VERSION 5.8 ;
BUSBITCHARS "[]" ;
DIVIDERCHAR "/" ;
UNITS
    DATABASE MICRONS 1000 ;
END UNITS

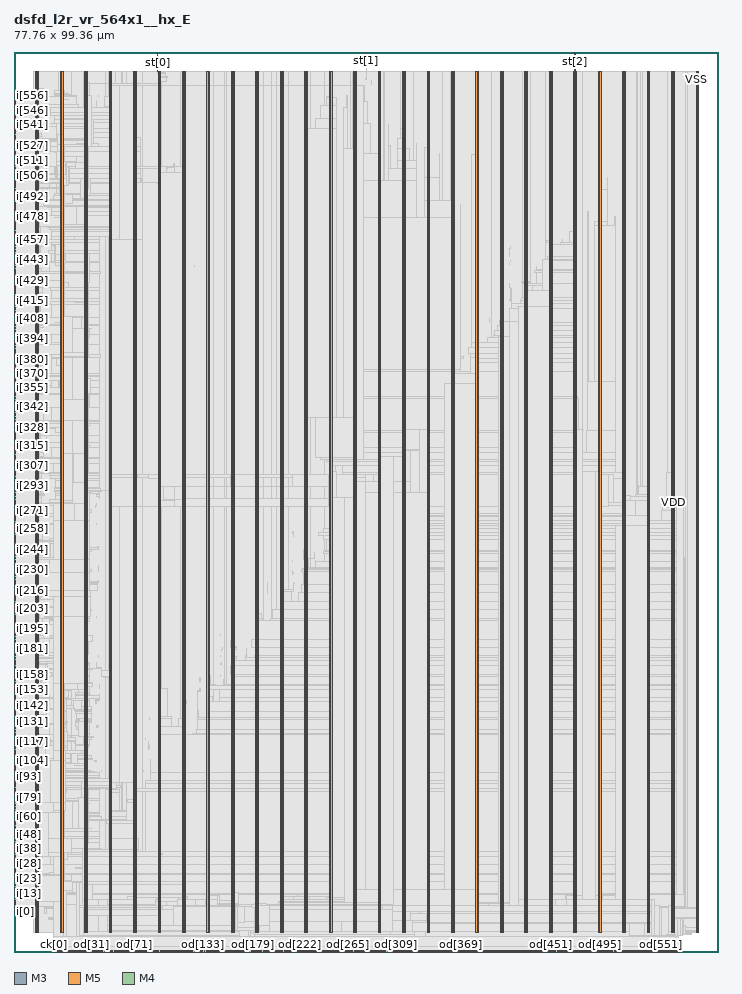
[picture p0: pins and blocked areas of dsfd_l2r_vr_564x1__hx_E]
MACRO dsfd_l2r_vr_564x1__hx_E
  FOREIGN dsfd_l2r_vr_564x1__hx_E 0 0 ;
  CLASS BLOCK ;
  SIZE 77.76 BY 99.36 ;
  PIN ck[0]
    DIRECTION INPUT ;
    USE SIGNAL ;
    PORT
      LAYER M3 ;
        RECT  4.356 0 4.374 0.144 ;
    END
  END ck[0]
  PIN cks[0]
    DIRECTION INPUT ;
    USE SIGNAL ;
    PORT
      LAYER M5 ;
        RECT  4.512 0 4.536 0.192 ;
    END
    PORT
      LAYER M5 ;
        RECT  4.368 0.133 4.632 0.144 ;
    END
  END cks[0]
  PIN fo[0]
    DIRECTION OUTPUT ;
    USE SIGNAL ;
    PORT
      LAYER M3 ;
        RECT  4.608 0 4.626 0.144 ;
    END
  END fo[0]
  PIN i[0]
    DIRECTION INPUT ;
    USE SIGNAL ;
    PORT
      LAYER M4 ;
        RECT  0 4.416 0.192 4.44 ;
    END
  END i[0]
  PIN i[100]
    DIRECTION INPUT ;
    USE SIGNAL ;
    PORT
      LAYER M4 ;
        RECT  0 20.448 0.192 20.472 ;
    END
  END i[100]
  PIN i[101]
    DIRECTION INPUT ;
    USE SIGNAL ;
    PORT
      LAYER M4 ;
        RECT  0 20.64 0.192 20.664 ;
    END
  END i[101]
  PIN i[102]
    DIRECTION INPUT ;
    USE SIGNAL ;
    PORT
      LAYER M4 ;
        RECT  0 20.784 0.192 20.808 ;
    END
  END i[102]
  PIN i[103]
    DIRECTION INPUT ;
    USE SIGNAL ;
    PORT
      LAYER M4 ;
        RECT  0 20.928 0.192 20.952 ;
    END
  END i[103]
  PIN i[104]
    DIRECTION INPUT ;
    USE SIGNAL ;
    PORT
      LAYER M4 ;
        RECT  0 21.12 0.192 21.144 ;
    END
  END i[104]
  PIN i[105]
    DIRECTION INPUT ;
    USE SIGNAL ;
    PORT
      LAYER M4 ;
        RECT  0 21.264 0.192 21.288 ;
    END
  END i[105]
  PIN i[106]
    DIRECTION INPUT ;
    USE SIGNAL ;
    PORT
      LAYER M4 ;
        RECT  0 21.456 0.192 21.48 ;
    END
  END i[106]
  PIN i[107]
    DIRECTION INPUT ;
    USE SIGNAL ;
    PORT
      LAYER M4 ;
        RECT  0 21.6 0.192 21.624 ;
    END
  END i[107]
  PIN i[108]
    DIRECTION INPUT ;
    USE SIGNAL ;
    PORT
      LAYER M4 ;
        RECT  0 21.744 0.192 21.768 ;
    END
  END i[108]
  PIN i[109]
    DIRECTION INPUT ;
    USE SIGNAL ;
    PORT
      LAYER M4 ;
        RECT  0 21.936 0.192 21.96 ;
    END
  END i[109]
  PIN i[10]
    DIRECTION INPUT ;
    USE SIGNAL ;
    PORT
      LAYER M4 ;
        RECT  0 6 0.192 6.024 ;
    END
  END i[10]
  PIN i[110]
    DIRECTION INPUT ;
    USE SIGNAL ;
    PORT
      LAYER M4 ;
        RECT  0 22.08 0.192 22.104 ;
    END
  END i[110]
  PIN i[111]
    DIRECTION INPUT ;
    USE SIGNAL ;
    PORT
      LAYER M4 ;
        RECT  0 22.224 0.192 22.248 ;
    END
  END i[111]
  PIN i[112]
    DIRECTION INPUT ;
    USE SIGNAL ;
    PORT
      LAYER M4 ;
        RECT  0 22.416 0.192 22.44 ;
    END
  END i[112]
  PIN i[113]
    DIRECTION INPUT ;
    USE SIGNAL ;
    PORT
      LAYER M4 ;
        RECT  0 22.56 0.192 22.584 ;
    END
  END i[113]
  PIN i[114]
    DIRECTION INPUT ;
    USE SIGNAL ;
    PORT
      LAYER M4 ;
        RECT  0 22.704 0.192 22.728 ;
    END
  END i[114]
  PIN i[115]
    DIRECTION INPUT ;
    USE SIGNAL ;
    PORT
      LAYER M4 ;
        RECT  0 22.896 0.192 22.92 ;
    END
  END i[115]
  PIN i[116]
    DIRECTION INPUT ;
    USE SIGNAL ;
    PORT
      LAYER M4 ;
        RECT  0 23.04 0.192 23.064 ;
    END
  END i[116]
  PIN i[117]
    DIRECTION INPUT ;
    USE SIGNAL ;
    PORT
      LAYER M4 ;
        RECT  0 23.184 0.192 23.208 ;
    END
  END i[117]
  PIN i[118]
    DIRECTION INPUT ;
    USE SIGNAL ;
    PORT
      LAYER M4 ;
        RECT  0 23.376 0.192 23.4 ;
    END
  END i[118]
  PIN i[119]
    DIRECTION INPUT ;
    USE SIGNAL ;
    PORT
      LAYER M4 ;
        RECT  0 23.52 0.192 23.544 ;
    END
  END i[119]
  PIN i[11]
    DIRECTION INPUT ;
    USE SIGNAL ;
    PORT
      LAYER M4 ;
        RECT  0 6.192 0.192 6.216 ;
    END
  END i[11]
  PIN i[120]
    DIRECTION INPUT ;
    USE SIGNAL ;
    PORT
      LAYER M4 ;
        RECT  0 23.664 0.192 23.688 ;
    END
  END i[120]
  PIN i[121]
    DIRECTION INPUT ;
    USE SIGNAL ;
    PORT
      LAYER M4 ;
        RECT  0 23.856 0.192 23.88 ;
    END
  END i[121]
  PIN i[122]
    DIRECTION INPUT ;
    USE SIGNAL ;
    PORT
      LAYER M4 ;
        RECT  0 24 0.192 24.024 ;
    END
  END i[122]
  PIN i[123]
    DIRECTION INPUT ;
    USE SIGNAL ;
    PORT
      LAYER M4 ;
        RECT  0 24.144 0.192 24.168 ;
    END
  END i[123]
  PIN i[124]
    DIRECTION INPUT ;
    USE SIGNAL ;
    PORT
      LAYER M4 ;
        RECT  0 24.336 0.192 24.36 ;
    END
  END i[124]
  PIN i[125]
    DIRECTION INPUT ;
    USE SIGNAL ;
    PORT
      LAYER M4 ;
        RECT  0 24.48 0.192 24.504 ;
    END
  END i[125]
  PIN i[126]
    DIRECTION INPUT ;
    USE SIGNAL ;
    PORT
      LAYER M4 ;
        RECT  0 24.624 0.192 24.648 ;
    END
  END i[126]
  PIN i[127]
    DIRECTION INPUT ;
    USE SIGNAL ;
    PORT
      LAYER M4 ;
        RECT  0 24.816 0.192 24.84 ;
    END
  END i[127]
  PIN i[128]
    DIRECTION INPUT ;
    USE SIGNAL ;
    PORT
      LAYER M4 ;
        RECT  0 24.96 0.192 24.984 ;
    END
  END i[128]
  PIN i[129]
    DIRECTION INPUT ;
    USE SIGNAL ;
    PORT
      LAYER M4 ;
        RECT  0 25.104 0.192 25.128 ;
    END
  END i[129]
  PIN i[12]
    DIRECTION INPUT ;
    USE SIGNAL ;
    PORT
      LAYER M4 ;
        RECT  0 6.336 0.192 6.36 ;
    END
  END i[12]
  PIN i[130]
    DIRECTION INPUT ;
    USE SIGNAL ;
    PORT
      LAYER M4 ;
        RECT  0 25.296 0.192 25.32 ;
    END
  END i[130]
  PIN i[131]
    DIRECTION INPUT ;
    USE SIGNAL ;
    PORT
      LAYER M4 ;
        RECT  0 25.44 0.192 25.464 ;
    END
  END i[131]
  PIN i[132]
    DIRECTION INPUT ;
    USE SIGNAL ;
    PORT
      LAYER M4 ;
        RECT  0 25.584 0.192 25.608 ;
    END
  END i[132]
  PIN i[133]
    DIRECTION INPUT ;
    USE SIGNAL ;
    PORT
      LAYER M4 ;
        RECT  0 25.776 0.192 25.8 ;
    END
  END i[133]
  PIN i[134]
    DIRECTION INPUT ;
    USE SIGNAL ;
    PORT
      LAYER M4 ;
        RECT  0 25.92 0.192 25.944 ;
    END
  END i[134]
  PIN i[135]
    DIRECTION INPUT ;
    USE SIGNAL ;
    PORT
      LAYER M4 ;
        RECT  0 26.112 0.192 26.136 ;
    END
  END i[135]
  PIN i[136]
    DIRECTION INPUT ;
    USE SIGNAL ;
    PORT
      LAYER M4 ;
        RECT  0 26.256 0.192 26.28 ;
    END
  END i[136]
  PIN i[137]
    DIRECTION INPUT ;
    USE SIGNAL ;
    PORT
      LAYER M4 ;
        RECT  0 26.4 0.192 26.424 ;
    END
  END i[137]
  PIN i[138]
    DIRECTION INPUT ;
    USE SIGNAL ;
    PORT
      LAYER M4 ;
        RECT  0 26.592 0.192 26.616 ;
    END
  END i[138]
  PIN i[139]
    DIRECTION INPUT ;
    USE SIGNAL ;
    PORT
      LAYER M4 ;
        RECT  0 26.736 0.192 26.76 ;
    END
  END i[139]
  PIN i[13]
    DIRECTION INPUT ;
    USE SIGNAL ;
    PORT
      LAYER M4 ;
        RECT  0 6.48 0.192 6.504 ;
    END
  END i[13]
  PIN i[140]
    DIRECTION INPUT ;
    USE SIGNAL ;
    PORT
      LAYER M4 ;
        RECT  0 26.88 0.192 26.904 ;
    END
  END i[140]
  PIN i[141]
    DIRECTION INPUT ;
    USE SIGNAL ;
    PORT
      LAYER M4 ;
        RECT  0 27.072 0.192 27.096 ;
    END
  END i[141]
  PIN i[142]
    DIRECTION INPUT ;
    USE SIGNAL ;
    PORT
      LAYER M4 ;
        RECT  0 27.216 0.192 27.24 ;
    END
  END i[142]
  PIN i[143]
    DIRECTION INPUT ;
    USE SIGNAL ;
    PORT
      LAYER M4 ;
        RECT  0 27.36 0.192 27.384 ;
    END
  END i[143]
  PIN i[144]
    DIRECTION INPUT ;
    USE SIGNAL ;
    PORT
      LAYER M4 ;
        RECT  0 27.552 0.192 27.576 ;
    END
  END i[144]
  PIN i[145]
    DIRECTION INPUT ;
    USE SIGNAL ;
    PORT
      LAYER M4 ;
        RECT  0 27.696 0.192 27.72 ;
    END
  END i[145]
  PIN i[146]
    DIRECTION INPUT ;
    USE SIGNAL ;
    PORT
      LAYER M4 ;
        RECT  0 27.84 0.192 27.864 ;
    END
  END i[146]
  PIN i[147]
    DIRECTION INPUT ;
    USE SIGNAL ;
    PORT
      LAYER M4 ;
        RECT  0 28.032 0.192 28.056 ;
    END
  END i[147]
  PIN i[148]
    DIRECTION INPUT ;
    USE SIGNAL ;
    PORT
      LAYER M4 ;
        RECT  0 28.176 0.192 28.2 ;
    END
  END i[148]
  PIN i[149]
    DIRECTION INPUT ;
    USE SIGNAL ;
    PORT
      LAYER M4 ;
        RECT  0 28.32 0.192 28.344 ;
    END
  END i[149]
  PIN i[14]
    DIRECTION INPUT ;
    USE SIGNAL ;
    PORT
      LAYER M4 ;
        RECT  0 6.672 0.192 6.696 ;
    END
  END i[14]
  PIN i[150]
    DIRECTION INPUT ;
    USE SIGNAL ;
    PORT
      LAYER M4 ;
        RECT  0 28.512 0.192 28.536 ;
    END
  END i[150]
  PIN i[151]
    DIRECTION INPUT ;
    USE SIGNAL ;
    PORT
      LAYER M4 ;
        RECT  0 28.656 0.192 28.68 ;
    END
  END i[151]
  PIN i[152]
    DIRECTION INPUT ;
    USE SIGNAL ;
    PORT
      LAYER M4 ;
        RECT  0 28.8 0.192 28.824 ;
    END
  END i[152]
  PIN i[153]
    DIRECTION INPUT ;
    USE SIGNAL ;
    PORT
      LAYER M4 ;
        RECT  0 28.992 0.192 29.016 ;
    END
  END i[153]
  PIN i[154]
    DIRECTION INPUT ;
    USE SIGNAL ;
    PORT
      LAYER M4 ;
        RECT  0 29.136 0.192 29.16 ;
    END
  END i[154]
  PIN i[155]
    DIRECTION INPUT ;
    USE SIGNAL ;
    PORT
      LAYER M4 ;
        RECT  0 29.28 0.192 29.304 ;
    END
  END i[155]
  PIN i[156]
    DIRECTION INPUT ;
    USE SIGNAL ;
    PORT
      LAYER M4 ;
        RECT  0 29.472 0.192 29.496 ;
    END
  END i[156]
  PIN i[157]
    DIRECTION INPUT ;
    USE SIGNAL ;
    PORT
      LAYER M4 ;
        RECT  0 29.616 0.192 29.64 ;
    END
  END i[157]
  PIN i[158]
    DIRECTION INPUT ;
    USE SIGNAL ;
    PORT
      LAYER M4 ;
        RECT  0 29.76 0.192 29.784 ;
    END
  END i[158]
  PIN i[159]
    DIRECTION INPUT ;
    USE SIGNAL ;
    PORT
      LAYER M4 ;
        RECT  0 29.952 0.192 29.976 ;
    END
  END i[159]
  PIN i[15]
    DIRECTION INPUT ;
    USE SIGNAL ;
    PORT
      LAYER M4 ;
        RECT  0 6.816 0.192 6.84 ;
    END
  END i[15]
  PIN i[160]
    DIRECTION INPUT ;
    USE SIGNAL ;
    PORT
      LAYER M4 ;
        RECT  0 30.096 0.192 30.12 ;
    END
  END i[160]
  PIN i[161]
    DIRECTION INPUT ;
    USE SIGNAL ;
    PORT
      LAYER M4 ;
        RECT  0 30.24 0.192 30.264 ;
    END
  END i[161]
  PIN i[162]
    DIRECTION INPUT ;
    USE SIGNAL ;
    PORT
      LAYER M4 ;
        RECT  0 30.432 0.192 30.456 ;
    END
  END i[162]
  PIN i[163]
    DIRECTION INPUT ;
    USE SIGNAL ;
    PORT
      LAYER M4 ;
        RECT  0 30.576 0.192 30.6 ;
    END
  END i[163]
  PIN i[164]
    DIRECTION INPUT ;
    USE SIGNAL ;
    PORT
      LAYER M4 ;
        RECT  0 30.768 0.192 30.792 ;
    END
  END i[164]
  PIN i[165]
    DIRECTION INPUT ;
    USE SIGNAL ;
    PORT
      LAYER M4 ;
        RECT  0 30.912 0.192 30.936 ;
    END
  END i[165]
  PIN i[166]
    DIRECTION INPUT ;
    USE SIGNAL ;
    PORT
      LAYER M4 ;
        RECT  0 31.056 0.192 31.08 ;
    END
  END i[166]
  PIN i[167]
    DIRECTION INPUT ;
    USE SIGNAL ;
    PORT
      LAYER M4 ;
        RECT  0 31.248 0.192 31.272 ;
    END
  END i[167]
  PIN i[168]
    DIRECTION INPUT ;
    USE SIGNAL ;
    PORT
      LAYER M4 ;
        RECT  0 31.392 0.192 31.416 ;
    END
  END i[168]
  PIN i[169]
    DIRECTION INPUT ;
    USE SIGNAL ;
    PORT
      LAYER M4 ;
        RECT  0 31.536 0.192 31.56 ;
    END
  END i[169]
  PIN i[16]
    DIRECTION INPUT ;
    USE SIGNAL ;
    PORT
      LAYER M4 ;
        RECT  0 6.96 0.192 6.984 ;
    END
  END i[16]
  PIN i[170]
    DIRECTION INPUT ;
    USE SIGNAL ;
    PORT
      LAYER M4 ;
        RECT  0 31.728 0.192 31.752 ;
    END
  END i[170]
  PIN i[171]
    DIRECTION INPUT ;
    USE SIGNAL ;
    PORT
      LAYER M4 ;
        RECT  0 31.872 0.192 31.896 ;
    END
  END i[171]
  PIN i[172]
    DIRECTION INPUT ;
    USE SIGNAL ;
    PORT
      LAYER M4 ;
        RECT  0 32.016 0.192 32.04 ;
    END
  END i[172]
  PIN i[173]
    DIRECTION INPUT ;
    USE SIGNAL ;
    PORT
      LAYER M4 ;
        RECT  0 32.208 0.192 32.232 ;
    END
  END i[173]
  PIN i[174]
    DIRECTION INPUT ;
    USE SIGNAL ;
    PORT
      LAYER M4 ;
        RECT  0 32.352 0.192 32.376 ;
    END
  END i[174]
  PIN i[175]
    DIRECTION INPUT ;
    USE SIGNAL ;
    PORT
      LAYER M4 ;
        RECT  0 32.496 0.192 32.52 ;
    END
  END i[175]
  PIN i[176]
    DIRECTION INPUT ;
    USE SIGNAL ;
    PORT
      LAYER M4 ;
        RECT  0 32.688 0.192 32.712 ;
    END
  END i[176]
  PIN i[177]
    DIRECTION INPUT ;
    USE SIGNAL ;
    PORT
      LAYER M4 ;
        RECT  0 32.832 0.192 32.856 ;
    END
  END i[177]
  PIN i[178]
    DIRECTION INPUT ;
    USE SIGNAL ;
    PORT
      LAYER M4 ;
        RECT  0 32.976 0.192 33 ;
    END
  END i[178]
  PIN i[179]
    DIRECTION INPUT ;
    USE SIGNAL ;
    PORT
      LAYER M4 ;
        RECT  0 33.168 0.192 33.192 ;
    END
  END i[179]
  PIN i[17]
    DIRECTION INPUT ;
    USE SIGNAL ;
    PORT
      LAYER M4 ;
        RECT  0 7.152 0.192 7.176 ;
    END
  END i[17]
  PIN i[180]
    DIRECTION INPUT ;
    USE SIGNAL ;
    PORT
      LAYER M4 ;
        RECT  0 33.312 0.192 33.336 ;
    END
  END i[180]
  PIN i[181]
    DIRECTION INPUT ;
    USE SIGNAL ;
    PORT
      LAYER M4 ;
        RECT  0 33.456 0.192 33.48 ;
    END
  END i[181]
  PIN i[182]
    DIRECTION INPUT ;
    USE SIGNAL ;
    PORT
      LAYER M4 ;
        RECT  0 33.648 0.192 33.672 ;
    END
  END i[182]
  PIN i[183]
    DIRECTION INPUT ;
    USE SIGNAL ;
    PORT
      LAYER M4 ;
        RECT  0 33.792 0.192 33.816 ;
    END
  END i[183]
  PIN i[184]
    DIRECTION INPUT ;
    USE SIGNAL ;
    PORT
      LAYER M4 ;
        RECT  0 33.936 0.192 33.96 ;
    END
  END i[184]
  PIN i[185]
    DIRECTION INPUT ;
    USE SIGNAL ;
    PORT
      LAYER M4 ;
        RECT  0 34.128 0.192 34.152 ;
    END
  END i[185]
  PIN i[186]
    DIRECTION INPUT ;
    USE SIGNAL ;
    PORT
      LAYER M4 ;
        RECT  0 34.272 0.192 34.296 ;
    END
  END i[186]
  PIN i[187]
    DIRECTION INPUT ;
    USE SIGNAL ;
    PORT
      LAYER M4 ;
        RECT  0 34.416 0.192 34.44 ;
    END
  END i[187]
  PIN i[188]
    DIRECTION INPUT ;
    USE SIGNAL ;
    PORT
      LAYER M4 ;
        RECT  0 34.608 0.192 34.632 ;
    END
  END i[188]
  PIN i[189]
    DIRECTION INPUT ;
    USE SIGNAL ;
    PORT
      LAYER M4 ;
        RECT  0 34.752 0.192 34.776 ;
    END
  END i[189]
  PIN i[18]
    DIRECTION INPUT ;
    USE SIGNAL ;
    PORT
      LAYER M4 ;
        RECT  0 7.296 0.192 7.32 ;
    END
  END i[18]
  PIN i[190]
    DIRECTION INPUT ;
    USE SIGNAL ;
    PORT
      LAYER M4 ;
        RECT  0 34.896 0.192 34.92 ;
    END
  END i[190]
  PIN i[191]
    DIRECTION INPUT ;
    USE SIGNAL ;
    PORT
      LAYER M4 ;
        RECT  0 35.088 0.192 35.112 ;
    END
  END i[191]
  PIN i[192]
    DIRECTION INPUT ;
    USE SIGNAL ;
    PORT
      LAYER M4 ;
        RECT  0 35.232 0.192 35.256 ;
    END
  END i[192]
  PIN i[193]
    DIRECTION INPUT ;
    USE SIGNAL ;
    PORT
      LAYER M4 ;
        RECT  0 35.424 0.192 35.448 ;
    END
  END i[193]
  PIN i[194]
    DIRECTION INPUT ;
    USE SIGNAL ;
    PORT
      LAYER M4 ;
        RECT  0 35.568 0.192 35.592 ;
    END
  END i[194]
  PIN i[195]
    DIRECTION INPUT ;
    USE SIGNAL ;
    PORT
      LAYER M4 ;
        RECT  0 35.712 0.192 35.736 ;
    END
  END i[195]
  PIN i[196]
    DIRECTION INPUT ;
    USE SIGNAL ;
    PORT
      LAYER M4 ;
        RECT  0 35.904 0.192 35.928 ;
    END
  END i[196]
  PIN i[197]
    DIRECTION INPUT ;
    USE SIGNAL ;
    PORT
      LAYER M4 ;
        RECT  0 36.048 0.192 36.072 ;
    END
  END i[197]
  PIN i[198]
    DIRECTION INPUT ;
    USE SIGNAL ;
    PORT
      LAYER M4 ;
        RECT  0 36.192 0.192 36.216 ;
    END
  END i[198]
  PIN i[199]
    DIRECTION INPUT ;
    USE SIGNAL ;
    PORT
      LAYER M4 ;
        RECT  0 36.384 0.192 36.408 ;
    END
  END i[199]
  PIN i[19]
    DIRECTION INPUT ;
    USE SIGNAL ;
    PORT
      LAYER M4 ;
        RECT  0 7.44 0.192 7.464 ;
    END
  END i[19]
  PIN i[1]
    DIRECTION INPUT ;
    USE SIGNAL ;
    PORT
      LAYER M4 ;
        RECT  0 4.56 0.192 4.584 ;
    END
  END i[1]
  PIN i[200]
    DIRECTION INPUT ;
    USE SIGNAL ;
    PORT
      LAYER M4 ;
        RECT  0 36.528 0.192 36.552 ;
    END
  END i[200]
  PIN i[201]
    DIRECTION INPUT ;
    USE SIGNAL ;
    PORT
      LAYER M4 ;
        RECT  0 36.672 0.192 36.696 ;
    END
  END i[201]
  PIN i[202]
    DIRECTION INPUT ;
    USE SIGNAL ;
    PORT
      LAYER M4 ;
        RECT  0 36.864 0.192 36.888 ;
    END
  END i[202]
  PIN i[203]
    DIRECTION INPUT ;
    USE SIGNAL ;
    PORT
      LAYER M4 ;
        RECT  0 37.008 0.192 37.032 ;
    END
  END i[203]
  PIN i[204]
    DIRECTION INPUT ;
    USE SIGNAL ;
    PORT
      LAYER M4 ;
        RECT  0 37.152 0.192 37.176 ;
    END
  END i[204]
  PIN i[205]
    DIRECTION INPUT ;
    USE SIGNAL ;
    PORT
      LAYER M4 ;
        RECT  0 37.344 0.192 37.368 ;
    END
  END i[205]
  PIN i[206]
    DIRECTION INPUT ;
    USE SIGNAL ;
    PORT
      LAYER M4 ;
        RECT  0 37.488 0.192 37.512 ;
    END
  END i[206]
  PIN i[207]
    DIRECTION INPUT ;
    USE SIGNAL ;
    PORT
      LAYER M4 ;
        RECT  0 37.632 0.192 37.656 ;
    END
  END i[207]
  PIN i[208]
    DIRECTION INPUT ;
    USE SIGNAL ;
    PORT
      LAYER M4 ;
        RECT  0 37.824 0.192 37.848 ;
    END
  END i[208]
  PIN i[209]
    DIRECTION INPUT ;
    USE SIGNAL ;
    PORT
      LAYER M4 ;
        RECT  0 37.968 0.192 37.992 ;
    END
  END i[209]
  PIN i[20]
    DIRECTION INPUT ;
    USE SIGNAL ;
    PORT
      LAYER M4 ;
        RECT  0 7.632 0.192 7.656 ;
    END
  END i[20]
  PIN i[210]
    DIRECTION INPUT ;
    USE SIGNAL ;
    PORT
      LAYER M4 ;
        RECT  0 38.112 0.192 38.136 ;
    END
  END i[210]
  PIN i[211]
    DIRECTION INPUT ;
    USE SIGNAL ;
    PORT
      LAYER M4 ;
        RECT  0 38.304 0.192 38.328 ;
    END
  END i[211]
  PIN i[212]
    DIRECTION INPUT ;
    USE SIGNAL ;
    PORT
      LAYER M4 ;
        RECT  0 38.448 0.192 38.472 ;
    END
  END i[212]
  PIN i[213]
    DIRECTION INPUT ;
    USE SIGNAL ;
    PORT
      LAYER M4 ;
        RECT  0 38.592 0.192 38.616 ;
    END
  END i[213]
  PIN i[214]
    DIRECTION INPUT ;
    USE SIGNAL ;
    PORT
      LAYER M4 ;
        RECT  0 38.784 0.192 38.808 ;
    END
  END i[214]
  PIN i[215]
    DIRECTION INPUT ;
    USE SIGNAL ;
    PORT
      LAYER M4 ;
        RECT  0 38.928 0.192 38.952 ;
    END
  END i[215]
  PIN i[216]
    DIRECTION INPUT ;
    USE SIGNAL ;
    PORT
      LAYER M4 ;
        RECT  0 39.072 0.192 39.096 ;
    END
  END i[216]
  PIN i[217]
    DIRECTION INPUT ;
    USE SIGNAL ;
    PORT
      LAYER M4 ;
        RECT  0 39.264 0.192 39.288 ;
    END
  END i[217]
  PIN i[218]
    DIRECTION INPUT ;
    USE SIGNAL ;
    PORT
      LAYER M4 ;
        RECT  0 39.408 0.192 39.432 ;
    END
  END i[218]
  PIN i[219]
    DIRECTION INPUT ;
    USE SIGNAL ;
    PORT
      LAYER M4 ;
        RECT  0 39.6 0.192 39.624 ;
    END
  END i[219]
  PIN i[21]
    DIRECTION INPUT ;
    USE SIGNAL ;
    PORT
      LAYER M4 ;
        RECT  0 7.776 0.192 7.8 ;
    END
  END i[21]
  PIN i[220]
    DIRECTION INPUT ;
    USE SIGNAL ;
    PORT
      LAYER M4 ;
        RECT  0 39.744 0.192 39.768 ;
    END
  END i[220]
  PIN i[221]
    DIRECTION INPUT ;
    USE SIGNAL ;
    PORT
      LAYER M4 ;
        RECT  0 39.888 0.192 39.912 ;
    END
  END i[221]
  PIN i[222]
    DIRECTION INPUT ;
    USE SIGNAL ;
    PORT
      LAYER M4 ;
        RECT  0 40.08 0.192 40.104 ;
    END
  END i[222]
  PIN i[223]
    DIRECTION INPUT ;
    USE SIGNAL ;
    PORT
      LAYER M4 ;
        RECT  0 40.224 0.192 40.248 ;
    END
  END i[223]
  PIN i[224]
    DIRECTION INPUT ;
    USE SIGNAL ;
    PORT
      LAYER M4 ;
        RECT  0 40.368 0.192 40.392 ;
    END
  END i[224]
  PIN i[225]
    DIRECTION INPUT ;
    USE SIGNAL ;
    PORT
      LAYER M4 ;
        RECT  0 40.56 0.192 40.584 ;
    END
  END i[225]
  PIN i[226]
    DIRECTION INPUT ;
    USE SIGNAL ;
    PORT
      LAYER M4 ;
        RECT  0 40.704 0.192 40.728 ;
    END
  END i[226]
  PIN i[227]
    DIRECTION INPUT ;
    USE SIGNAL ;
    PORT
      LAYER M4 ;
        RECT  0 40.848 0.192 40.872 ;
    END
  END i[227]
  PIN i[228]
    DIRECTION INPUT ;
    USE SIGNAL ;
    PORT
      LAYER M4 ;
        RECT  0 41.04 0.192 41.064 ;
    END
  END i[228]
  PIN i[229]
    DIRECTION INPUT ;
    USE SIGNAL ;
    PORT
      LAYER M4 ;
        RECT  0 41.184 0.192 41.208 ;
    END
  END i[229]
  PIN i[22]
    DIRECTION INPUT ;
    USE SIGNAL ;
    PORT
      LAYER M4 ;
        RECT  0 7.968 0.192 7.992 ;
    END
  END i[22]
  PIN i[230]
    DIRECTION INPUT ;
    USE SIGNAL ;
    PORT
      LAYER M4 ;
        RECT  0 41.328 0.192 41.352 ;
    END
  END i[230]
  PIN i[231]
    DIRECTION INPUT ;
    USE SIGNAL ;
    PORT
      LAYER M4 ;
        RECT  0 41.52 0.192 41.544 ;
    END
  END i[231]
  PIN i[232]
    DIRECTION INPUT ;
    USE SIGNAL ;
    PORT
      LAYER M4 ;
        RECT  0 41.664 0.192 41.688 ;
    END
  END i[232]
  PIN i[233]
    DIRECTION INPUT ;
    USE SIGNAL ;
    PORT
      LAYER M4 ;
        RECT  0 41.808 0.192 41.832 ;
    END
  END i[233]
  PIN i[234]
    DIRECTION INPUT ;
    USE SIGNAL ;
    PORT
      LAYER M4 ;
        RECT  0 42 0.192 42.024 ;
    END
  END i[234]
  PIN i[235]
    DIRECTION INPUT ;
    USE SIGNAL ;
    PORT
      LAYER M4 ;
        RECT  0 42.144 0.192 42.168 ;
    END
  END i[235]
  PIN i[236]
    DIRECTION INPUT ;
    USE SIGNAL ;
    PORT
      LAYER M4 ;
        RECT  0 42.288 0.192 42.312 ;
    END
  END i[236]
  PIN i[237]
    DIRECTION INPUT ;
    USE SIGNAL ;
    PORT
      LAYER M4 ;
        RECT  0 42.48 0.192 42.504 ;
    END
  END i[237]
  PIN i[238]
    DIRECTION INPUT ;
    USE SIGNAL ;
    PORT
      LAYER M4 ;
        RECT  0 42.624 0.192 42.648 ;
    END
  END i[238]
  PIN i[239]
    DIRECTION INPUT ;
    USE SIGNAL ;
    PORT
      LAYER M4 ;
        RECT  0 42.768 0.192 42.792 ;
    END
  END i[239]
  PIN i[23]
    DIRECTION INPUT ;
    USE SIGNAL ;
    PORT
      LAYER M4 ;
        RECT  0 8.112 0.192 8.136 ;
    END
  END i[23]
  PIN i[240]
    DIRECTION INPUT ;
    USE SIGNAL ;
    PORT
      LAYER M4 ;
        RECT  0 42.96 0.192 42.984 ;
    END
  END i[240]
  PIN i[241]
    DIRECTION INPUT ;
    USE SIGNAL ;
    PORT
      LAYER M4 ;
        RECT  0 43.104 0.192 43.128 ;
    END
  END i[241]
  PIN i[242]
    DIRECTION INPUT ;
    USE SIGNAL ;
    PORT
      LAYER M4 ;
        RECT  0 43.248 0.192 43.272 ;
    END
  END i[242]
  PIN i[243]
    DIRECTION INPUT ;
    USE SIGNAL ;
    PORT
      LAYER M4 ;
        RECT  0 43.44 0.192 43.464 ;
    END
  END i[243]
  PIN i[244]
    DIRECTION INPUT ;
    USE SIGNAL ;
    PORT
      LAYER M4 ;
        RECT  0 43.584 0.192 43.608 ;
    END
  END i[244]
  PIN i[245]
    DIRECTION INPUT ;
    USE SIGNAL ;
    PORT
      LAYER M4 ;
        RECT  0 43.728 0.192 43.752 ;
    END
  END i[245]
  PIN i[246]
    DIRECTION INPUT ;
    USE SIGNAL ;
    PORT
      LAYER M4 ;
        RECT  0 43.92 0.192 43.944 ;
    END
  END i[246]
  PIN i[247]
    DIRECTION INPUT ;
    USE SIGNAL ;
    PORT
      LAYER M4 ;
        RECT  0 44.064 0.192 44.088 ;
    END
  END i[247]
  PIN i[248]
    DIRECTION INPUT ;
    USE SIGNAL ;
    PORT
      LAYER M4 ;
        RECT  0 44.256 0.192 44.28 ;
    END
  END i[248]
  PIN i[249]
    DIRECTION INPUT ;
    USE SIGNAL ;
    PORT
      LAYER M4 ;
        RECT  0 44.4 0.192 44.424 ;
    END
  END i[249]
  PIN i[24]
    DIRECTION INPUT ;
    USE SIGNAL ;
    PORT
      LAYER M4 ;
        RECT  0 8.256 0.192 8.28 ;
    END
  END i[24]
  PIN i[250]
    DIRECTION INPUT ;
    USE SIGNAL ;
    PORT
      LAYER M4 ;
        RECT  0 44.544 0.192 44.568 ;
    END
  END i[250]
  PIN i[251]
    DIRECTION INPUT ;
    USE SIGNAL ;
    PORT
      LAYER M4 ;
        RECT  0 44.736 0.192 44.76 ;
    END
  END i[251]
  PIN i[252]
    DIRECTION INPUT ;
    USE SIGNAL ;
    PORT
      LAYER M4 ;
        RECT  0 44.88 0.192 44.904 ;
    END
  END i[252]
  PIN i[253]
    DIRECTION INPUT ;
    USE SIGNAL ;
    PORT
      LAYER M4 ;
        RECT  0 45.024 0.192 45.048 ;
    END
  END i[253]
  PIN i[254]
    DIRECTION INPUT ;
    USE SIGNAL ;
    PORT
      LAYER M4 ;
        RECT  0 45.216 0.192 45.24 ;
    END
  END i[254]
  PIN i[255]
    DIRECTION INPUT ;
    USE SIGNAL ;
    PORT
      LAYER M4 ;
        RECT  0 45.36 0.192 45.384 ;
    END
  END i[255]
  PIN i[256]
    DIRECTION INPUT ;
    USE SIGNAL ;
    PORT
      LAYER M4 ;
        RECT  0 45.504 0.192 45.528 ;
    END
  END i[256]
  PIN i[257]
    DIRECTION INPUT ;
    USE SIGNAL ;
    PORT
      LAYER M4 ;
        RECT  0 45.696 0.192 45.72 ;
    END
  END i[257]
  PIN i[258]
    DIRECTION INPUT ;
    USE SIGNAL ;
    PORT
      LAYER M4 ;
        RECT  0 45.84 0.192 45.864 ;
    END
  END i[258]
  PIN i[259]
    DIRECTION INPUT ;
    USE SIGNAL ;
    PORT
      LAYER M4 ;
        RECT  0 45.984 0.192 46.008 ;
    END
  END i[259]
  PIN i[25]
    DIRECTION INPUT ;
    USE SIGNAL ;
    PORT
      LAYER M4 ;
        RECT  0 8.448 0.192 8.472 ;
    END
  END i[25]
  PIN i[260]
    DIRECTION INPUT ;
    USE SIGNAL ;
    PORT
      LAYER M4 ;
        RECT  0 46.176 0.192 46.2 ;
    END
  END i[260]
  PIN i[261]
    DIRECTION INPUT ;
    USE SIGNAL ;
    PORT
      LAYER M4 ;
        RECT  0 46.32 0.192 46.344 ;
    END
  END i[261]
  PIN i[262]
    DIRECTION INPUT ;
    USE SIGNAL ;
    PORT
      LAYER M4 ;
        RECT  0 46.464 0.192 46.488 ;
    END
  END i[262]
  PIN i[263]
    DIRECTION INPUT ;
    USE SIGNAL ;
    PORT
      LAYER M4 ;
        RECT  0 46.656 0.192 46.68 ;
    END
  END i[263]
  PIN i[264]
    DIRECTION INPUT ;
    USE SIGNAL ;
    PORT
      LAYER M4 ;
        RECT  0 46.8 0.192 46.824 ;
    END
  END i[264]
  PIN i[265]
    DIRECTION INPUT ;
    USE SIGNAL ;
    PORT
      LAYER M4 ;
        RECT  0 46.944 0.192 46.968 ;
    END
  END i[265]
  PIN i[266]
    DIRECTION INPUT ;
    USE SIGNAL ;
    PORT
      LAYER M4 ;
        RECT  0 47.136 0.192 47.16 ;
    END
  END i[266]
  PIN i[267]
    DIRECTION INPUT ;
    USE SIGNAL ;
    PORT
      LAYER M4 ;
        RECT  0 47.28 0.192 47.304 ;
    END
  END i[267]
  PIN i[268]
    DIRECTION INPUT ;
    USE SIGNAL ;
    PORT
      LAYER M4 ;
        RECT  0 47.424 0.192 47.448 ;
    END
  END i[268]
  PIN i[269]
    DIRECTION INPUT ;
    USE SIGNAL ;
    PORT
      LAYER M4 ;
        RECT  0 47.616 0.192 47.64 ;
    END
  END i[269]
  PIN i[26]
    DIRECTION INPUT ;
    USE SIGNAL ;
    PORT
      LAYER M4 ;
        RECT  0 8.592 0.192 8.616 ;
    END
  END i[26]
  PIN i[270]
    DIRECTION INPUT ;
    USE SIGNAL ;
    PORT
      LAYER M4 ;
        RECT  0 47.76 0.192 47.784 ;
    END
  END i[270]
  PIN i[271]
    DIRECTION INPUT ;
    USE SIGNAL ;
    PORT
      LAYER M4 ;
        RECT  0 47.904 0.192 47.928 ;
    END
  END i[271]
  PIN i[272]
    DIRECTION INPUT ;
    USE SIGNAL ;
    PORT
      LAYER M4 ;
        RECT  0 48.096 0.192 48.12 ;
    END
  END i[272]
  PIN i[273]
    DIRECTION INPUT ;
    USE SIGNAL ;
    PORT
      LAYER M4 ;
        RECT  0 48.24 0.192 48.264 ;
    END
  END i[273]
  PIN i[274]
    DIRECTION INPUT ;
    USE SIGNAL ;
    PORT
      LAYER M4 ;
        RECT  0 48.384 0.192 48.408 ;
    END
  END i[274]
  PIN i[275]
    DIRECTION INPUT ;
    USE SIGNAL ;
    PORT
      LAYER M4 ;
        RECT  0 48.576 0.192 48.6 ;
    END
  END i[275]
  PIN i[276]
    DIRECTION INPUT ;
    USE SIGNAL ;
    PORT
      LAYER M4 ;
        RECT  0 48.72 0.192 48.744 ;
    END
  END i[276]
  PIN i[277]
    DIRECTION INPUT ;
    USE SIGNAL ;
    PORT
      LAYER M4 ;
        RECT  0 48.912 0.192 48.936 ;
    END
  END i[277]
  PIN i[278]
    DIRECTION INPUT ;
    USE SIGNAL ;
    PORT
      LAYER M4 ;
        RECT  0 49.056 0.192 49.08 ;
    END
  END i[278]
  PIN i[279]
    DIRECTION INPUT ;
    USE SIGNAL ;
    PORT
      LAYER M4 ;
        RECT  0 49.2 0.192 49.224 ;
    END
  END i[279]
  PIN i[27]
    DIRECTION INPUT ;
    USE SIGNAL ;
    PORT
      LAYER M4 ;
        RECT  0 8.736 0.192 8.76 ;
    END
  END i[27]
  PIN i[280]
    DIRECTION INPUT ;
    USE SIGNAL ;
    PORT
      LAYER M4 ;
        RECT  0 49.392 0.192 49.416 ;
    END
  END i[280]
  PIN i[281]
    DIRECTION INPUT ;
    USE SIGNAL ;
    PORT
      LAYER M4 ;
        RECT  0 49.536 0.192 49.56 ;
    END
  END i[281]
  PIN i[282]
    DIRECTION INPUT ;
    USE SIGNAL ;
    PORT
      LAYER M4 ;
        RECT  0 49.68 0.192 49.704 ;
    END
  END i[282]
  PIN i[283]
    DIRECTION INPUT ;
    USE SIGNAL ;
    PORT
      LAYER M4 ;
        RECT  0 49.872 0.192 49.896 ;
    END
  END i[283]
  PIN i[284]
    DIRECTION INPUT ;
    USE SIGNAL ;
    PORT
      LAYER M4 ;
        RECT  0 50.016 0.192 50.04 ;
    END
  END i[284]
  PIN i[285]
    DIRECTION INPUT ;
    USE SIGNAL ;
    PORT
      LAYER M4 ;
        RECT  0 50.16 0.192 50.184 ;
    END
  END i[285]
  PIN i[286]
    DIRECTION INPUT ;
    USE SIGNAL ;
    PORT
      LAYER M4 ;
        RECT  0 50.352 0.192 50.376 ;
    END
  END i[286]
  PIN i[287]
    DIRECTION INPUT ;
    USE SIGNAL ;
    PORT
      LAYER M4 ;
        RECT  0 50.496 0.192 50.52 ;
    END
  END i[287]
  PIN i[288]
    DIRECTION INPUT ;
    USE SIGNAL ;
    PORT
      LAYER M4 ;
        RECT  0 50.64 0.192 50.664 ;
    END
  END i[288]
  PIN i[289]
    DIRECTION INPUT ;
    USE SIGNAL ;
    PORT
      LAYER M4 ;
        RECT  0 50.832 0.192 50.856 ;
    END
  END i[289]
  PIN i[28]
    DIRECTION INPUT ;
    USE SIGNAL ;
    PORT
      LAYER M4 ;
        RECT  0 8.928 0.192 8.952 ;
    END
  END i[28]
  PIN i[290]
    DIRECTION INPUT ;
    USE SIGNAL ;
    PORT
      LAYER M4 ;
        RECT  0 50.976 0.192 51 ;
    END
  END i[290]
  PIN i[291]
    DIRECTION INPUT ;
    USE SIGNAL ;
    PORT
      LAYER M4 ;
        RECT  0 51.12 0.192 51.144 ;
    END
  END i[291]
  PIN i[292]
    DIRECTION INPUT ;
    USE SIGNAL ;
    PORT
      LAYER M4 ;
        RECT  0 51.312 0.192 51.336 ;
    END
  END i[292]
  PIN i[293]
    DIRECTION INPUT ;
    USE SIGNAL ;
    PORT
      LAYER M4 ;
        RECT  0 51.456 0.192 51.48 ;
    END
  END i[293]
  PIN i[294]
    DIRECTION INPUT ;
    USE SIGNAL ;
    PORT
      LAYER M4 ;
        RECT  0 51.6 0.192 51.624 ;
    END
  END i[294]
  PIN i[295]
    DIRECTION INPUT ;
    USE SIGNAL ;
    PORT
      LAYER M4 ;
        RECT  0 51.792 0.192 51.816 ;
    END
  END i[295]
  PIN i[296]
    DIRECTION INPUT ;
    USE SIGNAL ;
    PORT
      LAYER M4 ;
        RECT  0 51.936 0.192 51.96 ;
    END
  END i[296]
  PIN i[297]
    DIRECTION INPUT ;
    USE SIGNAL ;
    PORT
      LAYER M4 ;
        RECT  0 52.08 0.192 52.104 ;
    END
  END i[297]
  PIN i[298]
    DIRECTION INPUT ;
    USE SIGNAL ;
    PORT
      LAYER M4 ;
        RECT  0 52.272 0.192 52.296 ;
    END
  END i[298]
  PIN i[299]
    DIRECTION INPUT ;
    USE SIGNAL ;
    PORT
      LAYER M4 ;
        RECT  0 52.416 0.192 52.44 ;
    END
  END i[299]
  PIN i[29]
    DIRECTION INPUT ;
    USE SIGNAL ;
    PORT
      LAYER M4 ;
        RECT  0 9.072 0.192 9.096 ;
    END
  END i[29]
  PIN i[2]
    DIRECTION INPUT ;
    USE SIGNAL ;
    PORT
      LAYER M4 ;
        RECT  0 4.752 0.192 4.776 ;
    END
  END i[2]
  PIN i[300]
    DIRECTION INPUT ;
    USE SIGNAL ;
    PORT
      LAYER M4 ;
        RECT  0 52.56 0.192 52.584 ;
    END
  END i[300]
  PIN i[301]
    DIRECTION INPUT ;
    USE SIGNAL ;
    PORT
      LAYER M4 ;
        RECT  0 52.752 0.192 52.776 ;
    END
  END i[301]
  PIN i[302]
    DIRECTION INPUT ;
    USE SIGNAL ;
    PORT
      LAYER M4 ;
        RECT  0 52.896 0.192 52.92 ;
    END
  END i[302]
  PIN i[303]
    DIRECTION INPUT ;
    USE SIGNAL ;
    PORT
      LAYER M4 ;
        RECT  0 53.04 0.192 53.064 ;
    END
  END i[303]
  PIN i[304]
    DIRECTION INPUT ;
    USE SIGNAL ;
    PORT
      LAYER M4 ;
        RECT  0 53.232 0.192 53.256 ;
    END
  END i[304]
  PIN i[305]
    DIRECTION INPUT ;
    USE SIGNAL ;
    PORT
      LAYER M4 ;
        RECT  0 53.376 0.192 53.4 ;
    END
  END i[305]
  PIN i[306]
    DIRECTION INPUT ;
    USE SIGNAL ;
    PORT
      LAYER M4 ;
        RECT  0 53.568 0.192 53.592 ;
    END
  END i[306]
  PIN i[307]
    DIRECTION INPUT ;
    USE SIGNAL ;
    PORT
      LAYER M4 ;
        RECT  0 53.712 0.192 53.736 ;
    END
  END i[307]
  PIN i[308]
    DIRECTION INPUT ;
    USE SIGNAL ;
    PORT
      LAYER M4 ;
        RECT  0 53.856 0.192 53.88 ;
    END
  END i[308]
  PIN i[309]
    DIRECTION INPUT ;
    USE SIGNAL ;
    PORT
      LAYER M4 ;
        RECT  0 54.048 0.192 54.072 ;
    END
  END i[309]
  PIN i[30]
    DIRECTION INPUT ;
    USE SIGNAL ;
    PORT
      LAYER M4 ;
        RECT  0 9.216 0.192 9.24 ;
    END
  END i[30]
  PIN i[310]
    DIRECTION INPUT ;
    USE SIGNAL ;
    PORT
      LAYER M4 ;
        RECT  0 54.192 0.192 54.216 ;
    END
  END i[310]
  PIN i[311]
    DIRECTION INPUT ;
    USE SIGNAL ;
    PORT
      LAYER M4 ;
        RECT  0 54.336 0.192 54.36 ;
    END
  END i[311]
  PIN i[312]
    DIRECTION INPUT ;
    USE SIGNAL ;
    PORT
      LAYER M4 ;
        RECT  0 54.528 0.192 54.552 ;
    END
  END i[312]
  PIN i[313]
    DIRECTION INPUT ;
    USE SIGNAL ;
    PORT
      LAYER M4 ;
        RECT  0 54.672 0.192 54.696 ;
    END
  END i[313]
  PIN i[314]
    DIRECTION INPUT ;
    USE SIGNAL ;
    PORT
      LAYER M4 ;
        RECT  0 54.816 0.192 54.84 ;
    END
  END i[314]
  PIN i[315]
    DIRECTION INPUT ;
    USE SIGNAL ;
    PORT
      LAYER M4 ;
        RECT  0 55.008 0.192 55.032 ;
    END
  END i[315]
  PIN i[316]
    DIRECTION INPUT ;
    USE SIGNAL ;
    PORT
      LAYER M4 ;
        RECT  0 55.152 0.192 55.176 ;
    END
  END i[316]
  PIN i[317]
    DIRECTION INPUT ;
    USE SIGNAL ;
    PORT
      LAYER M4 ;
        RECT  0 55.296 0.192 55.32 ;
    END
  END i[317]
  PIN i[318]
    DIRECTION INPUT ;
    USE SIGNAL ;
    PORT
      LAYER M4 ;
        RECT  0 55.488 0.192 55.512 ;
    END
  END i[318]
  PIN i[319]
    DIRECTION INPUT ;
    USE SIGNAL ;
    PORT
      LAYER M4 ;
        RECT  0 55.632 0.192 55.656 ;
    END
  END i[319]
  PIN i[31]
    DIRECTION INPUT ;
    USE SIGNAL ;
    PORT
      LAYER M4 ;
        RECT  0 9.408 0.192 9.432 ;
    END
  END i[31]
  PIN i[320]
    DIRECTION INPUT ;
    USE SIGNAL ;
    PORT
      LAYER M4 ;
        RECT  0 55.776 0.192 55.8 ;
    END
  END i[320]
  PIN i[321]
    DIRECTION INPUT ;
    USE SIGNAL ;
    PORT
      LAYER M4 ;
        RECT  0 55.968 0.192 55.992 ;
    END
  END i[321]
  PIN i[322]
    DIRECTION INPUT ;
    USE SIGNAL ;
    PORT
      LAYER M4 ;
        RECT  0 56.112 0.192 56.136 ;
    END
  END i[322]
  PIN i[323]
    DIRECTION INPUT ;
    USE SIGNAL ;
    PORT
      LAYER M4 ;
        RECT  0 56.256 0.192 56.28 ;
    END
  END i[323]
  PIN i[324]
    DIRECTION INPUT ;
    USE SIGNAL ;
    PORT
      LAYER M4 ;
        RECT  0 56.448 0.192 56.472 ;
    END
  END i[324]
  PIN i[325]
    DIRECTION INPUT ;
    USE SIGNAL ;
    PORT
      LAYER M4 ;
        RECT  0 56.592 0.192 56.616 ;
    END
  END i[325]
  PIN i[326]
    DIRECTION INPUT ;
    USE SIGNAL ;
    PORT
      LAYER M4 ;
        RECT  0 56.736 0.192 56.76 ;
    END
  END i[326]
  PIN i[327]
    DIRECTION INPUT ;
    USE SIGNAL ;
    PORT
      LAYER M4 ;
        RECT  0 56.928 0.192 56.952 ;
    END
  END i[327]
  PIN i[328]
    DIRECTION INPUT ;
    USE SIGNAL ;
    PORT
      LAYER M4 ;
        RECT  0 57.072 0.192 57.096 ;
    END
  END i[328]
  PIN i[329]
    DIRECTION INPUT ;
    USE SIGNAL ;
    PORT
      LAYER M4 ;
        RECT  0 57.216 0.192 57.24 ;
    END
  END i[329]
  PIN i[32]
    DIRECTION INPUT ;
    USE SIGNAL ;
    PORT
      LAYER M4 ;
        RECT  0 9.552 0.192 9.576 ;
    END
  END i[32]
  PIN i[330]
    DIRECTION INPUT ;
    USE SIGNAL ;
    PORT
      LAYER M4 ;
        RECT  0 57.408 0.192 57.432 ;
    END
  END i[330]
  PIN i[331]
    DIRECTION INPUT ;
    USE SIGNAL ;
    PORT
      LAYER M4 ;
        RECT  0 57.552 0.192 57.576 ;
    END
  END i[331]
  PIN i[332]
    DIRECTION INPUT ;
    USE SIGNAL ;
    PORT
      LAYER M4 ;
        RECT  0 57.744 0.192 57.768 ;
    END
  END i[332]
  PIN i[333]
    DIRECTION INPUT ;
    USE SIGNAL ;
    PORT
      LAYER M4 ;
        RECT  0 57.888 0.192 57.912 ;
    END
  END i[333]
  PIN i[334]
    DIRECTION INPUT ;
    USE SIGNAL ;
    PORT
      LAYER M4 ;
        RECT  0 58.032 0.192 58.056 ;
    END
  END i[334]
  PIN i[335]
    DIRECTION INPUT ;
    USE SIGNAL ;
    PORT
      LAYER M4 ;
        RECT  0 58.224 0.192 58.248 ;
    END
  END i[335]
  PIN i[336]
    DIRECTION INPUT ;
    USE SIGNAL ;
    PORT
      LAYER M4 ;
        RECT  0 58.368 0.192 58.392 ;
    END
  END i[336]
  PIN i[337]
    DIRECTION INPUT ;
    USE SIGNAL ;
    PORT
      LAYER M4 ;
        RECT  0 58.512 0.192 58.536 ;
    END
  END i[337]
  PIN i[338]
    DIRECTION INPUT ;
    USE SIGNAL ;
    PORT
      LAYER M4 ;
        RECT  0 58.704 0.192 58.728 ;
    END
  END i[338]
  PIN i[339]
    DIRECTION INPUT ;
    USE SIGNAL ;
    PORT
      LAYER M4 ;
        RECT  0 58.848 0.192 58.872 ;
    END
  END i[339]
  PIN i[33]
    DIRECTION INPUT ;
    USE SIGNAL ;
    PORT
      LAYER M4 ;
        RECT  0 9.696 0.192 9.72 ;
    END
  END i[33]
  PIN i[340]
    DIRECTION INPUT ;
    USE SIGNAL ;
    PORT
      LAYER M4 ;
        RECT  0 58.992 0.192 59.016 ;
    END
  END i[340]
  PIN i[341]
    DIRECTION INPUT ;
    USE SIGNAL ;
    PORT
      LAYER M4 ;
        RECT  0 59.184 0.192 59.208 ;
    END
  END i[341]
  PIN i[342]
    DIRECTION INPUT ;
    USE SIGNAL ;
    PORT
      LAYER M4 ;
        RECT  0 59.328 0.192 59.352 ;
    END
  END i[342]
  PIN i[343]
    DIRECTION INPUT ;
    USE SIGNAL ;
    PORT
      LAYER M4 ;
        RECT  0 59.472 0.192 59.496 ;
    END
  END i[343]
  PIN i[344]
    DIRECTION INPUT ;
    USE SIGNAL ;
    PORT
      LAYER M4 ;
        RECT  0 59.664 0.192 59.688 ;
    END
  END i[344]
  PIN i[345]
    DIRECTION INPUT ;
    USE SIGNAL ;
    PORT
      LAYER M4 ;
        RECT  0 59.808 0.192 59.832 ;
    END
  END i[345]
  PIN i[346]
    DIRECTION INPUT ;
    USE SIGNAL ;
    PORT
      LAYER M4 ;
        RECT  0 59.952 0.192 59.976 ;
    END
  END i[346]
  PIN i[347]
    DIRECTION INPUT ;
    USE SIGNAL ;
    PORT
      LAYER M4 ;
        RECT  0 60.144 0.192 60.168 ;
    END
  END i[347]
  PIN i[348]
    DIRECTION INPUT ;
    USE SIGNAL ;
    PORT
      LAYER M4 ;
        RECT  0 60.288 0.192 60.312 ;
    END
  END i[348]
  PIN i[349]
    DIRECTION INPUT ;
    USE SIGNAL ;
    PORT
      LAYER M4 ;
        RECT  0 60.432 0.192 60.456 ;
    END
  END i[349]
  PIN i[34]
    DIRECTION INPUT ;
    USE SIGNAL ;
    PORT
      LAYER M4 ;
        RECT  0 9.888 0.192 9.912 ;
    END
  END i[34]
  PIN i[350]
    DIRECTION INPUT ;
    USE SIGNAL ;
    PORT
      LAYER M4 ;
        RECT  0 60.624 0.192 60.648 ;
    END
  END i[350]
  PIN i[351]
    DIRECTION INPUT ;
    USE SIGNAL ;
    PORT
      LAYER M4 ;
        RECT  0 60.768 0.192 60.792 ;
    END
  END i[351]
  PIN i[352]
    DIRECTION INPUT ;
    USE SIGNAL ;
    PORT
      LAYER M4 ;
        RECT  0 60.912 0.192 60.936 ;
    END
  END i[352]
  PIN i[353]
    DIRECTION INPUT ;
    USE SIGNAL ;
    PORT
      LAYER M4 ;
        RECT  0 61.104 0.192 61.128 ;
    END
  END i[353]
  PIN i[354]
    DIRECTION INPUT ;
    USE SIGNAL ;
    PORT
      LAYER M4 ;
        RECT  0 61.248 0.192 61.272 ;
    END
  END i[354]
  PIN i[355]
    DIRECTION INPUT ;
    USE SIGNAL ;
    PORT
      LAYER M4 ;
        RECT  0 61.392 0.192 61.416 ;
    END
  END i[355]
  PIN i[356]
    DIRECTION INPUT ;
    USE SIGNAL ;
    PORT
      LAYER M4 ;
        RECT  0 61.584 0.192 61.608 ;
    END
  END i[356]
  PIN i[357]
    DIRECTION INPUT ;
    USE SIGNAL ;
    PORT
      LAYER M4 ;
        RECT  0 61.728 0.192 61.752 ;
    END
  END i[357]
  PIN i[358]
    DIRECTION INPUT ;
    USE SIGNAL ;
    PORT
      LAYER M4 ;
        RECT  0 61.872 0.192 61.896 ;
    END
  END i[358]
  PIN i[359]
    DIRECTION INPUT ;
    USE SIGNAL ;
    PORT
      LAYER M4 ;
        RECT  0 62.064 0.192 62.088 ;
    END
  END i[359]
  PIN i[35]
    DIRECTION INPUT ;
    USE SIGNAL ;
    PORT
      LAYER M4 ;
        RECT  0 10.032 0.192 10.056 ;
    END
  END i[35]
  PIN i[360]
    DIRECTION INPUT ;
    USE SIGNAL ;
    PORT
      LAYER M4 ;
        RECT  0 62.208 0.192 62.232 ;
    END
  END i[360]
  PIN i[361]
    DIRECTION INPUT ;
    USE SIGNAL ;
    PORT
      LAYER M4 ;
        RECT  0 62.4 0.192 62.424 ;
    END
  END i[361]
  PIN i[362]
    DIRECTION INPUT ;
    USE SIGNAL ;
    PORT
      LAYER M4 ;
        RECT  0 62.544 0.192 62.568 ;
    END
  END i[362]
  PIN i[363]
    DIRECTION INPUT ;
    USE SIGNAL ;
    PORT
      LAYER M4 ;
        RECT  0 62.688 0.192 62.712 ;
    END
  END i[363]
  PIN i[364]
    DIRECTION INPUT ;
    USE SIGNAL ;
    PORT
      LAYER M4 ;
        RECT  0 62.88 0.192 62.904 ;
    END
  END i[364]
  PIN i[365]
    DIRECTION INPUT ;
    USE SIGNAL ;
    PORT
      LAYER M4 ;
        RECT  0 63.024 0.192 63.048 ;
    END
  END i[365]
  PIN i[366]
    DIRECTION INPUT ;
    USE SIGNAL ;
    PORT
      LAYER M4 ;
        RECT  0 63.168 0.192 63.192 ;
    END
  END i[366]
  PIN i[367]
    DIRECTION INPUT ;
    USE SIGNAL ;
    PORT
      LAYER M4 ;
        RECT  0 63.36 0.192 63.384 ;
    END
  END i[367]
  PIN i[368]
    DIRECTION INPUT ;
    USE SIGNAL ;
    PORT
      LAYER M4 ;
        RECT  0 63.504 0.192 63.528 ;
    END
  END i[368]
  PIN i[369]
    DIRECTION INPUT ;
    USE SIGNAL ;
    PORT
      LAYER M4 ;
        RECT  0 63.648 0.192 63.672 ;
    END
  END i[369]
  PIN i[36]
    DIRECTION INPUT ;
    USE SIGNAL ;
    PORT
      LAYER M4 ;
        RECT  0 10.176 0.192 10.2 ;
    END
  END i[36]
  PIN i[370]
    DIRECTION INPUT ;
    USE SIGNAL ;
    PORT
      LAYER M4 ;
        RECT  0 63.84 0.192 63.864 ;
    END
  END i[370]
  PIN i[371]
    DIRECTION INPUT ;
    USE SIGNAL ;
    PORT
      LAYER M4 ;
        RECT  0 63.984 0.192 64.008 ;
    END
  END i[371]
  PIN i[372]
    DIRECTION INPUT ;
    USE SIGNAL ;
    PORT
      LAYER M4 ;
        RECT  0 64.128 0.192 64.152 ;
    END
  END i[372]
  PIN i[373]
    DIRECTION INPUT ;
    USE SIGNAL ;
    PORT
      LAYER M4 ;
        RECT  0 64.32 0.192 64.344 ;
    END
  END i[373]
  PIN i[374]
    DIRECTION INPUT ;
    USE SIGNAL ;
    PORT
      LAYER M4 ;
        RECT  0 64.464 0.192 64.488 ;
    END
  END i[374]
  PIN i[375]
    DIRECTION INPUT ;
    USE SIGNAL ;
    PORT
      LAYER M4 ;
        RECT  0 64.608 0.192 64.632 ;
    END
  END i[375]
  PIN i[376]
    DIRECTION INPUT ;
    USE SIGNAL ;
    PORT
      LAYER M4 ;
        RECT  0 64.8 0.192 64.824 ;
    END
  END i[376]
  PIN i[377]
    DIRECTION INPUT ;
    USE SIGNAL ;
    PORT
      LAYER M4 ;
        RECT  0 64.944 0.192 64.968 ;
    END
  END i[377]
  PIN i[378]
    DIRECTION INPUT ;
    USE SIGNAL ;
    PORT
      LAYER M4 ;
        RECT  0 65.088 0.192 65.112 ;
    END
  END i[378]
  PIN i[379]
    DIRECTION INPUT ;
    USE SIGNAL ;
    PORT
      LAYER M4 ;
        RECT  0 65.28 0.192 65.304 ;
    END
  END i[379]
  PIN i[37]
    DIRECTION INPUT ;
    USE SIGNAL ;
    PORT
      LAYER M4 ;
        RECT  0 10.368 0.192 10.392 ;
    END
  END i[37]
  PIN i[380]
    DIRECTION INPUT ;
    USE SIGNAL ;
    PORT
      LAYER M4 ;
        RECT  0 65.424 0.192 65.448 ;
    END
  END i[380]
  PIN i[381]
    DIRECTION INPUT ;
    USE SIGNAL ;
    PORT
      LAYER M4 ;
        RECT  0 65.568 0.192 65.592 ;
    END
  END i[381]
  PIN i[382]
    DIRECTION INPUT ;
    USE SIGNAL ;
    PORT
      LAYER M4 ;
        RECT  0 65.76 0.192 65.784 ;
    END
  END i[382]
  PIN i[383]
    DIRECTION INPUT ;
    USE SIGNAL ;
    PORT
      LAYER M4 ;
        RECT  0 65.904 0.192 65.928 ;
    END
  END i[383]
  PIN i[384]
    DIRECTION INPUT ;
    USE SIGNAL ;
    PORT
      LAYER M4 ;
        RECT  0 66.048 0.192 66.072 ;
    END
  END i[384]
  PIN i[385]
    DIRECTION INPUT ;
    USE SIGNAL ;
    PORT
      LAYER M4 ;
        RECT  0 66.24 0.192 66.264 ;
    END
  END i[385]
  PIN i[386]
    DIRECTION INPUT ;
    USE SIGNAL ;
    PORT
      LAYER M4 ;
        RECT  0 66.384 0.192 66.408 ;
    END
  END i[386]
  PIN i[387]
    DIRECTION INPUT ;
    USE SIGNAL ;
    PORT
      LAYER M4 ;
        RECT  0 66.528 0.192 66.552 ;
    END
  END i[387]
  PIN i[388]
    DIRECTION INPUT ;
    USE SIGNAL ;
    PORT
      LAYER M4 ;
        RECT  0 66.72 0.192 66.744 ;
    END
  END i[388]
  PIN i[389]
    DIRECTION INPUT ;
    USE SIGNAL ;
    PORT
      LAYER M4 ;
        RECT  0 66.864 0.192 66.888 ;
    END
  END i[389]
  PIN i[38]
    DIRECTION INPUT ;
    USE SIGNAL ;
    PORT
      LAYER M4 ;
        RECT  0 10.512 0.192 10.536 ;
    END
  END i[38]
  PIN i[390]
    DIRECTION INPUT ;
    USE SIGNAL ;
    PORT
      LAYER M4 ;
        RECT  0 67.056 0.192 67.08 ;
    END
  END i[390]
  PIN i[391]
    DIRECTION INPUT ;
    USE SIGNAL ;
    PORT
      LAYER M4 ;
        RECT  0 67.2 0.192 67.224 ;
    END
  END i[391]
  PIN i[392]
    DIRECTION INPUT ;
    USE SIGNAL ;
    PORT
      LAYER M4 ;
        RECT  0 67.344 0.192 67.368 ;
    END
  END i[392]
  PIN i[393]
    DIRECTION INPUT ;
    USE SIGNAL ;
    PORT
      LAYER M4 ;
        RECT  0 67.536 0.192 67.56 ;
    END
  END i[393]
  PIN i[394]
    DIRECTION INPUT ;
    USE SIGNAL ;
    PORT
      LAYER M4 ;
        RECT  0 67.68 0.192 67.704 ;
    END
  END i[394]
  PIN i[395]
    DIRECTION INPUT ;
    USE SIGNAL ;
    PORT
      LAYER M4 ;
        RECT  0 67.824 0.192 67.848 ;
    END
  END i[395]
  PIN i[396]
    DIRECTION INPUT ;
    USE SIGNAL ;
    PORT
      LAYER M4 ;
        RECT  0 68.016 0.192 68.04 ;
    END
  END i[396]
  PIN i[397]
    DIRECTION INPUT ;
    USE SIGNAL ;
    PORT
      LAYER M4 ;
        RECT  0 68.16 0.192 68.184 ;
    END
  END i[397]
  PIN i[398]
    DIRECTION INPUT ;
    USE SIGNAL ;
    PORT
      LAYER M4 ;
        RECT  0 68.304 0.192 68.328 ;
    END
  END i[398]
  PIN i[399]
    DIRECTION INPUT ;
    USE SIGNAL ;
    PORT
      LAYER M4 ;
        RECT  0 68.496 0.192 68.52 ;
    END
  END i[399]
  PIN i[39]
    DIRECTION INPUT ;
    USE SIGNAL ;
    PORT
      LAYER M4 ;
        RECT  0 10.656 0.192 10.68 ;
    END
  END i[39]
  PIN i[3]
    DIRECTION INPUT ;
    USE SIGNAL ;
    PORT
      LAYER M4 ;
        RECT  0 4.896 0.192 4.92 ;
    END
  END i[3]
  PIN i[400]
    DIRECTION INPUT ;
    USE SIGNAL ;
    PORT
      LAYER M4 ;
        RECT  0 68.64 0.192 68.664 ;
    END
  END i[400]
  PIN i[401]
    DIRECTION INPUT ;
    USE SIGNAL ;
    PORT
      LAYER M4 ;
        RECT  0 68.784 0.192 68.808 ;
    END
  END i[401]
  PIN i[402]
    DIRECTION INPUT ;
    USE SIGNAL ;
    PORT
      LAYER M4 ;
        RECT  0 68.976 0.192 69 ;
    END
  END i[402]
  PIN i[403]
    DIRECTION INPUT ;
    USE SIGNAL ;
    PORT
      LAYER M4 ;
        RECT  0 69.12 0.192 69.144 ;
    END
  END i[403]
  PIN i[404]
    DIRECTION INPUT ;
    USE SIGNAL ;
    PORT
      LAYER M4 ;
        RECT  0 69.264 0.192 69.288 ;
    END
  END i[404]
  PIN i[405]
    DIRECTION INPUT ;
    USE SIGNAL ;
    PORT
      LAYER M4 ;
        RECT  0 69.456 0.192 69.48 ;
    END
  END i[405]
  PIN i[406]
    DIRECTION INPUT ;
    USE SIGNAL ;
    PORT
      LAYER M4 ;
        RECT  0 69.6 0.192 69.624 ;
    END
  END i[406]
  PIN i[407]
    DIRECTION INPUT ;
    USE SIGNAL ;
    PORT
      LAYER M4 ;
        RECT  0 69.744 0.192 69.768 ;
    END
  END i[407]
  PIN i[408]
    DIRECTION INPUT ;
    USE SIGNAL ;
    PORT
      LAYER M4 ;
        RECT  0 69.936 0.192 69.96 ;
    END
  END i[408]
  PIN i[409]
    DIRECTION INPUT ;
    USE SIGNAL ;
    PORT
      LAYER M4 ;
        RECT  0 70.08 0.192 70.104 ;
    END
  END i[409]
  PIN i[40]
    DIRECTION INPUT ;
    USE SIGNAL ;
    PORT
      LAYER M4 ;
        RECT  0 10.848 0.192 10.872 ;
    END
  END i[40]
  PIN i[410]
    DIRECTION INPUT ;
    USE SIGNAL ;
    PORT
      LAYER M4 ;
        RECT  0 70.224 0.192 70.248 ;
    END
  END i[410]
  PIN i[411]
    DIRECTION INPUT ;
    USE SIGNAL ;
    PORT
      LAYER M4 ;
        RECT  0 70.416 0.192 70.44 ;
    END
  END i[411]
  PIN i[412]
    DIRECTION INPUT ;
    USE SIGNAL ;
    PORT
      LAYER M4 ;
        RECT  0 70.56 0.192 70.584 ;
    END
  END i[412]
  PIN i[413]
    DIRECTION INPUT ;
    USE SIGNAL ;
    PORT
      LAYER M4 ;
        RECT  0 70.704 0.192 70.728 ;
    END
  END i[413]
  PIN i[414]
    DIRECTION INPUT ;
    USE SIGNAL ;
    PORT
      LAYER M4 ;
        RECT  0 70.896 0.192 70.92 ;
    END
  END i[414]
  PIN i[415]
    DIRECTION INPUT ;
    USE SIGNAL ;
    PORT
      LAYER M4 ;
        RECT  0 71.04 0.192 71.064 ;
    END
  END i[415]
  PIN i[416]
    DIRECTION INPUT ;
    USE SIGNAL ;
    PORT
      LAYER M4 ;
        RECT  0 71.184 0.192 71.208 ;
    END
  END i[416]
  PIN i[417]
    DIRECTION INPUT ;
    USE SIGNAL ;
    PORT
      LAYER M4 ;
        RECT  0 71.376 0.192 71.4 ;
    END
  END i[417]
  PIN i[418]
    DIRECTION INPUT ;
    USE SIGNAL ;
    PORT
      LAYER M4 ;
        RECT  0 71.52 0.192 71.544 ;
    END
  END i[418]
  PIN i[419]
    DIRECTION INPUT ;
    USE SIGNAL ;
    PORT
      LAYER M4 ;
        RECT  0 71.712 0.192 71.736 ;
    END
  END i[419]
  PIN i[41]
    DIRECTION INPUT ;
    USE SIGNAL ;
    PORT
      LAYER M4 ;
        RECT  0 10.992 0.192 11.016 ;
    END
  END i[41]
  PIN i[420]
    DIRECTION INPUT ;
    USE SIGNAL ;
    PORT
      LAYER M4 ;
        RECT  0 71.856 0.192 71.88 ;
    END
  END i[420]
  PIN i[421]
    DIRECTION INPUT ;
    USE SIGNAL ;
    PORT
      LAYER M4 ;
        RECT  0 72 0.192 72.024 ;
    END
  END i[421]
  PIN i[422]
    DIRECTION INPUT ;
    USE SIGNAL ;
    PORT
      LAYER M4 ;
        RECT  0 72.192 0.192 72.216 ;
    END
  END i[422]
  PIN i[423]
    DIRECTION INPUT ;
    USE SIGNAL ;
    PORT
      LAYER M4 ;
        RECT  0 72.336 0.192 72.36 ;
    END
  END i[423]
  PIN i[424]
    DIRECTION INPUT ;
    USE SIGNAL ;
    PORT
      LAYER M4 ;
        RECT  0 72.48 0.192 72.504 ;
    END
  END i[424]
  PIN i[425]
    DIRECTION INPUT ;
    USE SIGNAL ;
    PORT
      LAYER M4 ;
        RECT  0 72.672 0.192 72.696 ;
    END
  END i[425]
  PIN i[426]
    DIRECTION INPUT ;
    USE SIGNAL ;
    PORT
      LAYER M4 ;
        RECT  0 72.816 0.192 72.84 ;
    END
  END i[426]
  PIN i[427]
    DIRECTION INPUT ;
    USE SIGNAL ;
    PORT
      LAYER M4 ;
        RECT  0 72.96 0.192 72.984 ;
    END
  END i[427]
  PIN i[428]
    DIRECTION INPUT ;
    USE SIGNAL ;
    PORT
      LAYER M4 ;
        RECT  0 73.152 0.192 73.176 ;
    END
  END i[428]
  PIN i[429]
    DIRECTION INPUT ;
    USE SIGNAL ;
    PORT
      LAYER M4 ;
        RECT  0 73.296 0.192 73.32 ;
    END
  END i[429]
  PIN i[42]
    DIRECTION INPUT ;
    USE SIGNAL ;
    PORT
      LAYER M4 ;
        RECT  0 11.136 0.192 11.16 ;
    END
  END i[42]
  PIN i[430]
    DIRECTION INPUT ;
    USE SIGNAL ;
    PORT
      LAYER M4 ;
        RECT  0 73.44 0.192 73.464 ;
    END
  END i[430]
  PIN i[431]
    DIRECTION INPUT ;
    USE SIGNAL ;
    PORT
      LAYER M4 ;
        RECT  0 73.632 0.192 73.656 ;
    END
  END i[431]
  PIN i[432]
    DIRECTION INPUT ;
    USE SIGNAL ;
    PORT
      LAYER M4 ;
        RECT  0 73.776 0.192 73.8 ;
    END
  END i[432]
  PIN i[433]
    DIRECTION INPUT ;
    USE SIGNAL ;
    PORT
      LAYER M4 ;
        RECT  0 73.92 0.192 73.944 ;
    END
  END i[433]
  PIN i[434]
    DIRECTION INPUT ;
    USE SIGNAL ;
    PORT
      LAYER M4 ;
        RECT  0 74.112 0.192 74.136 ;
    END
  END i[434]
  PIN i[435]
    DIRECTION INPUT ;
    USE SIGNAL ;
    PORT
      LAYER M4 ;
        RECT  0 74.256 0.192 74.28 ;
    END
  END i[435]
  PIN i[436]
    DIRECTION INPUT ;
    USE SIGNAL ;
    PORT
      LAYER M4 ;
        RECT  0 74.4 0.192 74.424 ;
    END
  END i[436]
  PIN i[437]
    DIRECTION INPUT ;
    USE SIGNAL ;
    PORT
      LAYER M4 ;
        RECT  0 74.592 0.192 74.616 ;
    END
  END i[437]
  PIN i[438]
    DIRECTION INPUT ;
    USE SIGNAL ;
    PORT
      LAYER M4 ;
        RECT  0 74.736 0.192 74.76 ;
    END
  END i[438]
  PIN i[439]
    DIRECTION INPUT ;
    USE SIGNAL ;
    PORT
      LAYER M4 ;
        RECT  0 74.88 0.192 74.904 ;
    END
  END i[439]
  PIN i[43]
    DIRECTION INPUT ;
    USE SIGNAL ;
    PORT
      LAYER M4 ;
        RECT  0 11.328 0.192 11.352 ;
    END
  END i[43]
  PIN i[440]
    DIRECTION INPUT ;
    USE SIGNAL ;
    PORT
      LAYER M4 ;
        RECT  0 75.072 0.192 75.096 ;
    END
  END i[440]
  PIN i[441]
    DIRECTION INPUT ;
    USE SIGNAL ;
    PORT
      LAYER M4 ;
        RECT  0 75.216 0.192 75.24 ;
    END
  END i[441]
  PIN i[442]
    DIRECTION INPUT ;
    USE SIGNAL ;
    PORT
      LAYER M4 ;
        RECT  0 75.36 0.192 75.384 ;
    END
  END i[442]
  PIN i[443]
    DIRECTION INPUT ;
    USE SIGNAL ;
    PORT
      LAYER M4 ;
        RECT  0 75.552 0.192 75.576 ;
    END
  END i[443]
  PIN i[444]
    DIRECTION INPUT ;
    USE SIGNAL ;
    PORT
      LAYER M4 ;
        RECT  0 75.696 0.192 75.72 ;
    END
  END i[444]
  PIN i[445]
    DIRECTION INPUT ;
    USE SIGNAL ;
    PORT
      LAYER M4 ;
        RECT  0 75.888 0.192 75.912 ;
    END
  END i[445]
  PIN i[446]
    DIRECTION INPUT ;
    USE SIGNAL ;
    PORT
      LAYER M4 ;
        RECT  0 76.032 0.192 76.056 ;
    END
  END i[446]
  PIN i[447]
    DIRECTION INPUT ;
    USE SIGNAL ;
    PORT
      LAYER M4 ;
        RECT  0 76.176 0.192 76.2 ;
    END
  END i[447]
  PIN i[448]
    DIRECTION INPUT ;
    USE SIGNAL ;
    PORT
      LAYER M4 ;
        RECT  0 76.368 0.192 76.392 ;
    END
  END i[448]
  PIN i[449]
    DIRECTION INPUT ;
    USE SIGNAL ;
    PORT
      LAYER M4 ;
        RECT  0 76.512 0.192 76.536 ;
    END
  END i[449]
  PIN i[44]
    DIRECTION INPUT ;
    USE SIGNAL ;
    PORT
      LAYER M4 ;
        RECT  0 11.472 0.192 11.496 ;
    END
  END i[44]
  PIN i[450]
    DIRECTION INPUT ;
    USE SIGNAL ;
    PORT
      LAYER M4 ;
        RECT  0 76.656 0.192 76.68 ;
    END
  END i[450]
  PIN i[451]
    DIRECTION INPUT ;
    USE SIGNAL ;
    PORT
      LAYER M4 ;
        RECT  0 76.848 0.192 76.872 ;
    END
  END i[451]
  PIN i[452]
    DIRECTION INPUT ;
    USE SIGNAL ;
    PORT
      LAYER M4 ;
        RECT  0 76.992 0.192 77.016 ;
    END
  END i[452]
  PIN i[453]
    DIRECTION INPUT ;
    USE SIGNAL ;
    PORT
      LAYER M4 ;
        RECT  0 77.136 0.192 77.16 ;
    END
  END i[453]
  PIN i[454]
    DIRECTION INPUT ;
    USE SIGNAL ;
    PORT
      LAYER M4 ;
        RECT  0 77.328 0.192 77.352 ;
    END
  END i[454]
  PIN i[455]
    DIRECTION INPUT ;
    USE SIGNAL ;
    PORT
      LAYER M4 ;
        RECT  0 77.472 0.192 77.496 ;
    END
  END i[455]
  PIN i[456]
    DIRECTION INPUT ;
    USE SIGNAL ;
    PORT
      LAYER M4 ;
        RECT  0 77.616 0.192 77.64 ;
    END
  END i[456]
  PIN i[457]
    DIRECTION INPUT ;
    USE SIGNAL ;
    PORT
      LAYER M4 ;
        RECT  0 77.808 0.192 77.832 ;
    END
  END i[457]
  PIN i[458]
    DIRECTION INPUT ;
    USE SIGNAL ;
    PORT
      LAYER M4 ;
        RECT  0 77.952 0.192 77.976 ;
    END
  END i[458]
  PIN i[459]
    DIRECTION INPUT ;
    USE SIGNAL ;
    PORT
      LAYER M4 ;
        RECT  0 78.096 0.192 78.12 ;
    END
  END i[459]
  PIN i[45]
    DIRECTION INPUT ;
    USE SIGNAL ;
    PORT
      LAYER M4 ;
        RECT  0 11.616 0.192 11.64 ;
    END
  END i[45]
  PIN i[460]
    DIRECTION INPUT ;
    USE SIGNAL ;
    PORT
      LAYER M4 ;
        RECT  0 78.288 0.192 78.312 ;
    END
  END i[460]
  PIN i[461]
    DIRECTION INPUT ;
    USE SIGNAL ;
    PORT
      LAYER M4 ;
        RECT  0 78.432 0.192 78.456 ;
    END
  END i[461]
  PIN i[462]
    DIRECTION INPUT ;
    USE SIGNAL ;
    PORT
      LAYER M4 ;
        RECT  0 78.576 0.192 78.6 ;
    END
  END i[462]
  PIN i[463]
    DIRECTION INPUT ;
    USE SIGNAL ;
    PORT
      LAYER M4 ;
        RECT  0 78.768 0.192 78.792 ;
    END
  END i[463]
  PIN i[464]
    DIRECTION INPUT ;
    USE SIGNAL ;
    PORT
      LAYER M4 ;
        RECT  0 78.912 0.192 78.936 ;
    END
  END i[464]
  PIN i[465]
    DIRECTION INPUT ;
    USE SIGNAL ;
    PORT
      LAYER M4 ;
        RECT  0 79.056 0.192 79.08 ;
    END
  END i[465]
  PIN i[466]
    DIRECTION INPUT ;
    USE SIGNAL ;
    PORT
      LAYER M4 ;
        RECT  0 79.248 0.192 79.272 ;
    END
  END i[466]
  PIN i[467]
    DIRECTION INPUT ;
    USE SIGNAL ;
    PORT
      LAYER M4 ;
        RECT  0 79.392 0.192 79.416 ;
    END
  END i[467]
  PIN i[468]
    DIRECTION INPUT ;
    USE SIGNAL ;
    PORT
      LAYER M4 ;
        RECT  0 79.536 0.192 79.56 ;
    END
  END i[468]
  PIN i[469]
    DIRECTION INPUT ;
    USE SIGNAL ;
    PORT
      LAYER M4 ;
        RECT  0 79.728 0.192 79.752 ;
    END
  END i[469]
  PIN i[46]
    DIRECTION INPUT ;
    USE SIGNAL ;
    PORT
      LAYER M4 ;
        RECT  0 11.808 0.192 11.832 ;
    END
  END i[46]
  PIN i[470]
    DIRECTION INPUT ;
    USE SIGNAL ;
    PORT
      LAYER M4 ;
        RECT  0 79.872 0.192 79.896 ;
    END
  END i[470]
  PIN i[471]
    DIRECTION INPUT ;
    USE SIGNAL ;
    PORT
      LAYER M4 ;
        RECT  0 80.016 0.192 80.04 ;
    END
  END i[471]
  PIN i[472]
    DIRECTION INPUT ;
    USE SIGNAL ;
    PORT
      LAYER M4 ;
        RECT  0 80.208 0.192 80.232 ;
    END
  END i[472]
  PIN i[473]
    DIRECTION INPUT ;
    USE SIGNAL ;
    PORT
      LAYER M4 ;
        RECT  0 80.352 0.192 80.376 ;
    END
  END i[473]
  PIN i[474]
    DIRECTION INPUT ;
    USE SIGNAL ;
    PORT
      LAYER M4 ;
        RECT  0 80.544 0.192 80.568 ;
    END
  END i[474]
  PIN i[475]
    DIRECTION INPUT ;
    USE SIGNAL ;
    PORT
      LAYER M4 ;
        RECT  0 80.688 0.192 80.712 ;
    END
  END i[475]
  PIN i[476]
    DIRECTION INPUT ;
    USE SIGNAL ;
    PORT
      LAYER M4 ;
        RECT  0 80.832 0.192 80.856 ;
    END
  END i[476]
  PIN i[477]
    DIRECTION INPUT ;
    USE SIGNAL ;
    PORT
      LAYER M4 ;
        RECT  0 81.024 0.192 81.048 ;
    END
  END i[477]
  PIN i[478]
    DIRECTION INPUT ;
    USE SIGNAL ;
    PORT
      LAYER M4 ;
        RECT  0 81.168 0.192 81.192 ;
    END
  END i[478]
  PIN i[479]
    DIRECTION INPUT ;
    USE SIGNAL ;
    PORT
      LAYER M4 ;
        RECT  0 81.312 0.192 81.336 ;
    END
  END i[479]
  PIN i[47]
    DIRECTION INPUT ;
    USE SIGNAL ;
    PORT
      LAYER M4 ;
        RECT  0 11.952 0.192 11.976 ;
    END
  END i[47]
  PIN i[480]
    DIRECTION INPUT ;
    USE SIGNAL ;
    PORT
      LAYER M4 ;
        RECT  0 81.504 0.192 81.528 ;
    END
  END i[480]
  PIN i[481]
    DIRECTION INPUT ;
    USE SIGNAL ;
    PORT
      LAYER M4 ;
        RECT  0 81.648 0.192 81.672 ;
    END
  END i[481]
  PIN i[482]
    DIRECTION INPUT ;
    USE SIGNAL ;
    PORT
      LAYER M4 ;
        RECT  0 81.792 0.192 81.816 ;
    END
  END i[482]
  PIN i[483]
    DIRECTION INPUT ;
    USE SIGNAL ;
    PORT
      LAYER M4 ;
        RECT  0 81.984 0.192 82.008 ;
    END
  END i[483]
  PIN i[484]
    DIRECTION INPUT ;
    USE SIGNAL ;
    PORT
      LAYER M4 ;
        RECT  0 82.128 0.192 82.152 ;
    END
  END i[484]
  PIN i[485]
    DIRECTION INPUT ;
    USE SIGNAL ;
    PORT
      LAYER M4 ;
        RECT  0 82.272 0.192 82.296 ;
    END
  END i[485]
  PIN i[486]
    DIRECTION INPUT ;
    USE SIGNAL ;
    PORT
      LAYER M4 ;
        RECT  0 82.464 0.192 82.488 ;
    END
  END i[486]
  PIN i[487]
    DIRECTION INPUT ;
    USE SIGNAL ;
    PORT
      LAYER M4 ;
        RECT  0 82.608 0.192 82.632 ;
    END
  END i[487]
  PIN i[488]
    DIRECTION INPUT ;
    USE SIGNAL ;
    PORT
      LAYER M4 ;
        RECT  0 82.752 0.192 82.776 ;
    END
  END i[488]
  PIN i[489]
    DIRECTION INPUT ;
    USE SIGNAL ;
    PORT
      LAYER M4 ;
        RECT  0 82.944 0.192 82.968 ;
    END
  END i[489]
  PIN i[48]
    DIRECTION INPUT ;
    USE SIGNAL ;
    PORT
      LAYER M4 ;
        RECT  0 12.096 0.192 12.12 ;
    END
  END i[48]
  PIN i[490]
    DIRECTION INPUT ;
    USE SIGNAL ;
    PORT
      LAYER M4 ;
        RECT  0 83.088 0.192 83.112 ;
    END
  END i[490]
  PIN i[491]
    DIRECTION INPUT ;
    USE SIGNAL ;
    PORT
      LAYER M4 ;
        RECT  0 83.232 0.192 83.256 ;
    END
  END i[491]
  PIN i[492]
    DIRECTION INPUT ;
    USE SIGNAL ;
    PORT
      LAYER M4 ;
        RECT  0 83.424 0.192 83.448 ;
    END
  END i[492]
  PIN i[493]
    DIRECTION INPUT ;
    USE SIGNAL ;
    PORT
      LAYER M4 ;
        RECT  0 83.568 0.192 83.592 ;
    END
  END i[493]
  PIN i[494]
    DIRECTION INPUT ;
    USE SIGNAL ;
    PORT
      LAYER M4 ;
        RECT  0 83.712 0.192 83.736 ;
    END
  END i[494]
  PIN i[495]
    DIRECTION INPUT ;
    USE SIGNAL ;
    PORT
      LAYER M4 ;
        RECT  0 83.904 0.192 83.928 ;
    END
  END i[495]
  PIN i[496]
    DIRECTION INPUT ;
    USE SIGNAL ;
    PORT
      LAYER M4 ;
        RECT  0 84.048 0.192 84.072 ;
    END
  END i[496]
  PIN i[497]
    DIRECTION INPUT ;
    USE SIGNAL ;
    PORT
      LAYER M4 ;
        RECT  0 84.192 0.192 84.216 ;
    END
  END i[497]
  PIN i[498]
    DIRECTION INPUT ;
    USE SIGNAL ;
    PORT
      LAYER M4 ;
        RECT  0 84.384 0.192 84.408 ;
    END
  END i[498]
  PIN i[499]
    DIRECTION INPUT ;
    USE SIGNAL ;
    PORT
      LAYER M4 ;
        RECT  0 84.528 0.192 84.552 ;
    END
  END i[499]
  PIN i[49]
    DIRECTION INPUT ;
    USE SIGNAL ;
    PORT
      LAYER M4 ;
        RECT  0 12.288 0.192 12.312 ;
    END
  END i[49]
  PIN i[4]
    DIRECTION INPUT ;
    USE SIGNAL ;
    PORT
      LAYER M4 ;
        RECT  0 5.04 0.192 5.064 ;
    END
  END i[4]
  PIN i[500]
    DIRECTION INPUT ;
    USE SIGNAL ;
    PORT
      LAYER M4 ;
        RECT  0 84.672 0.192 84.696 ;
    END
  END i[500]
  PIN i[501]
    DIRECTION INPUT ;
    USE SIGNAL ;
    PORT
      LAYER M4 ;
        RECT  0 84.864 0.192 84.888 ;
    END
  END i[501]
  PIN i[502]
    DIRECTION INPUT ;
    USE SIGNAL ;
    PORT
      LAYER M4 ;
        RECT  0 85.008 0.192 85.032 ;
    END
  END i[502]
  PIN i[503]
    DIRECTION INPUT ;
    USE SIGNAL ;
    PORT
      LAYER M4 ;
        RECT  0 85.2 0.192 85.224 ;
    END
  END i[503]
  PIN i[504]
    DIRECTION INPUT ;
    USE SIGNAL ;
    PORT
      LAYER M4 ;
        RECT  0 85.344 0.192 85.368 ;
    END
  END i[504]
  PIN i[505]
    DIRECTION INPUT ;
    USE SIGNAL ;
    PORT
      LAYER M4 ;
        RECT  0 85.488 0.192 85.512 ;
    END
  END i[505]
  PIN i[506]
    DIRECTION INPUT ;
    USE SIGNAL ;
    PORT
      LAYER M4 ;
        RECT  0 85.68 0.192 85.704 ;
    END
  END i[506]
  PIN i[507]
    DIRECTION INPUT ;
    USE SIGNAL ;
    PORT
      LAYER M4 ;
        RECT  0 85.824 0.192 85.848 ;
    END
  END i[507]
  PIN i[508]
    DIRECTION INPUT ;
    USE SIGNAL ;
    PORT
      LAYER M4 ;
        RECT  0 85.968 0.192 85.992 ;
    END
  END i[508]
  PIN i[509]
    DIRECTION INPUT ;
    USE SIGNAL ;
    PORT
      LAYER M4 ;
        RECT  0 86.16 0.192 86.184 ;
    END
  END i[509]
  PIN i[50]
    DIRECTION INPUT ;
    USE SIGNAL ;
    PORT
      LAYER M4 ;
        RECT  0 12.432 0.192 12.456 ;
    END
  END i[50]
  PIN i[510]
    DIRECTION INPUT ;
    USE SIGNAL ;
    PORT
      LAYER M4 ;
        RECT  0 86.304 0.192 86.328 ;
    END
  END i[510]
  PIN i[511]
    DIRECTION INPUT ;
    USE SIGNAL ;
    PORT
      LAYER M4 ;
        RECT  0 86.448 0.192 86.472 ;
    END
  END i[511]
  PIN i[512]
    DIRECTION INPUT ;
    USE SIGNAL ;
    PORT
      LAYER M4 ;
        RECT  0 86.64 0.192 86.664 ;
    END
  END i[512]
  PIN i[513]
    DIRECTION INPUT ;
    USE SIGNAL ;
    PORT
      LAYER M4 ;
        RECT  0 86.784 0.192 86.808 ;
    END
  END i[513]
  PIN i[514]
    DIRECTION INPUT ;
    USE SIGNAL ;
    PORT
      LAYER M4 ;
        RECT  0 86.928 0.192 86.952 ;
    END
  END i[514]
  PIN i[515]
    DIRECTION INPUT ;
    USE SIGNAL ;
    PORT
      LAYER M4 ;
        RECT  0 87.12 0.192 87.144 ;
    END
  END i[515]
  PIN i[516]
    DIRECTION INPUT ;
    USE SIGNAL ;
    PORT
      LAYER M4 ;
        RECT  0 87.264 0.192 87.288 ;
    END
  END i[516]
  PIN i[517]
    DIRECTION INPUT ;
    USE SIGNAL ;
    PORT
      LAYER M4 ;
        RECT  0 87.408 0.192 87.432 ;
    END
  END i[517]
  PIN i[518]
    DIRECTION INPUT ;
    USE SIGNAL ;
    PORT
      LAYER M4 ;
        RECT  0 87.6 0.192 87.624 ;
    END
  END i[518]
  PIN i[519]
    DIRECTION INPUT ;
    USE SIGNAL ;
    PORT
      LAYER M4 ;
        RECT  0 87.744 0.192 87.768 ;
    END
  END i[519]
  PIN i[51]
    DIRECTION INPUT ;
    USE SIGNAL ;
    PORT
      LAYER M4 ;
        RECT  0 12.624 0.192 12.648 ;
    END
  END i[51]
  PIN i[520]
    DIRECTION INPUT ;
    USE SIGNAL ;
    PORT
      LAYER M4 ;
        RECT  0 87.888 0.192 87.912 ;
    END
  END i[520]
  PIN i[521]
    DIRECTION INPUT ;
    USE SIGNAL ;
    PORT
      LAYER M4 ;
        RECT  0 88.08 0.192 88.104 ;
    END
  END i[521]
  PIN i[522]
    DIRECTION INPUT ;
    USE SIGNAL ;
    PORT
      LAYER M4 ;
        RECT  0 88.224 0.192 88.248 ;
    END
  END i[522]
  PIN i[523]
    DIRECTION INPUT ;
    USE SIGNAL ;
    PORT
      LAYER M4 ;
        RECT  0 88.368 0.192 88.392 ;
    END
  END i[523]
  PIN i[524]
    DIRECTION INPUT ;
    USE SIGNAL ;
    PORT
      LAYER M4 ;
        RECT  0 88.56 0.192 88.584 ;
    END
  END i[524]
  PIN i[525]
    DIRECTION INPUT ;
    USE SIGNAL ;
    PORT
      LAYER M4 ;
        RECT  0 88.704 0.192 88.728 ;
    END
  END i[525]
  PIN i[526]
    DIRECTION INPUT ;
    USE SIGNAL ;
    PORT
      LAYER M4 ;
        RECT  0 88.848 0.192 88.872 ;
    END
  END i[526]
  PIN i[527]
    DIRECTION INPUT ;
    USE SIGNAL ;
    PORT
      LAYER M4 ;
        RECT  0 89.04 0.192 89.064 ;
    END
  END i[527]
  PIN i[528]
    DIRECTION INPUT ;
    USE SIGNAL ;
    PORT
      LAYER M4 ;
        RECT  0 89.184 0.192 89.208 ;
    END
  END i[528]
  PIN i[529]
    DIRECTION INPUT ;
    USE SIGNAL ;
    PORT
      LAYER M4 ;
        RECT  0 89.328 0.192 89.352 ;
    END
  END i[529]
  PIN i[52]
    DIRECTION INPUT ;
    USE SIGNAL ;
    PORT
      LAYER M4 ;
        RECT  0 12.768 0.192 12.792 ;
    END
  END i[52]
  PIN i[530]
    DIRECTION INPUT ;
    USE SIGNAL ;
    PORT
      LAYER M4 ;
        RECT  0 89.52 0.192 89.544 ;
    END
  END i[530]
  PIN i[531]
    DIRECTION INPUT ;
    USE SIGNAL ;
    PORT
      LAYER M4 ;
        RECT  0 89.664 0.192 89.688 ;
    END
  END i[531]
  PIN i[532]
    DIRECTION INPUT ;
    USE SIGNAL ;
    PORT
      LAYER M4 ;
        RECT  0 89.856 0.192 89.88 ;
    END
  END i[532]
  PIN i[533]
    DIRECTION INPUT ;
    USE SIGNAL ;
    PORT
      LAYER M4 ;
        RECT  0 90 0.192 90.024 ;
    END
  END i[533]
  PIN i[534]
    DIRECTION INPUT ;
    USE SIGNAL ;
    PORT
      LAYER M4 ;
        RECT  0 90.144 0.192 90.168 ;
    END
  END i[534]
  PIN i[535]
    DIRECTION INPUT ;
    USE SIGNAL ;
    PORT
      LAYER M4 ;
        RECT  0 90.336 0.192 90.36 ;
    END
  END i[535]
  PIN i[536]
    DIRECTION INPUT ;
    USE SIGNAL ;
    PORT
      LAYER M4 ;
        RECT  0 90.48 0.192 90.504 ;
    END
  END i[536]
  PIN i[537]
    DIRECTION INPUT ;
    USE SIGNAL ;
    PORT
      LAYER M4 ;
        RECT  0 90.624 0.192 90.648 ;
    END
  END i[537]
  PIN i[538]
    DIRECTION INPUT ;
    USE SIGNAL ;
    PORT
      LAYER M4 ;
        RECT  0 90.816 0.192 90.84 ;
    END
  END i[538]
  PIN i[539]
    DIRECTION INPUT ;
    USE SIGNAL ;
    PORT
      LAYER M4 ;
        RECT  0 90.96 0.192 90.984 ;
    END
  END i[539]
  PIN i[53]
    DIRECTION INPUT ;
    USE SIGNAL ;
    PORT
      LAYER M4 ;
        RECT  0 12.912 0.192 12.936 ;
    END
  END i[53]
  PIN i[540]
    DIRECTION INPUT ;
    USE SIGNAL ;
    PORT
      LAYER M4 ;
        RECT  0 91.104 0.192 91.128 ;
    END
  END i[540]
  PIN i[541]
    DIRECTION INPUT ;
    USE SIGNAL ;
    PORT
      LAYER M4 ;
        RECT  0 91.296 0.192 91.32 ;
    END
  END i[541]
  PIN i[542]
    DIRECTION INPUT ;
    USE SIGNAL ;
    PORT
      LAYER M4 ;
        RECT  0 91.44 0.192 91.464 ;
    END
  END i[542]
  PIN i[543]
    DIRECTION INPUT ;
    USE SIGNAL ;
    PORT
      LAYER M4 ;
        RECT  0 91.584 0.192 91.608 ;
    END
  END i[543]
  PIN i[544]
    DIRECTION INPUT ;
    USE SIGNAL ;
    PORT
      LAYER M4 ;
        RECT  0 91.776 0.192 91.8 ;
    END
  END i[544]
  PIN i[545]
    DIRECTION INPUT ;
    USE SIGNAL ;
    PORT
      LAYER M4 ;
        RECT  0 91.92 0.192 91.944 ;
    END
  END i[545]
  PIN i[546]
    DIRECTION INPUT ;
    USE SIGNAL ;
    PORT
      LAYER M4 ;
        RECT  0 92.064 0.192 92.088 ;
    END
  END i[546]
  PIN i[547]
    DIRECTION INPUT ;
    USE SIGNAL ;
    PORT
      LAYER M4 ;
        RECT  0 92.256 0.192 92.28 ;
    END
  END i[547]
  PIN i[548]
    DIRECTION INPUT ;
    USE SIGNAL ;
    PORT
      LAYER M4 ;
        RECT  0 92.4 0.192 92.424 ;
    END
  END i[548]
  PIN i[549]
    DIRECTION INPUT ;
    USE SIGNAL ;
    PORT
      LAYER M4 ;
        RECT  0 92.544 0.192 92.568 ;
    END
  END i[549]
  PIN i[54]
    DIRECTION INPUT ;
    USE SIGNAL ;
    PORT
      LAYER M4 ;
        RECT  0 13.104 0.192 13.128 ;
    END
  END i[54]
  PIN i[550]
    DIRECTION INPUT ;
    USE SIGNAL ;
    PORT
      LAYER M4 ;
        RECT  0 92.736 0.192 92.76 ;
    END
  END i[550]
  PIN i[551]
    DIRECTION INPUT ;
    USE SIGNAL ;
    PORT
      LAYER M4 ;
        RECT  0 92.88 0.192 92.904 ;
    END
  END i[551]
  PIN i[552]
    DIRECTION INPUT ;
    USE SIGNAL ;
    PORT
      LAYER M4 ;
        RECT  0 93.024 0.192 93.048 ;
    END
  END i[552]
  PIN i[553]
    DIRECTION INPUT ;
    USE SIGNAL ;
    PORT
      LAYER M4 ;
        RECT  0 93.216 0.192 93.24 ;
    END
  END i[553]
  PIN i[554]
    DIRECTION INPUT ;
    USE SIGNAL ;
    PORT
      LAYER M4 ;
        RECT  0 93.36 0.192 93.384 ;
    END
  END i[554]
  PIN i[555]
    DIRECTION INPUT ;
    USE SIGNAL ;
    PORT
      LAYER M4 ;
        RECT  0 93.504 0.192 93.528 ;
    END
  END i[555]
  PIN i[556]
    DIRECTION INPUT ;
    USE SIGNAL ;
    PORT
      LAYER M4 ;
        RECT  0 93.696 0.192 93.72 ;
    END
  END i[556]
  PIN i[557]
    DIRECTION INPUT ;
    USE SIGNAL ;
    PORT
      LAYER M4 ;
        RECT  0 93.84 0.192 93.864 ;
    END
  END i[557]
  PIN i[558]
    DIRECTION INPUT ;
    USE SIGNAL ;
    PORT
      LAYER M4 ;
        RECT  0 94.032 0.192 94.056 ;
    END
  END i[558]
  PIN i[559]
    DIRECTION INPUT ;
    USE SIGNAL ;
    PORT
      LAYER M4 ;
        RECT  0 94.176 0.192 94.2 ;
    END
  END i[559]
  PIN i[55]
    DIRECTION INPUT ;
    USE SIGNAL ;
    PORT
      LAYER M4 ;
        RECT  0 13.248 0.192 13.272 ;
    END
  END i[55]
  PIN i[560]
    DIRECTION INPUT ;
    USE SIGNAL ;
    PORT
      LAYER M4 ;
        RECT  0 94.32 0.192 94.344 ;
    END
  END i[560]
  PIN i[561]
    DIRECTION INPUT ;
    USE SIGNAL ;
    PORT
      LAYER M4 ;
        RECT  0 94.512 0.192 94.536 ;
    END
  END i[561]
  PIN i[562]
    DIRECTION INPUT ;
    USE SIGNAL ;
    PORT
      LAYER M4 ;
        RECT  0 94.656 0.192 94.68 ;
    END
  END i[562]
  PIN i[563]
    DIRECTION INPUT ;
    USE SIGNAL ;
    PORT
      LAYER M4 ;
        RECT  0 94.8 0.192 94.824 ;
    END
  END i[563]
  PIN i[564]
    DIRECTION INPUT ;
    USE SIGNAL ;
    PORT
      LAYER M4 ;
        RECT  0 94.992 0.192 95.016 ;
    END
  END i[564]
  PIN i[56]
    DIRECTION INPUT ;
    USE SIGNAL ;
    PORT
      LAYER M4 ;
        RECT  0 13.392 0.192 13.416 ;
    END
  END i[56]
  PIN i[57]
    DIRECTION INPUT ;
    USE SIGNAL ;
    PORT
      LAYER M4 ;
        RECT  0 13.584 0.192 13.608 ;
    END
  END i[57]
  PIN i[58]
    DIRECTION INPUT ;
    USE SIGNAL ;
    PORT
      LAYER M4 ;
        RECT  0 13.728 0.192 13.752 ;
    END
  END i[58]
  PIN i[59]
    DIRECTION INPUT ;
    USE SIGNAL ;
    PORT
      LAYER M4 ;
        RECT  0 13.872 0.192 13.896 ;
    END
  END i[59]
  PIN i[5]
    DIRECTION INPUT ;
    USE SIGNAL ;
    PORT
      LAYER M4 ;
        RECT  0 5.232 0.192 5.256 ;
    END
  END i[5]
  PIN i[60]
    DIRECTION INPUT ;
    USE SIGNAL ;
    PORT
      LAYER M4 ;
        RECT  0 14.064 0.192 14.088 ;
    END
  END i[60]
  PIN i[61]
    DIRECTION INPUT ;
    USE SIGNAL ;
    PORT
      LAYER M4 ;
        RECT  0 14.208 0.192 14.232 ;
    END
  END i[61]
  PIN i[62]
    DIRECTION INPUT ;
    USE SIGNAL ;
    PORT
      LAYER M4 ;
        RECT  0 14.352 0.192 14.376 ;
    END
  END i[62]
  PIN i[63]
    DIRECTION INPUT ;
    USE SIGNAL ;
    PORT
      LAYER M4 ;
        RECT  0 14.544 0.192 14.568 ;
    END
  END i[63]
  PIN i[64]
    DIRECTION INPUT ;
    USE SIGNAL ;
    PORT
      LAYER M4 ;
        RECT  0 14.688 0.192 14.712 ;
    END
  END i[64]
  PIN i[65]
    DIRECTION INPUT ;
    USE SIGNAL ;
    PORT
      LAYER M4 ;
        RECT  0 14.832 0.192 14.856 ;
    END
  END i[65]
  PIN i[66]
    DIRECTION INPUT ;
    USE SIGNAL ;
    PORT
      LAYER M4 ;
        RECT  0 15.024 0.192 15.048 ;
    END
  END i[66]
  PIN i[67]
    DIRECTION INPUT ;
    USE SIGNAL ;
    PORT
      LAYER M4 ;
        RECT  0 15.168 0.192 15.192 ;
    END
  END i[67]
  PIN i[68]
    DIRECTION INPUT ;
    USE SIGNAL ;
    PORT
      LAYER M4 ;
        RECT  0 15.312 0.192 15.336 ;
    END
  END i[68]
  PIN i[69]
    DIRECTION INPUT ;
    USE SIGNAL ;
    PORT
      LAYER M4 ;
        RECT  0 15.504 0.192 15.528 ;
    END
  END i[69]
  PIN i[6]
    DIRECTION INPUT ;
    USE SIGNAL ;
    PORT
      LAYER M4 ;
        RECT  0 5.376 0.192 5.4 ;
    END
  END i[6]
  PIN i[70]
    DIRECTION INPUT ;
    USE SIGNAL ;
    PORT
      LAYER M4 ;
        RECT  0 15.648 0.192 15.672 ;
    END
  END i[70]
  PIN i[71]
    DIRECTION INPUT ;
    USE SIGNAL ;
    PORT
      LAYER M4 ;
        RECT  0 15.792 0.192 15.816 ;
    END
  END i[71]
  PIN i[72]
    DIRECTION INPUT ;
    USE SIGNAL ;
    PORT
      LAYER M4 ;
        RECT  0 15.984 0.192 16.008 ;
    END
  END i[72]
  PIN i[73]
    DIRECTION INPUT ;
    USE SIGNAL ;
    PORT
      LAYER M4 ;
        RECT  0 16.128 0.192 16.152 ;
    END
  END i[73]
  PIN i[74]
    DIRECTION INPUT ;
    USE SIGNAL ;
    PORT
      LAYER M4 ;
        RECT  0 16.272 0.192 16.296 ;
    END
  END i[74]
  PIN i[75]
    DIRECTION INPUT ;
    USE SIGNAL ;
    PORT
      LAYER M4 ;
        RECT  0 16.464 0.192 16.488 ;
    END
  END i[75]
  PIN i[76]
    DIRECTION INPUT ;
    USE SIGNAL ;
    PORT
      LAYER M4 ;
        RECT  0 16.608 0.192 16.632 ;
    END
  END i[76]
  PIN i[77]
    DIRECTION INPUT ;
    USE SIGNAL ;
    PORT
      LAYER M4 ;
        RECT  0 16.752 0.192 16.776 ;
    END
  END i[77]
  PIN i[78]
    DIRECTION INPUT ;
    USE SIGNAL ;
    PORT
      LAYER M4 ;
        RECT  0 16.944 0.192 16.968 ;
    END
  END i[78]
  PIN i[79]
    DIRECTION INPUT ;
    USE SIGNAL ;
    PORT
      LAYER M4 ;
        RECT  0 17.088 0.192 17.112 ;
    END
  END i[79]
  PIN i[7]
    DIRECTION INPUT ;
    USE SIGNAL ;
    PORT
      LAYER M4 ;
        RECT  0 5.52 0.192 5.544 ;
    END
  END i[7]
  PIN i[80]
    DIRECTION INPUT ;
    USE SIGNAL ;
    PORT
      LAYER M4 ;
        RECT  0 17.28 0.192 17.304 ;
    END
  END i[80]
  PIN i[81]
    DIRECTION INPUT ;
    USE SIGNAL ;
    PORT
      LAYER M4 ;
        RECT  0 17.424 0.192 17.448 ;
    END
  END i[81]
  PIN i[82]
    DIRECTION INPUT ;
    USE SIGNAL ;
    PORT
      LAYER M4 ;
        RECT  0 17.568 0.192 17.592 ;
    END
  END i[82]
  PIN i[83]
    DIRECTION INPUT ;
    USE SIGNAL ;
    PORT
      LAYER M4 ;
        RECT  0 17.76 0.192 17.784 ;
    END
  END i[83]
  PIN i[84]
    DIRECTION INPUT ;
    USE SIGNAL ;
    PORT
      LAYER M4 ;
        RECT  0 17.904 0.192 17.928 ;
    END
  END i[84]
  PIN i[85]
    DIRECTION INPUT ;
    USE SIGNAL ;
    PORT
      LAYER M4 ;
        RECT  0 18.048 0.192 18.072 ;
    END
  END i[85]
  PIN i[86]
    DIRECTION INPUT ;
    USE SIGNAL ;
    PORT
      LAYER M4 ;
        RECT  0 18.24 0.192 18.264 ;
    END
  END i[86]
  PIN i[87]
    DIRECTION INPUT ;
    USE SIGNAL ;
    PORT
      LAYER M4 ;
        RECT  0 18.384 0.192 18.408 ;
    END
  END i[87]
  PIN i[88]
    DIRECTION INPUT ;
    USE SIGNAL ;
    PORT
      LAYER M4 ;
        RECT  0 18.528 0.192 18.552 ;
    END
  END i[88]
  PIN i[89]
    DIRECTION INPUT ;
    USE SIGNAL ;
    PORT
      LAYER M4 ;
        RECT  0 18.72 0.192 18.744 ;
    END
  END i[89]
  PIN i[8]
    DIRECTION INPUT ;
    USE SIGNAL ;
    PORT
      LAYER M4 ;
        RECT  0 5.712 0.192 5.736 ;
    END
  END i[8]
  PIN i[90]
    DIRECTION INPUT ;
    USE SIGNAL ;
    PORT
      LAYER M4 ;
        RECT  0 18.864 0.192 18.888 ;
    END
  END i[90]
  PIN i[91]
    DIRECTION INPUT ;
    USE SIGNAL ;
    PORT
      LAYER M4 ;
        RECT  0 19.008 0.192 19.032 ;
    END
  END i[91]
  PIN i[92]
    DIRECTION INPUT ;
    USE SIGNAL ;
    PORT
      LAYER M4 ;
        RECT  0 19.2 0.192 19.224 ;
    END
  END i[92]
  PIN i[93]
    DIRECTION INPUT ;
    USE SIGNAL ;
    PORT
      LAYER M4 ;
        RECT  0 19.344 0.192 19.368 ;
    END
  END i[93]
  PIN i[94]
    DIRECTION INPUT ;
    USE SIGNAL ;
    PORT
      LAYER M4 ;
        RECT  0 19.488 0.192 19.512 ;
    END
  END i[94]
  PIN i[95]
    DIRECTION INPUT ;
    USE SIGNAL ;
    PORT
      LAYER M4 ;
        RECT  0 19.68 0.192 19.704 ;
    END
  END i[95]
  PIN i[96]
    DIRECTION INPUT ;
    USE SIGNAL ;
    PORT
      LAYER M4 ;
        RECT  0 19.824 0.192 19.848 ;
    END
  END i[96]
  PIN i[97]
    DIRECTION INPUT ;
    USE SIGNAL ;
    PORT
      LAYER M4 ;
        RECT  0 19.968 0.192 19.992 ;
    END
  END i[97]
  PIN i[98]
    DIRECTION INPUT ;
    USE SIGNAL ;
    PORT
      LAYER M4 ;
        RECT  0 20.16 0.192 20.184 ;
    END
  END i[98]
  PIN i[99]
    DIRECTION INPUT ;
    USE SIGNAL ;
    PORT
      LAYER M4 ;
        RECT  0 20.304 0.192 20.328 ;
    END
  END i[99]
  PIN i[9]
    DIRECTION INPUT ;
    USE SIGNAL ;
    PORT
      LAYER M4 ;
        RECT  0 5.856 0.192 5.88 ;
    END
  END i[9]
  PIN od[0]
    DIRECTION OUTPUT ;
    USE SIGNAL ;
    PORT
      LAYER M5 ;
        RECT  4.752 0 4.776 0.192 ;
    END
  END od[0]
  PIN od[100]
    DIRECTION OUTPUT ;
    USE SIGNAL ;
    PORT
      LAYER M5 ;
        RECT  16.848 0 16.872 0.192 ;
    END
  END od[100]
  PIN od[101]
    DIRECTION OUTPUT ;
    USE SIGNAL ;
    PORT
      LAYER M3 ;
        RECT  16.956 0 16.974 0.144 ;
    END
  END od[101]
  PIN od[102]
    DIRECTION OUTPUT ;
    USE SIGNAL ;
    PORT
      LAYER M5 ;
        RECT  17.088 0 17.112 0.192 ;
    END
  END od[102]
  PIN od[103]
    DIRECTION OUTPUT ;
    USE SIGNAL ;
    PORT
      LAYER M3 ;
        RECT  17.208 0 17.226 0.144 ;
    END
  END od[103]
  PIN od[104]
    DIRECTION OUTPUT ;
    USE SIGNAL ;
    PORT
      LAYER M5 ;
        RECT  17.328 0 17.352 0.192 ;
    END
  END od[104]
  PIN od[105]
    DIRECTION OUTPUT ;
    USE SIGNAL ;
    PORT
      LAYER M3 ;
        RECT  17.46 0 17.478 0.144 ;
    END
  END od[105]
  PIN od[106]
    DIRECTION OUTPUT ;
    USE SIGNAL ;
    PORT
      LAYER M5 ;
        RECT  17.568 0 17.592 0.192 ;
    END
  END od[106]
  PIN od[107]
    DIRECTION OUTPUT ;
    USE SIGNAL ;
    PORT
      LAYER M3 ;
        RECT  17.676 0 17.694 0.144 ;
    END
  END od[107]
  PIN od[108]
    DIRECTION OUTPUT ;
    USE SIGNAL ;
    PORT
      LAYER M5 ;
        RECT  17.808 0 17.832 0.192 ;
    END
  END od[108]
  PIN od[109]
    DIRECTION OUTPUT ;
    USE SIGNAL ;
    PORT
      LAYER M3 ;
        RECT  17.928 0 17.946 0.144 ;
    END
  END od[109]
  PIN od[10]
    DIRECTION OUTPUT ;
    USE SIGNAL ;
    PORT
      LAYER M5 ;
        RECT  5.952 0 5.976 0.192 ;
    END
  END od[10]
  PIN od[110]
    DIRECTION OUTPUT ;
    USE SIGNAL ;
    PORT
      LAYER M5 ;
        RECT  18.048 0 18.072 0.192 ;
    END
  END od[110]
  PIN od[111]
    DIRECTION OUTPUT ;
    USE SIGNAL ;
    PORT
      LAYER M3 ;
        RECT  18.18 0 18.198 0.144 ;
    END
  END od[111]
  PIN od[112]
    DIRECTION OUTPUT ;
    USE SIGNAL ;
    PORT
      LAYER M5 ;
        RECT  18.288 0 18.312 0.192 ;
    END
  END od[112]
  PIN od[113]
    DIRECTION OUTPUT ;
    USE SIGNAL ;
    PORT
      LAYER M3 ;
        RECT  18.396 0 18.414 0.144 ;
    END
  END od[113]
  PIN od[114]
    DIRECTION OUTPUT ;
    USE SIGNAL ;
    PORT
      LAYER M5 ;
        RECT  18.528 0 18.552 0.192 ;
    END
  END od[114]
  PIN od[115]
    DIRECTION OUTPUT ;
    USE SIGNAL ;
    PORT
      LAYER M3 ;
        RECT  18.648 0 18.666 0.144 ;
    END
  END od[115]
  PIN od[116]
    DIRECTION OUTPUT ;
    USE SIGNAL ;
    PORT
      LAYER M5 ;
        RECT  18.768 0 18.792 0.192 ;
    END
  END od[116]
  PIN od[117]
    DIRECTION OUTPUT ;
    USE SIGNAL ;
    PORT
      LAYER M3 ;
        RECT  18.9 0 18.918 0.144 ;
    END
  END od[117]
  PIN od[118]
    DIRECTION OUTPUT ;
    USE SIGNAL ;
    PORT
      LAYER M5 ;
        RECT  19.008 0 19.032 0.192 ;
    END
  END od[118]
  PIN od[119]
    DIRECTION OUTPUT ;
    USE SIGNAL ;
    PORT
      LAYER M3 ;
        RECT  19.152 0 19.17 0.144 ;
    END
  END od[119]
  PIN od[11]
    DIRECTION OUTPUT ;
    USE SIGNAL ;
    PORT
      LAYER M3 ;
        RECT  6.084 0 6.102 0.144 ;
    END
  END od[11]
  PIN od[120]
    DIRECTION OUTPUT ;
    USE SIGNAL ;
    PORT
      LAYER M5 ;
        RECT  19.248 0 19.272 0.192 ;
    END
  END od[120]
  PIN od[121]
    DIRECTION OUTPUT ;
    USE SIGNAL ;
    PORT
      LAYER M3 ;
        RECT  19.368 0 19.386 0.144 ;
    END
  END od[121]
  PIN od[122]
    DIRECTION OUTPUT ;
    USE SIGNAL ;
    PORT
      LAYER M5 ;
        RECT  19.488 0 19.512 0.192 ;
    END
  END od[122]
  PIN od[123]
    DIRECTION OUTPUT ;
    USE SIGNAL ;
    PORT
      LAYER M3 ;
        RECT  19.62 0 19.638 0.144 ;
    END
  END od[123]
  PIN od[124]
    DIRECTION OUTPUT ;
    USE SIGNAL ;
    PORT
      LAYER M5 ;
        RECT  19.728 0 19.752 0.192 ;
    END
  END od[124]
  PIN od[125]
    DIRECTION OUTPUT ;
    USE SIGNAL ;
    PORT
      LAYER M3 ;
        RECT  19.872 0 19.89 0.144 ;
    END
  END od[125]
  PIN od[126]
    DIRECTION OUTPUT ;
    USE SIGNAL ;
    PORT
      LAYER M5 ;
        RECT  19.968 0 19.992 0.192 ;
    END
  END od[126]
  PIN od[127]
    DIRECTION OUTPUT ;
    USE SIGNAL ;
    PORT
      LAYER M3 ;
        RECT  20.124 0 20.142 0.144 ;
    END
  END od[127]
  PIN od[128]
    DIRECTION OUTPUT ;
    USE SIGNAL ;
    PORT
      LAYER M5 ;
        RECT  20.208 0 20.232 0.192 ;
    END
  END od[128]
  PIN od[129]
    DIRECTION OUTPUT ;
    USE SIGNAL ;
    PORT
      LAYER M3 ;
        RECT  20.34 0 20.358 0.144 ;
    END
  END od[129]
  PIN od[12]
    DIRECTION OUTPUT ;
    USE SIGNAL ;
    PORT
      LAYER M5 ;
        RECT  6.192 0 6.216 0.192 ;
    END
  END od[12]
  PIN od[130]
    DIRECTION OUTPUT ;
    USE SIGNAL ;
    PORT
      LAYER M5 ;
        RECT  20.448 0 20.472 0.192 ;
    END
  END od[130]
  PIN od[131]
    DIRECTION OUTPUT ;
    USE SIGNAL ;
    PORT
      LAYER M3 ;
        RECT  20.592 0 20.61 0.144 ;
    END
  END od[131]
  PIN od[132]
    DIRECTION OUTPUT ;
    USE SIGNAL ;
    PORT
      LAYER M5 ;
        RECT  20.688 0 20.712 0.192 ;
    END
  END od[132]
  PIN od[133]
    DIRECTION OUTPUT ;
    USE SIGNAL ;
    PORT
      LAYER M3 ;
        RECT  20.844 0 20.862 0.144 ;
    END
  END od[133]
  PIN od[134]
    DIRECTION OUTPUT ;
    USE SIGNAL ;
    PORT
      LAYER M5 ;
        RECT  20.976 0 21 0.192 ;
    END
  END od[134]
  PIN od[135]
    DIRECTION OUTPUT ;
    USE SIGNAL ;
    PORT
      LAYER M3 ;
        RECT  21.06 0 21.078 0.144 ;
    END
  END od[135]
  PIN od[136]
    DIRECTION OUTPUT ;
    USE SIGNAL ;
    PORT
      LAYER M5 ;
        RECT  21.216 0 21.24 0.192 ;
    END
  END od[136]
  PIN od[137]
    DIRECTION OUTPUT ;
    USE SIGNAL ;
    PORT
      LAYER M3 ;
        RECT  21.312 0 21.33 0.144 ;
    END
  END od[137]
  PIN od[138]
    DIRECTION OUTPUT ;
    USE SIGNAL ;
    PORT
      LAYER M5 ;
        RECT  21.456 0 21.48 0.192 ;
    END
  END od[138]
  PIN od[139]
    DIRECTION OUTPUT ;
    USE SIGNAL ;
    PORT
      LAYER M3 ;
        RECT  21.564 0 21.582 0.144 ;
    END
  END od[139]
  PIN od[13]
    DIRECTION OUTPUT ;
    USE SIGNAL ;
    PORT
      LAYER M3 ;
        RECT  6.3 0 6.318 0.144 ;
    END
  END od[13]
  PIN od[140]
    DIRECTION OUTPUT ;
    USE SIGNAL ;
    PORT
      LAYER M5 ;
        RECT  21.696 0 21.72 0.192 ;
    END
  END od[140]
  PIN od[141]
    DIRECTION OUTPUT ;
    USE SIGNAL ;
    PORT
      LAYER M3 ;
        RECT  21.816 0 21.834 0.144 ;
    END
  END od[141]
  PIN od[142]
    DIRECTION OUTPUT ;
    USE SIGNAL ;
    PORT
      LAYER M5 ;
        RECT  21.936 0 21.96 0.192 ;
    END
  END od[142]
  PIN od[143]
    DIRECTION OUTPUT ;
    USE SIGNAL ;
    PORT
      LAYER M3 ;
        RECT  22.032 0 22.05 0.144 ;
    END
  END od[143]
  PIN od[144]
    DIRECTION OUTPUT ;
    USE SIGNAL ;
    PORT
      LAYER M5 ;
        RECT  22.176 0 22.2 0.192 ;
    END
  END od[144]
  PIN od[145]
    DIRECTION OUTPUT ;
    USE SIGNAL ;
    PORT
      LAYER M3 ;
        RECT  22.284 0 22.302 0.144 ;
    END
  END od[145]
  PIN od[146]
    DIRECTION OUTPUT ;
    USE SIGNAL ;
    PORT
      LAYER M5 ;
        RECT  22.416 0 22.44 0.192 ;
    END
  END od[146]
  PIN od[147]
    DIRECTION OUTPUT ;
    USE SIGNAL ;
    PORT
      LAYER M3 ;
        RECT  22.536 0 22.554 0.144 ;
    END
  END od[147]
  PIN od[148]
    DIRECTION OUTPUT ;
    USE SIGNAL ;
    PORT
      LAYER M5 ;
        RECT  22.656 0 22.68 0.192 ;
    END
  END od[148]
  PIN od[149]
    DIRECTION OUTPUT ;
    USE SIGNAL ;
    PORT
      LAYER M3 ;
        RECT  22.788 0 22.806 0.144 ;
    END
  END od[149]
  PIN od[14]
    DIRECTION OUTPUT ;
    USE SIGNAL ;
    PORT
      LAYER M5 ;
        RECT  6.432 0 6.456 0.192 ;
    END
  END od[14]
  PIN od[150]
    DIRECTION OUTPUT ;
    USE SIGNAL ;
    PORT
      LAYER M5 ;
        RECT  22.896 0 22.92 0.192 ;
    END
  END od[150]
  PIN od[151]
    DIRECTION OUTPUT ;
    USE SIGNAL ;
    PORT
      LAYER M3 ;
        RECT  23.004 0 23.022 0.144 ;
    END
  END od[151]
  PIN od[152]
    DIRECTION OUTPUT ;
    USE SIGNAL ;
    PORT
      LAYER M5 ;
        RECT  23.136 0 23.16 0.192 ;
    END
  END od[152]
  PIN od[153]
    DIRECTION OUTPUT ;
    USE SIGNAL ;
    PORT
      LAYER M3 ;
        RECT  23.256 0 23.274 0.144 ;
    END
  END od[153]
  PIN od[154]
    DIRECTION OUTPUT ;
    USE SIGNAL ;
    PORT
      LAYER M5 ;
        RECT  23.376 0 23.4 0.192 ;
    END
  END od[154]
  PIN od[155]
    DIRECTION OUTPUT ;
    USE SIGNAL ;
    PORT
      LAYER M3 ;
        RECT  23.508 0 23.526 0.144 ;
    END
  END od[155]
  PIN od[156]
    DIRECTION OUTPUT ;
    USE SIGNAL ;
    PORT
      LAYER M5 ;
        RECT  23.616 0 23.64 0.192 ;
    END
  END od[156]
  PIN od[157]
    DIRECTION OUTPUT ;
    USE SIGNAL ;
    PORT
      LAYER M3 ;
        RECT  23.724 0 23.742 0.144 ;
    END
  END od[157]
  PIN od[158]
    DIRECTION OUTPUT ;
    USE SIGNAL ;
    PORT
      LAYER M5 ;
        RECT  23.856 0 23.88 0.192 ;
    END
  END od[158]
  PIN od[159]
    DIRECTION OUTPUT ;
    USE SIGNAL ;
    PORT
      LAYER M3 ;
        RECT  23.976 0 23.994 0.144 ;
    END
  END od[159]
  PIN od[15]
    DIRECTION OUTPUT ;
    USE SIGNAL ;
    PORT
      LAYER M3 ;
        RECT  6.552 0 6.57 0.144 ;
    END
  END od[15]
  PIN od[160]
    DIRECTION OUTPUT ;
    USE SIGNAL ;
    PORT
      LAYER M5 ;
        RECT  24.096 0 24.12 0.192 ;
    END
  END od[160]
  PIN od[161]
    DIRECTION OUTPUT ;
    USE SIGNAL ;
    PORT
      LAYER M3 ;
        RECT  24.228 0 24.246 0.144 ;
    END
  END od[161]
  PIN od[162]
    DIRECTION OUTPUT ;
    USE SIGNAL ;
    PORT
      LAYER M5 ;
        RECT  24.336 0 24.36 0.192 ;
    END
  END od[162]
  PIN od[163]
    DIRECTION OUTPUT ;
    USE SIGNAL ;
    PORT
      LAYER M3 ;
        RECT  24.48 0 24.498 0.144 ;
    END
  END od[163]
  PIN od[164]
    DIRECTION OUTPUT ;
    USE SIGNAL ;
    PORT
      LAYER M5 ;
        RECT  24.576 0 24.6 0.192 ;
    END
  END od[164]
  PIN od[165]
    DIRECTION OUTPUT ;
    USE SIGNAL ;
    PORT
      LAYER M3 ;
        RECT  24.696 0 24.714 0.144 ;
    END
  END od[165]
  PIN od[166]
    DIRECTION OUTPUT ;
    USE SIGNAL ;
    PORT
      LAYER M5 ;
        RECT  24.816 0 24.84 0.192 ;
    END
  END od[166]
  PIN od[167]
    DIRECTION OUTPUT ;
    USE SIGNAL ;
    PORT
      LAYER M3 ;
        RECT  24.948 0 24.966 0.144 ;
    END
  END od[167]
  PIN od[168]
    DIRECTION OUTPUT ;
    USE SIGNAL ;
    PORT
      LAYER M5 ;
        RECT  25.056 0 25.08 0.192 ;
    END
  END od[168]
  PIN od[169]
    DIRECTION OUTPUT ;
    USE SIGNAL ;
    PORT
      LAYER M3 ;
        RECT  25.2 0 25.218 0.144 ;
    END
  END od[169]
  PIN od[16]
    DIRECTION OUTPUT ;
    USE SIGNAL ;
    PORT
      LAYER M5 ;
        RECT  6.672 0 6.696 0.192 ;
    END
  END od[16]
  PIN od[170]
    DIRECTION OUTPUT ;
    USE SIGNAL ;
    PORT
      LAYER M5 ;
        RECT  25.296 0 25.32 0.192 ;
    END
  END od[170]
  PIN od[171]
    DIRECTION OUTPUT ;
    USE SIGNAL ;
    PORT
      LAYER M3 ;
        RECT  25.452 0 25.47 0.144 ;
    END
  END od[171]
  PIN od[172]
    DIRECTION OUTPUT ;
    USE SIGNAL ;
    PORT
      LAYER M5 ;
        RECT  25.536 0 25.56 0.192 ;
    END
  END od[172]
  PIN od[173]
    DIRECTION OUTPUT ;
    USE SIGNAL ;
    PORT
      LAYER M3 ;
        RECT  25.668 0 25.686 0.144 ;
    END
  END od[173]
  PIN od[174]
    DIRECTION OUTPUT ;
    USE SIGNAL ;
    PORT
      LAYER M5 ;
        RECT  25.776 0 25.8 0.192 ;
    END
  END od[174]
  PIN od[175]
    DIRECTION OUTPUT ;
    USE SIGNAL ;
    PORT
      LAYER M3 ;
        RECT  25.92 0 25.938 0.144 ;
    END
  END od[175]
  PIN od[176]
    DIRECTION OUTPUT ;
    USE SIGNAL ;
    PORT
      LAYER M5 ;
        RECT  26.016 0 26.04 0.192 ;
    END
  END od[176]
  PIN od[177]
    DIRECTION OUTPUT ;
    USE SIGNAL ;
    PORT
      LAYER M3 ;
        RECT  26.172 0 26.19 0.144 ;
    END
  END od[177]
  PIN od[178]
    DIRECTION OUTPUT ;
    USE SIGNAL ;
    PORT
      LAYER M5 ;
        RECT  26.256 0 26.28 0.192 ;
    END
  END od[178]
  PIN od[179]
    DIRECTION OUTPUT ;
    USE SIGNAL ;
    PORT
      LAYER M3 ;
        RECT  26.388 0 26.406 0.144 ;
    END
  END od[179]
  PIN od[17]
    DIRECTION OUTPUT ;
    USE SIGNAL ;
    PORT
      LAYER M3 ;
        RECT  6.804 0 6.822 0.144 ;
    END
  END od[17]
  PIN od[180]
    DIRECTION OUTPUT ;
    USE SIGNAL ;
    PORT
      LAYER M5 ;
        RECT  26.544 0 26.568 0.192 ;
    END
  END od[180]
  PIN od[181]
    DIRECTION OUTPUT ;
    USE SIGNAL ;
    PORT
      LAYER M3 ;
        RECT  26.64 0 26.658 0.144 ;
    END
  END od[181]
  PIN od[182]
    DIRECTION OUTPUT ;
    USE SIGNAL ;
    PORT
      LAYER M5 ;
        RECT  26.784 0 26.808 0.192 ;
    END
  END od[182]
  PIN od[183]
    DIRECTION OUTPUT ;
    USE SIGNAL ;
    PORT
      LAYER M3 ;
        RECT  26.892 0 26.91 0.144 ;
    END
  END od[183]
  PIN od[184]
    DIRECTION OUTPUT ;
    USE SIGNAL ;
    PORT
      LAYER M5 ;
        RECT  27.024 0 27.048 0.192 ;
    END
  END od[184]
  PIN od[185]
    DIRECTION OUTPUT ;
    USE SIGNAL ;
    PORT
      LAYER M3 ;
        RECT  27.144 0 27.162 0.144 ;
    END
  END od[185]
  PIN od[186]
    DIRECTION OUTPUT ;
    USE SIGNAL ;
    PORT
      LAYER M5 ;
        RECT  27.264 0 27.288 0.192 ;
    END
  END od[186]
  PIN od[187]
    DIRECTION OUTPUT ;
    USE SIGNAL ;
    PORT
      LAYER M3 ;
        RECT  27.36 0 27.378 0.144 ;
    END
  END od[187]
  PIN od[188]
    DIRECTION OUTPUT ;
    USE SIGNAL ;
    PORT
      LAYER M5 ;
        RECT  27.504 0 27.528 0.192 ;
    END
  END od[188]
  PIN od[189]
    DIRECTION OUTPUT ;
    USE SIGNAL ;
    PORT
      LAYER M3 ;
        RECT  27.612 0 27.63 0.144 ;
    END
  END od[189]
  PIN od[18]
    DIRECTION OUTPUT ;
    USE SIGNAL ;
    PORT
      LAYER M5 ;
        RECT  6.912 0 6.936 0.192 ;
    END
  END od[18]
  PIN od[190]
    DIRECTION OUTPUT ;
    USE SIGNAL ;
    PORT
      LAYER M5 ;
        RECT  27.744 0 27.768 0.192 ;
    END
  END od[190]
  PIN od[191]
    DIRECTION OUTPUT ;
    USE SIGNAL ;
    PORT
      LAYER M3 ;
        RECT  27.864 0 27.882 0.144 ;
    END
  END od[191]
  PIN od[192]
    DIRECTION OUTPUT ;
    USE SIGNAL ;
    PORT
      LAYER M5 ;
        RECT  27.984 0 28.008 0.192 ;
    END
  END od[192]
  PIN od[193]
    DIRECTION OUTPUT ;
    USE SIGNAL ;
    PORT
      LAYER M3 ;
        RECT  28.08 0 28.098 0.144 ;
    END
  END od[193]
  PIN od[194]
    DIRECTION OUTPUT ;
    USE SIGNAL ;
    PORT
      LAYER M5 ;
        RECT  28.224 0 28.248 0.192 ;
    END
  END od[194]
  PIN od[195]
    DIRECTION OUTPUT ;
    USE SIGNAL ;
    PORT
      LAYER M3 ;
        RECT  28.332 0 28.35 0.144 ;
    END
  END od[195]
  PIN od[196]
    DIRECTION OUTPUT ;
    USE SIGNAL ;
    PORT
      LAYER M5 ;
        RECT  28.464 0 28.488 0.192 ;
    END
  END od[196]
  PIN od[197]
    DIRECTION OUTPUT ;
    USE SIGNAL ;
    PORT
      LAYER M3 ;
        RECT  28.584 0 28.602 0.144 ;
    END
  END od[197]
  PIN od[198]
    DIRECTION OUTPUT ;
    USE SIGNAL ;
    PORT
      LAYER M5 ;
        RECT  28.704 0 28.728 0.192 ;
    END
  END od[198]
  PIN od[199]
    DIRECTION OUTPUT ;
    USE SIGNAL ;
    PORT
      LAYER M3 ;
        RECT  28.836 0 28.854 0.144 ;
    END
  END od[199]
  PIN od[19]
    DIRECTION OUTPUT ;
    USE SIGNAL ;
    PORT
      LAYER M3 ;
        RECT  7.02 0 7.038 0.144 ;
    END
  END od[19]
  PIN od[1]
    DIRECTION OUTPUT ;
    USE SIGNAL ;
    PORT
      LAYER M3 ;
        RECT  4.86 0 4.878 0.144 ;
    END
  END od[1]
  PIN od[200]
    DIRECTION OUTPUT ;
    USE SIGNAL ;
    PORT
      LAYER M5 ;
        RECT  28.944 0 28.968 0.192 ;
    END
  END od[200]
  PIN od[201]
    DIRECTION OUTPUT ;
    USE SIGNAL ;
    PORT
      LAYER M3 ;
        RECT  29.052 0 29.07 0.144 ;
    END
  END od[201]
  PIN od[202]
    DIRECTION OUTPUT ;
    USE SIGNAL ;
    PORT
      LAYER M5 ;
        RECT  29.184 0 29.208 0.192 ;
    END
  END od[202]
  PIN od[203]
    DIRECTION OUTPUT ;
    USE SIGNAL ;
    PORT
      LAYER M3 ;
        RECT  29.304 0 29.322 0.144 ;
    END
  END od[203]
  PIN od[204]
    DIRECTION OUTPUT ;
    USE SIGNAL ;
    PORT
      LAYER M5 ;
        RECT  29.424 0 29.448 0.192 ;
    END
  END od[204]
  PIN od[205]
    DIRECTION OUTPUT ;
    USE SIGNAL ;
    PORT
      LAYER M3 ;
        RECT  29.556 0 29.574 0.144 ;
    END
  END od[205]
  PIN od[206]
    DIRECTION OUTPUT ;
    USE SIGNAL ;
    PORT
      LAYER M5 ;
        RECT  29.664 0 29.688 0.192 ;
    END
  END od[206]
  PIN od[207]
    DIRECTION OUTPUT ;
    USE SIGNAL ;
    PORT
      LAYER M3 ;
        RECT  29.808 0 29.826 0.144 ;
    END
  END od[207]
  PIN od[208]
    DIRECTION OUTPUT ;
    USE SIGNAL ;
    PORT
      LAYER M5 ;
        RECT  29.904 0 29.928 0.192 ;
    END
  END od[208]
  PIN od[209]
    DIRECTION OUTPUT ;
    USE SIGNAL ;
    PORT
      LAYER M3 ;
        RECT  30.024 0 30.042 0.144 ;
    END
  END od[209]
  PIN od[20]
    DIRECTION OUTPUT ;
    USE SIGNAL ;
    PORT
      LAYER M5 ;
        RECT  7.152 0 7.176 0.192 ;
    END
  END od[20]
  PIN od[210]
    DIRECTION OUTPUT ;
    USE SIGNAL ;
    PORT
      LAYER M5 ;
        RECT  30.144 0 30.168 0.192 ;
    END
  END od[210]
  PIN od[211]
    DIRECTION OUTPUT ;
    USE SIGNAL ;
    PORT
      LAYER M3 ;
        RECT  30.276 0 30.294 0.144 ;
    END
  END od[211]
  PIN od[212]
    DIRECTION OUTPUT ;
    USE SIGNAL ;
    PORT
      LAYER M5 ;
        RECT  30.384 0 30.408 0.192 ;
    END
  END od[212]
  PIN od[213]
    DIRECTION OUTPUT ;
    USE SIGNAL ;
    PORT
      LAYER M3 ;
        RECT  30.528 0 30.546 0.144 ;
    END
  END od[213]
  PIN od[214]
    DIRECTION OUTPUT ;
    USE SIGNAL ;
    PORT
      LAYER M5 ;
        RECT  30.624 0 30.648 0.192 ;
    END
  END od[214]
  PIN od[215]
    DIRECTION OUTPUT ;
    USE SIGNAL ;
    PORT
      LAYER M3 ;
        RECT  30.744 0 30.762 0.144 ;
    END
  END od[215]
  PIN od[216]
    DIRECTION OUTPUT ;
    USE SIGNAL ;
    PORT
      LAYER M5 ;
        RECT  30.864 0 30.888 0.192 ;
    END
  END od[216]
  PIN od[217]
    DIRECTION OUTPUT ;
    USE SIGNAL ;
    PORT
      LAYER M3 ;
        RECT  30.996 0 31.014 0.144 ;
    END
  END od[217]
  PIN od[218]
    DIRECTION OUTPUT ;
    USE SIGNAL ;
    PORT
      LAYER M5 ;
        RECT  31.104 0 31.128 0.192 ;
    END
  END od[218]
  PIN od[219]
    DIRECTION OUTPUT ;
    USE SIGNAL ;
    PORT
      LAYER M3 ;
        RECT  31.248 0 31.266 0.144 ;
    END
  END od[219]
  PIN od[21]
    DIRECTION OUTPUT ;
    USE SIGNAL ;
    PORT
      LAYER M3 ;
        RECT  7.272 0 7.29 0.144 ;
    END
  END od[21]
  PIN od[220]
    DIRECTION OUTPUT ;
    USE SIGNAL ;
    PORT
      LAYER M5 ;
        RECT  31.344 0 31.368 0.192 ;
    END
  END od[220]
  PIN od[221]
    DIRECTION OUTPUT ;
    USE SIGNAL ;
    PORT
      LAYER M3 ;
        RECT  31.5 0 31.518 0.144 ;
    END
  END od[221]
  PIN od[222]
    DIRECTION OUTPUT ;
    USE SIGNAL ;
    PORT
      LAYER M5 ;
        RECT  31.584 0 31.608 0.192 ;
    END
  END od[222]
  PIN od[223]
    DIRECTION OUTPUT ;
    USE SIGNAL ;
    PORT
      LAYER M3 ;
        RECT  31.716 0 31.734 0.144 ;
    END
  END od[223]
  PIN od[224]
    DIRECTION OUTPUT ;
    USE SIGNAL ;
    PORT
      LAYER M5 ;
        RECT  31.824 0 31.848 0.192 ;
    END
  END od[224]
  PIN od[225]
    DIRECTION OUTPUT ;
    USE SIGNAL ;
    PORT
      LAYER M3 ;
        RECT  31.968 0 31.986 0.144 ;
    END
  END od[225]
  PIN od[226]
    DIRECTION OUTPUT ;
    USE SIGNAL ;
    PORT
      LAYER M5 ;
        RECT  32.112 0 32.136 0.192 ;
    END
  END od[226]
  PIN od[227]
    DIRECTION OUTPUT ;
    USE SIGNAL ;
    PORT
      LAYER M3 ;
        RECT  32.22 0 32.238 0.144 ;
    END
  END od[227]
  PIN od[228]
    DIRECTION OUTPUT ;
    USE SIGNAL ;
    PORT
      LAYER M5 ;
        RECT  32.352 0 32.376 0.192 ;
    END
  END od[228]
  PIN od[229]
    DIRECTION OUTPUT ;
    USE SIGNAL ;
    PORT
      LAYER M3 ;
        RECT  32.472 0 32.49 0.144 ;
    END
  END od[229]
  PIN od[22]
    DIRECTION OUTPUT ;
    USE SIGNAL ;
    PORT
      LAYER M5 ;
        RECT  7.392 0 7.416 0.192 ;
    END
  END od[22]
  PIN od[230]
    DIRECTION OUTPUT ;
    USE SIGNAL ;
    PORT
      LAYER M5 ;
        RECT  32.592 0 32.616 0.192 ;
    END
  END od[230]
  PIN od[231]
    DIRECTION OUTPUT ;
    USE SIGNAL ;
    PORT
      LAYER M3 ;
        RECT  32.688 0 32.706 0.144 ;
    END
  END od[231]
  PIN od[232]
    DIRECTION OUTPUT ;
    USE SIGNAL ;
    PORT
      LAYER M5 ;
        RECT  32.832 0 32.856 0.192 ;
    END
  END od[232]
  PIN od[233]
    DIRECTION OUTPUT ;
    USE SIGNAL ;
    PORT
      LAYER M3 ;
        RECT  32.94 0 32.958 0.144 ;
    END
  END od[233]
  PIN od[234]
    DIRECTION OUTPUT ;
    USE SIGNAL ;
    PORT
      LAYER M5 ;
        RECT  33.072 0 33.096 0.192 ;
    END
  END od[234]
  PIN od[235]
    DIRECTION OUTPUT ;
    USE SIGNAL ;
    PORT
      LAYER M3 ;
        RECT  33.192 0 33.21 0.144 ;
    END
  END od[235]
  PIN od[236]
    DIRECTION OUTPUT ;
    USE SIGNAL ;
    PORT
      LAYER M5 ;
        RECT  33.312 0 33.336 0.192 ;
    END
  END od[236]
  PIN od[237]
    DIRECTION OUTPUT ;
    USE SIGNAL ;
    PORT
      LAYER M3 ;
        RECT  33.408 0 33.426 0.144 ;
    END
  END od[237]
  PIN od[238]
    DIRECTION OUTPUT ;
    USE SIGNAL ;
    PORT
      LAYER M5 ;
        RECT  33.552 0 33.576 0.192 ;
    END
  END od[238]
  PIN od[239]
    DIRECTION OUTPUT ;
    USE SIGNAL ;
    PORT
      LAYER M3 ;
        RECT  33.66 0 33.678 0.144 ;
    END
  END od[239]
  PIN od[23]
    DIRECTION OUTPUT ;
    USE SIGNAL ;
    PORT
      LAYER M3 ;
        RECT  7.524 0 7.542 0.144 ;
    END
  END od[23]
  PIN od[240]
    DIRECTION OUTPUT ;
    USE SIGNAL ;
    PORT
      LAYER M5 ;
        RECT  33.792 0 33.816 0.192 ;
    END
  END od[240]
  PIN od[241]
    DIRECTION OUTPUT ;
    USE SIGNAL ;
    PORT
      LAYER M3 ;
        RECT  33.912 0 33.93 0.144 ;
    END
  END od[241]
  PIN od[242]
    DIRECTION OUTPUT ;
    USE SIGNAL ;
    PORT
      LAYER M5 ;
        RECT  34.032 0 34.056 0.192 ;
    END
  END od[242]
  PIN od[243]
    DIRECTION OUTPUT ;
    USE SIGNAL ;
    PORT
      LAYER M3 ;
        RECT  34.164 0 34.182 0.144 ;
    END
  END od[243]
  PIN od[244]
    DIRECTION OUTPUT ;
    USE SIGNAL ;
    PORT
      LAYER M5 ;
        RECT  34.272 0 34.296 0.192 ;
    END
  END od[244]
  PIN od[245]
    DIRECTION OUTPUT ;
    USE SIGNAL ;
    PORT
      LAYER M3 ;
        RECT  34.38 0 34.398 0.144 ;
    END
  END od[245]
  PIN od[246]
    DIRECTION OUTPUT ;
    USE SIGNAL ;
    PORT
      LAYER M5 ;
        RECT  34.512 0 34.536 0.192 ;
    END
  END od[246]
  PIN od[247]
    DIRECTION OUTPUT ;
    USE SIGNAL ;
    PORT
      LAYER M3 ;
        RECT  34.632 0 34.65 0.144 ;
    END
  END od[247]
  PIN od[248]
    DIRECTION OUTPUT ;
    USE SIGNAL ;
    PORT
      LAYER M5 ;
        RECT  34.752 0 34.776 0.192 ;
    END
  END od[248]
  PIN od[249]
    DIRECTION OUTPUT ;
    USE SIGNAL ;
    PORT
      LAYER M3 ;
        RECT  34.884 0 34.902 0.144 ;
    END
  END od[249]
  PIN od[24]
    DIRECTION OUTPUT ;
    USE SIGNAL ;
    PORT
      LAYER M5 ;
        RECT  7.632 0 7.656 0.192 ;
    END
  END od[24]
  PIN od[250]
    DIRECTION OUTPUT ;
    USE SIGNAL ;
    PORT
      LAYER M5 ;
        RECT  34.992 0 35.016 0.192 ;
    END
  END od[250]
  PIN od[251]
    DIRECTION OUTPUT ;
    USE SIGNAL ;
    PORT
      LAYER M3 ;
        RECT  35.136 0 35.154 0.144 ;
    END
  END od[251]
  PIN od[252]
    DIRECTION OUTPUT ;
    USE SIGNAL ;
    PORT
      LAYER M5 ;
        RECT  35.232 0 35.256 0.192 ;
    END
  END od[252]
  PIN od[253]
    DIRECTION OUTPUT ;
    USE SIGNAL ;
    PORT
      LAYER M3 ;
        RECT  35.352 0 35.37 0.144 ;
    END
  END od[253]
  PIN od[254]
    DIRECTION OUTPUT ;
    USE SIGNAL ;
    PORT
      LAYER M5 ;
        RECT  35.472 0 35.496 0.192 ;
    END
  END od[254]
  PIN od[255]
    DIRECTION OUTPUT ;
    USE SIGNAL ;
    PORT
      LAYER M3 ;
        RECT  35.604 0 35.622 0.144 ;
    END
  END od[255]
  PIN od[256]
    DIRECTION OUTPUT ;
    USE SIGNAL ;
    PORT
      LAYER M5 ;
        RECT  35.712 0 35.736 0.192 ;
    END
  END od[256]
  PIN od[257]
    DIRECTION OUTPUT ;
    USE SIGNAL ;
    PORT
      LAYER M3 ;
        RECT  35.856 0 35.874 0.144 ;
    END
  END od[257]
  PIN od[258]
    DIRECTION OUTPUT ;
    USE SIGNAL ;
    PORT
      LAYER M5 ;
        RECT  35.952 0 35.976 0.192 ;
    END
  END od[258]
  PIN od[259]
    DIRECTION OUTPUT ;
    USE SIGNAL ;
    PORT
      LAYER M3 ;
        RECT  36.072 0 36.09 0.144 ;
    END
  END od[259]
  PIN od[25]
    DIRECTION OUTPUT ;
    USE SIGNAL ;
    PORT
      LAYER M3 ;
        RECT  7.776 0 7.794 0.144 ;
    END
  END od[25]
  PIN od[260]
    DIRECTION OUTPUT ;
    USE SIGNAL ;
    PORT
      LAYER M5 ;
        RECT  36.192 0 36.216 0.192 ;
    END
  END od[260]
  PIN od[261]
    DIRECTION OUTPUT ;
    USE SIGNAL ;
    PORT
      LAYER M3 ;
        RECT  36.324 0 36.342 0.144 ;
    END
  END od[261]
  PIN od[262]
    DIRECTION OUTPUT ;
    USE SIGNAL ;
    PORT
      LAYER M5 ;
        RECT  36.432 0 36.456 0.192 ;
    END
  END od[262]
  PIN od[263]
    DIRECTION OUTPUT ;
    USE SIGNAL ;
    PORT
      LAYER M3 ;
        RECT  36.576 0 36.594 0.144 ;
    END
  END od[263]
  PIN od[264]
    DIRECTION OUTPUT ;
    USE SIGNAL ;
    PORT
      LAYER M5 ;
        RECT  36.672 0 36.696 0.192 ;
    END
  END od[264]
  PIN od[265]
    DIRECTION OUTPUT ;
    USE SIGNAL ;
    PORT
      LAYER M3 ;
        RECT  36.828 0 36.846 0.144 ;
    END
  END od[265]
  PIN od[266]
    DIRECTION OUTPUT ;
    USE SIGNAL ;
    PORT
      LAYER M5 ;
        RECT  36.912 0 36.936 0.192 ;
    END
  END od[266]
  PIN od[267]
    DIRECTION OUTPUT ;
    USE SIGNAL ;
    PORT
      LAYER M3 ;
        RECT  37.044 0 37.062 0.144 ;
    END
  END od[267]
  PIN od[268]
    DIRECTION OUTPUT ;
    USE SIGNAL ;
    PORT
      LAYER M5 ;
        RECT  37.152 0 37.176 0.192 ;
    END
  END od[268]
  PIN od[269]
    DIRECTION OUTPUT ;
    USE SIGNAL ;
    PORT
      LAYER M3 ;
        RECT  37.296 0 37.314 0.144 ;
    END
  END od[269]
  PIN od[26]
    DIRECTION OUTPUT ;
    USE SIGNAL ;
    PORT
      LAYER M5 ;
        RECT  7.872 0 7.896 0.192 ;
    END
  END od[26]
  PIN od[270]
    DIRECTION OUTPUT ;
    USE SIGNAL ;
    PORT
      LAYER M5 ;
        RECT  37.392 0 37.416 0.192 ;
    END
  END od[270]
  PIN od[271]
    DIRECTION OUTPUT ;
    USE SIGNAL ;
    PORT
      LAYER M3 ;
        RECT  37.548 0 37.566 0.144 ;
    END
  END od[271]
  PIN od[272]
    DIRECTION OUTPUT ;
    USE SIGNAL ;
    PORT
      LAYER M5 ;
        RECT  37.68 0 37.704 0.192 ;
    END
  END od[272]
  PIN od[273]
    DIRECTION OUTPUT ;
    USE SIGNAL ;
    PORT
      LAYER M3 ;
        RECT  37.764 0 37.782 0.144 ;
    END
  END od[273]
  PIN od[274]
    DIRECTION OUTPUT ;
    USE SIGNAL ;
    PORT
      LAYER M5 ;
        RECT  37.92 0 37.944 0.192 ;
    END
  END od[274]
  PIN od[275]
    DIRECTION OUTPUT ;
    USE SIGNAL ;
    PORT
      LAYER M3 ;
        RECT  38.016 0 38.034 0.144 ;
    END
  END od[275]
  PIN od[276]
    DIRECTION OUTPUT ;
    USE SIGNAL ;
    PORT
      LAYER M5 ;
        RECT  38.16 0 38.184 0.192 ;
    END
  END od[276]
  PIN od[277]
    DIRECTION OUTPUT ;
    USE SIGNAL ;
    PORT
      LAYER M3 ;
        RECT  38.268 0 38.286 0.144 ;
    END
  END od[277]
  PIN od[278]
    DIRECTION OUTPUT ;
    USE SIGNAL ;
    PORT
      LAYER M5 ;
        RECT  38.4 0 38.424 0.192 ;
    END
  END od[278]
  PIN od[279]
    DIRECTION OUTPUT ;
    USE SIGNAL ;
    PORT
      LAYER M3 ;
        RECT  38.52 0 38.538 0.144 ;
    END
  END od[279]
  PIN od[27]
    DIRECTION OUTPUT ;
    USE SIGNAL ;
    PORT
      LAYER M3 ;
        RECT  7.992 0 8.01 0.144 ;
    END
  END od[27]
  PIN od[280]
    DIRECTION OUTPUT ;
    USE SIGNAL ;
    PORT
      LAYER M5 ;
        RECT  38.64 0 38.664 0.192 ;
    END
  END od[280]
  PIN od[281]
    DIRECTION OUTPUT ;
    USE SIGNAL ;
    PORT
      LAYER M3 ;
        RECT  38.736 0 38.754 0.144 ;
    END
  END od[281]
  PIN od[282]
    DIRECTION OUTPUT ;
    USE SIGNAL ;
    PORT
      LAYER M5 ;
        RECT  38.88 0 38.904 0.192 ;
    END
  END od[282]
  PIN od[283]
    DIRECTION OUTPUT ;
    USE SIGNAL ;
    PORT
      LAYER M3 ;
        RECT  38.988 0 39.006 0.144 ;
    END
  END od[283]
  PIN od[284]
    DIRECTION OUTPUT ;
    USE SIGNAL ;
    PORT
      LAYER M5 ;
        RECT  39.12 0 39.144 0.192 ;
    END
  END od[284]
  PIN od[285]
    DIRECTION OUTPUT ;
    USE SIGNAL ;
    PORT
      LAYER M3 ;
        RECT  39.24 0 39.258 0.144 ;
    END
  END od[285]
  PIN od[286]
    DIRECTION OUTPUT ;
    USE SIGNAL ;
    PORT
      LAYER M5 ;
        RECT  39.36 0 39.384 0.192 ;
    END
  END od[286]
  PIN od[287]
    DIRECTION OUTPUT ;
    USE SIGNAL ;
    PORT
      LAYER M3 ;
        RECT  39.492 0 39.51 0.144 ;
    END
  END od[287]
  PIN od[288]
    DIRECTION OUTPUT ;
    USE SIGNAL ;
    PORT
      LAYER M5 ;
        RECT  39.6 0 39.624 0.192 ;
    END
  END od[288]
  PIN od[289]
    DIRECTION OUTPUT ;
    USE SIGNAL ;
    PORT
      LAYER M3 ;
        RECT  39.708 0 39.726 0.144 ;
    END
  END od[289]
  PIN od[28]
    DIRECTION OUTPUT ;
    USE SIGNAL ;
    PORT
      LAYER M5 ;
        RECT  8.112 0 8.136 0.192 ;
    END
  END od[28]
  PIN od[290]
    DIRECTION OUTPUT ;
    USE SIGNAL ;
    PORT
      LAYER M5 ;
        RECT  39.84 0 39.864 0.192 ;
    END
  END od[290]
  PIN od[291]
    DIRECTION OUTPUT ;
    USE SIGNAL ;
    PORT
      LAYER M3 ;
        RECT  39.96 0 39.978 0.144 ;
    END
  END od[291]
  PIN od[292]
    DIRECTION OUTPUT ;
    USE SIGNAL ;
    PORT
      LAYER M5 ;
        RECT  40.08 0 40.104 0.192 ;
    END
  END od[292]
  PIN od[293]
    DIRECTION OUTPUT ;
    USE SIGNAL ;
    PORT
      LAYER M3 ;
        RECT  40.212 0 40.23 0.144 ;
    END
  END od[293]
  PIN od[294]
    DIRECTION OUTPUT ;
    USE SIGNAL ;
    PORT
      LAYER M5 ;
        RECT  40.32 0 40.344 0.192 ;
    END
  END od[294]
  PIN od[295]
    DIRECTION OUTPUT ;
    USE SIGNAL ;
    PORT
      LAYER M3 ;
        RECT  40.428 0 40.446 0.144 ;
    END
  END od[295]
  PIN od[296]
    DIRECTION OUTPUT ;
    USE SIGNAL ;
    PORT
      LAYER M5 ;
        RECT  40.56 0 40.584 0.192 ;
    END
  END od[296]
  PIN od[297]
    DIRECTION OUTPUT ;
    USE SIGNAL ;
    PORT
      LAYER M3 ;
        RECT  40.68 0 40.698 0.144 ;
    END
  END od[297]
  PIN od[298]
    DIRECTION OUTPUT ;
    USE SIGNAL ;
    PORT
      LAYER M5 ;
        RECT  40.8 0 40.824 0.192 ;
    END
  END od[298]
  PIN od[299]
    DIRECTION OUTPUT ;
    USE SIGNAL ;
    PORT
      LAYER M3 ;
        RECT  40.932 0 40.95 0.144 ;
    END
  END od[299]
  PIN od[29]
    DIRECTION OUTPUT ;
    USE SIGNAL ;
    PORT
      LAYER M3 ;
        RECT  8.244 0 8.262 0.144 ;
    END
  END od[29]
  PIN od[2]
    DIRECTION OUTPUT ;
    USE SIGNAL ;
    PORT
      LAYER M5 ;
        RECT  4.992 0 5.016 0.192 ;
    END
  END od[2]
  PIN od[300]
    DIRECTION OUTPUT ;
    USE SIGNAL ;
    PORT
      LAYER M5 ;
        RECT  41.04 0 41.064 0.192 ;
    END
  END od[300]
  PIN od[301]
    DIRECTION OUTPUT ;
    USE SIGNAL ;
    PORT
      LAYER M3 ;
        RECT  41.184 0 41.202 0.144 ;
    END
  END od[301]
  PIN od[302]
    DIRECTION OUTPUT ;
    USE SIGNAL ;
    PORT
      LAYER M5 ;
        RECT  41.28 0 41.304 0.192 ;
    END
  END od[302]
  PIN od[303]
    DIRECTION OUTPUT ;
    USE SIGNAL ;
    PORT
      LAYER M3 ;
        RECT  41.4 0 41.418 0.144 ;
    END
  END od[303]
  PIN od[304]
    DIRECTION OUTPUT ;
    USE SIGNAL ;
    PORT
      LAYER M5 ;
        RECT  41.52 0 41.544 0.192 ;
    END
  END od[304]
  PIN od[305]
    DIRECTION OUTPUT ;
    USE SIGNAL ;
    PORT
      LAYER M3 ;
        RECT  41.652 0 41.67 0.144 ;
    END
  END od[305]
  PIN od[306]
    DIRECTION OUTPUT ;
    USE SIGNAL ;
    PORT
      LAYER M5 ;
        RECT  41.76 0 41.784 0.192 ;
    END
  END od[306]
  PIN od[307]
    DIRECTION OUTPUT ;
    USE SIGNAL ;
    PORT
      LAYER M3 ;
        RECT  41.904 0 41.922 0.144 ;
    END
  END od[307]
  PIN od[308]
    DIRECTION OUTPUT ;
    USE SIGNAL ;
    PORT
      LAYER M5 ;
        RECT  42 0 42.024 0.192 ;
    END
  END od[308]
  PIN od[309]
    DIRECTION OUTPUT ;
    USE SIGNAL ;
    PORT
      LAYER M3 ;
        RECT  42.156 0 42.174 0.144 ;
    END
  END od[309]
  PIN od[30]
    DIRECTION OUTPUT ;
    USE SIGNAL ;
    PORT
      LAYER M5 ;
        RECT  8.352 0 8.376 0.192 ;
    END
  END od[30]
  PIN od[310]
    DIRECTION OUTPUT ;
    USE SIGNAL ;
    PORT
      LAYER M5 ;
        RECT  42.24 0 42.264 0.192 ;
    END
  END od[310]
  PIN od[311]
    DIRECTION OUTPUT ;
    USE SIGNAL ;
    PORT
      LAYER M3 ;
        RECT  42.372 0 42.39 0.144 ;
    END
  END od[311]
  PIN od[312]
    DIRECTION OUTPUT ;
    USE SIGNAL ;
    PORT
      LAYER M5 ;
        RECT  42.48 0 42.504 0.192 ;
    END
  END od[312]
  PIN od[313]
    DIRECTION OUTPUT ;
    USE SIGNAL ;
    PORT
      LAYER M3 ;
        RECT  42.624 0 42.642 0.144 ;
    END
  END od[313]
  PIN od[314]
    DIRECTION OUTPUT ;
    USE SIGNAL ;
    PORT
      LAYER M5 ;
        RECT  42.72 0 42.744 0.192 ;
    END
  END od[314]
  PIN od[315]
    DIRECTION OUTPUT ;
    USE SIGNAL ;
    PORT
      LAYER M3 ;
        RECT  42.876 0 42.894 0.144 ;
    END
  END od[315]
  PIN od[316]
    DIRECTION OUTPUT ;
    USE SIGNAL ;
    PORT
      LAYER M5 ;
        RECT  42.96 0 42.984 0.192 ;
    END
  END od[316]
  PIN od[317]
    DIRECTION OUTPUT ;
    USE SIGNAL ;
    PORT
      LAYER M3 ;
        RECT  43.092 0 43.11 0.144 ;
    END
  END od[317]
  PIN od[318]
    DIRECTION OUTPUT ;
    USE SIGNAL ;
    PORT
      LAYER M5 ;
        RECT  43.248 0 43.272 0.192 ;
    END
  END od[318]
  PIN od[319]
    DIRECTION OUTPUT ;
    USE SIGNAL ;
    PORT
      LAYER M3 ;
        RECT  43.344 0 43.362 0.144 ;
    END
  END od[319]
  PIN od[31]
    DIRECTION OUTPUT ;
    USE SIGNAL ;
    PORT
      LAYER M3 ;
        RECT  8.496 0 8.514 0.144 ;
    END
  END od[31]
  PIN od[320]
    DIRECTION OUTPUT ;
    USE SIGNAL ;
    PORT
      LAYER M5 ;
        RECT  43.488 0 43.512 0.192 ;
    END
  END od[320]
  PIN od[321]
    DIRECTION OUTPUT ;
    USE SIGNAL ;
    PORT
      LAYER M3 ;
        RECT  43.596 0 43.614 0.144 ;
    END
  END od[321]
  PIN od[322]
    DIRECTION OUTPUT ;
    USE SIGNAL ;
    PORT
      LAYER M5 ;
        RECT  43.728 0 43.752 0.192 ;
    END
  END od[322]
  PIN od[323]
    DIRECTION OUTPUT ;
    USE SIGNAL ;
    PORT
      LAYER M3 ;
        RECT  43.848 0 43.866 0.144 ;
    END
  END od[323]
  PIN od[324]
    DIRECTION OUTPUT ;
    USE SIGNAL ;
    PORT
      LAYER M5 ;
        RECT  43.968 0 43.992 0.192 ;
    END
  END od[324]
  PIN od[325]
    DIRECTION OUTPUT ;
    USE SIGNAL ;
    PORT
      LAYER M3 ;
        RECT  44.064 0 44.082 0.144 ;
    END
  END od[325]
  PIN od[326]
    DIRECTION OUTPUT ;
    USE SIGNAL ;
    PORT
      LAYER M5 ;
        RECT  44.208 0 44.232 0.192 ;
    END
  END od[326]
  PIN od[327]
    DIRECTION OUTPUT ;
    USE SIGNAL ;
    PORT
      LAYER M3 ;
        RECT  44.316 0 44.334 0.144 ;
    END
  END od[327]
  PIN od[328]
    DIRECTION OUTPUT ;
    USE SIGNAL ;
    PORT
      LAYER M5 ;
        RECT  44.448 0 44.472 0.192 ;
    END
  END od[328]
  PIN od[329]
    DIRECTION OUTPUT ;
    USE SIGNAL ;
    PORT
      LAYER M3 ;
        RECT  44.568 0 44.586 0.144 ;
    END
  END od[329]
  PIN od[32]
    DIRECTION OUTPUT ;
    USE SIGNAL ;
    PORT
      LAYER M5 ;
        RECT  8.592 0 8.616 0.192 ;
    END
  END od[32]
  PIN od[330]
    DIRECTION OUTPUT ;
    USE SIGNAL ;
    PORT
      LAYER M5 ;
        RECT  44.688 0 44.712 0.192 ;
    END
  END od[330]
  PIN od[331]
    DIRECTION OUTPUT ;
    USE SIGNAL ;
    PORT
      LAYER M3 ;
        RECT  44.82 0 44.838 0.144 ;
    END
  END od[331]
  PIN od[332]
    DIRECTION OUTPUT ;
    USE SIGNAL ;
    PORT
      LAYER M5 ;
        RECT  44.928 0 44.952 0.192 ;
    END
  END od[332]
  PIN od[333]
    DIRECTION OUTPUT ;
    USE SIGNAL ;
    PORT
      LAYER M3 ;
        RECT  45.036 0 45.054 0.144 ;
    END
  END od[333]
  PIN od[334]
    DIRECTION OUTPUT ;
    USE SIGNAL ;
    PORT
      LAYER M5 ;
        RECT  45.168 0 45.192 0.192 ;
    END
  END od[334]
  PIN od[335]
    DIRECTION OUTPUT ;
    USE SIGNAL ;
    PORT
      LAYER M3 ;
        RECT  45.288 0 45.306 0.144 ;
    END
  END od[335]
  PIN od[336]
    DIRECTION OUTPUT ;
    USE SIGNAL ;
    PORT
      LAYER M5 ;
        RECT  45.408 0 45.432 0.192 ;
    END
  END od[336]
  PIN od[337]
    DIRECTION OUTPUT ;
    USE SIGNAL ;
    PORT
      LAYER M3 ;
        RECT  45.54 0 45.558 0.144 ;
    END
  END od[337]
  PIN od[338]
    DIRECTION OUTPUT ;
    USE SIGNAL ;
    PORT
      LAYER M5 ;
        RECT  45.648 0 45.672 0.192 ;
    END
  END od[338]
  PIN od[339]
    DIRECTION OUTPUT ;
    USE SIGNAL ;
    PORT
      LAYER M3 ;
        RECT  45.756 0 45.774 0.144 ;
    END
  END od[339]
  PIN od[33]
    DIRECTION OUTPUT ;
    USE SIGNAL ;
    PORT
      LAYER M3 ;
        RECT  8.712 0 8.73 0.144 ;
    END
  END od[33]
  PIN od[340]
    DIRECTION OUTPUT ;
    USE SIGNAL ;
    PORT
      LAYER M5 ;
        RECT  45.888 0 45.912 0.192 ;
    END
  END od[340]
  PIN od[341]
    DIRECTION OUTPUT ;
    USE SIGNAL ;
    PORT
      LAYER M3 ;
        RECT  46.008 0 46.026 0.144 ;
    END
  END od[341]
  PIN od[342]
    DIRECTION OUTPUT ;
    USE SIGNAL ;
    PORT
      LAYER M5 ;
        RECT  46.128 0 46.152 0.192 ;
    END
  END od[342]
  PIN od[343]
    DIRECTION OUTPUT ;
    USE SIGNAL ;
    PORT
      LAYER M3 ;
        RECT  46.26 0 46.278 0.144 ;
    END
  END od[343]
  PIN od[344]
    DIRECTION OUTPUT ;
    USE SIGNAL ;
    PORT
      LAYER M5 ;
        RECT  46.368 0 46.392 0.192 ;
    END
  END od[344]
  PIN od[345]
    DIRECTION OUTPUT ;
    USE SIGNAL ;
    PORT
      LAYER M3 ;
        RECT  46.512 0 46.53 0.144 ;
    END
  END od[345]
  PIN od[346]
    DIRECTION OUTPUT ;
    USE SIGNAL ;
    PORT
      LAYER M5 ;
        RECT  46.608 0 46.632 0.192 ;
    END
  END od[346]
  PIN od[347]
    DIRECTION OUTPUT ;
    USE SIGNAL ;
    PORT
      LAYER M3 ;
        RECT  46.728 0 46.746 0.144 ;
    END
  END od[347]
  PIN od[348]
    DIRECTION OUTPUT ;
    USE SIGNAL ;
    PORT
      LAYER M5 ;
        RECT  46.848 0 46.872 0.192 ;
    END
  END od[348]
  PIN od[349]
    DIRECTION OUTPUT ;
    USE SIGNAL ;
    PORT
      LAYER M3 ;
        RECT  46.98 0 46.998 0.144 ;
    END
  END od[349]
  PIN od[34]
    DIRECTION OUTPUT ;
    USE SIGNAL ;
    PORT
      LAYER M5 ;
        RECT  8.832 0 8.856 0.192 ;
    END
  END od[34]
  PIN od[350]
    DIRECTION OUTPUT ;
    USE SIGNAL ;
    PORT
      LAYER M5 ;
        RECT  47.088 0 47.112 0.192 ;
    END
  END od[350]
  PIN od[351]
    DIRECTION OUTPUT ;
    USE SIGNAL ;
    PORT
      LAYER M3 ;
        RECT  47.232 0 47.25 0.144 ;
    END
  END od[351]
  PIN od[352]
    DIRECTION OUTPUT ;
    USE SIGNAL ;
    PORT
      LAYER M5 ;
        RECT  47.328 0 47.352 0.192 ;
    END
  END od[352]
  PIN od[353]
    DIRECTION OUTPUT ;
    USE SIGNAL ;
    PORT
      LAYER M3 ;
        RECT  47.448 0 47.466 0.144 ;
    END
  END od[353]
  PIN od[354]
    DIRECTION OUTPUT ;
    USE SIGNAL ;
    PORT
      LAYER M5 ;
        RECT  47.568 0 47.592 0.192 ;
    END
  END od[354]
  PIN od[355]
    DIRECTION OUTPUT ;
    USE SIGNAL ;
    PORT
      LAYER M3 ;
        RECT  47.7 0 47.718 0.144 ;
    END
  END od[355]
  PIN od[356]
    DIRECTION OUTPUT ;
    USE SIGNAL ;
    PORT
      LAYER M5 ;
        RECT  47.808 0 47.832 0.192 ;
    END
  END od[356]
  PIN od[357]
    DIRECTION OUTPUT ;
    USE SIGNAL ;
    PORT
      LAYER M3 ;
        RECT  47.952 0 47.97 0.144 ;
    END
  END od[357]
  PIN od[358]
    DIRECTION OUTPUT ;
    USE SIGNAL ;
    PORT
      LAYER M5 ;
        RECT  48.048 0 48.072 0.192 ;
    END
  END od[358]
  PIN od[359]
    DIRECTION OUTPUT ;
    USE SIGNAL ;
    PORT
      LAYER M3 ;
        RECT  48.204 0 48.222 0.144 ;
    END
  END od[359]
  PIN od[35]
    DIRECTION OUTPUT ;
    USE SIGNAL ;
    PORT
      LAYER M3 ;
        RECT  8.964 0 8.982 0.144 ;
    END
  END od[35]
  PIN od[360]
    DIRECTION OUTPUT ;
    USE SIGNAL ;
    PORT
      LAYER M5 ;
        RECT  48.288 0 48.312 0.192 ;
    END
  END od[360]
  PIN od[361]
    DIRECTION OUTPUT ;
    USE SIGNAL ;
    PORT
      LAYER M3 ;
        RECT  48.42 0 48.438 0.144 ;
    END
  END od[361]
  PIN od[362]
    DIRECTION OUTPUT ;
    USE SIGNAL ;
    PORT
      LAYER M5 ;
        RECT  48.576 0 48.6 0.192 ;
    END
  END od[362]
  PIN od[363]
    DIRECTION OUTPUT ;
    USE SIGNAL ;
    PORT
      LAYER M3 ;
        RECT  48.672 0 48.69 0.144 ;
    END
  END od[363]
  PIN od[364]
    DIRECTION OUTPUT ;
    USE SIGNAL ;
    PORT
      LAYER M5 ;
        RECT  48.816 0 48.84 0.192 ;
    END
  END od[364]
  PIN od[365]
    DIRECTION OUTPUT ;
    USE SIGNAL ;
    PORT
      LAYER M3 ;
        RECT  48.924 0 48.942 0.144 ;
    END
  END od[365]
  PIN od[366]
    DIRECTION OUTPUT ;
    USE SIGNAL ;
    PORT
      LAYER M5 ;
        RECT  49.056 0 49.08 0.192 ;
    END
  END od[366]
  PIN od[367]
    DIRECTION OUTPUT ;
    USE SIGNAL ;
    PORT
      LAYER M3 ;
        RECT  49.176 0 49.194 0.144 ;
    END
  END od[367]
  PIN od[368]
    DIRECTION OUTPUT ;
    USE SIGNAL ;
    PORT
      LAYER M5 ;
        RECT  49.296 0 49.32 0.192 ;
    END
  END od[368]
  PIN od[369]
    DIRECTION OUTPUT ;
    USE SIGNAL ;
    PORT
      LAYER M3 ;
        RECT  49.392 0 49.41 0.144 ;
    END
  END od[369]
  PIN od[36]
    DIRECTION OUTPUT ;
    USE SIGNAL ;
    PORT
      LAYER M5 ;
        RECT  9.072 0 9.096 0.192 ;
    END
  END od[36]
  PIN od[370]
    DIRECTION OUTPUT ;
    USE SIGNAL ;
    PORT
      LAYER M5 ;
        RECT  49.536 0 49.56 0.192 ;
    END
  END od[370]
  PIN od[371]
    DIRECTION OUTPUT ;
    USE SIGNAL ;
    PORT
      LAYER M3 ;
        RECT  49.644 0 49.662 0.144 ;
    END
  END od[371]
  PIN od[372]
    DIRECTION OUTPUT ;
    USE SIGNAL ;
    PORT
      LAYER M5 ;
        RECT  49.776 0 49.8 0.192 ;
    END
  END od[372]
  PIN od[373]
    DIRECTION OUTPUT ;
    USE SIGNAL ;
    PORT
      LAYER M3 ;
        RECT  49.896 0 49.914 0.144 ;
    END
  END od[373]
  PIN od[374]
    DIRECTION OUTPUT ;
    USE SIGNAL ;
    PORT
      LAYER M5 ;
        RECT  50.016 0 50.04 0.192 ;
    END
  END od[374]
  PIN od[375]
    DIRECTION OUTPUT ;
    USE SIGNAL ;
    PORT
      LAYER M3 ;
        RECT  50.112 0 50.13 0.144 ;
    END
  END od[375]
  PIN od[376]
    DIRECTION OUTPUT ;
    USE SIGNAL ;
    PORT
      LAYER M5 ;
        RECT  50.256 0 50.28 0.192 ;
    END
  END od[376]
  PIN od[377]
    DIRECTION OUTPUT ;
    USE SIGNAL ;
    PORT
      LAYER M3 ;
        RECT  50.364 0 50.382 0.144 ;
    END
  END od[377]
  PIN od[378]
    DIRECTION OUTPUT ;
    USE SIGNAL ;
    PORT
      LAYER M5 ;
        RECT  50.496 0 50.52 0.192 ;
    END
  END od[378]
  PIN od[379]
    DIRECTION OUTPUT ;
    USE SIGNAL ;
    PORT
      LAYER M3 ;
        RECT  50.616 0 50.634 0.144 ;
    END
  END od[379]
  PIN od[37]
    DIRECTION OUTPUT ;
    USE SIGNAL ;
    PORT
      LAYER M3 ;
        RECT  9.216 0 9.234 0.144 ;
    END
  END od[37]
  PIN od[380]
    DIRECTION OUTPUT ;
    USE SIGNAL ;
    PORT
      LAYER M5 ;
        RECT  50.736 0 50.76 0.192 ;
    END
  END od[380]
  PIN od[381]
    DIRECTION OUTPUT ;
    USE SIGNAL ;
    PORT
      LAYER M3 ;
        RECT  50.868 0 50.886 0.144 ;
    END
  END od[381]
  PIN od[382]
    DIRECTION OUTPUT ;
    USE SIGNAL ;
    PORT
      LAYER M5 ;
        RECT  50.976 0 51 0.192 ;
    END
  END od[382]
  PIN od[383]
    DIRECTION OUTPUT ;
    USE SIGNAL ;
    PORT
      LAYER M3 ;
        RECT  51.084 0 51.102 0.144 ;
    END
  END od[383]
  PIN od[384]
    DIRECTION OUTPUT ;
    USE SIGNAL ;
    PORT
      LAYER M5 ;
        RECT  51.216 0 51.24 0.192 ;
    END
  END od[384]
  PIN od[385]
    DIRECTION OUTPUT ;
    USE SIGNAL ;
    PORT
      LAYER M3 ;
        RECT  51.336 0 51.354 0.144 ;
    END
  END od[385]
  PIN od[386]
    DIRECTION OUTPUT ;
    USE SIGNAL ;
    PORT
      LAYER M5 ;
        RECT  51.456 0 51.48 0.192 ;
    END
  END od[386]
  PIN od[387]
    DIRECTION OUTPUT ;
    USE SIGNAL ;
    PORT
      LAYER M3 ;
        RECT  51.588 0 51.606 0.144 ;
    END
  END od[387]
  PIN od[388]
    DIRECTION OUTPUT ;
    USE SIGNAL ;
    PORT
      LAYER M5 ;
        RECT  51.696 0 51.72 0.192 ;
    END
  END od[388]
  PIN od[389]
    DIRECTION OUTPUT ;
    USE SIGNAL ;
    PORT
      LAYER M3 ;
        RECT  51.84 0 51.858 0.144 ;
    END
  END od[389]
  PIN od[38]
    DIRECTION OUTPUT ;
    USE SIGNAL ;
    PORT
      LAYER M5 ;
        RECT  9.312 0 9.336 0.192 ;
    END
  END od[38]
  PIN od[390]
    DIRECTION OUTPUT ;
    USE SIGNAL ;
    PORT
      LAYER M5 ;
        RECT  51.936 0 51.96 0.192 ;
    END
  END od[390]
  PIN od[391]
    DIRECTION OUTPUT ;
    USE SIGNAL ;
    PORT
      LAYER M3 ;
        RECT  52.056 0 52.074 0.144 ;
    END
  END od[391]
  PIN od[392]
    DIRECTION OUTPUT ;
    USE SIGNAL ;
    PORT
      LAYER M5 ;
        RECT  52.176 0 52.2 0.192 ;
    END
  END od[392]
  PIN od[393]
    DIRECTION OUTPUT ;
    USE SIGNAL ;
    PORT
      LAYER M3 ;
        RECT  52.308 0 52.326 0.144 ;
    END
  END od[393]
  PIN od[394]
    DIRECTION OUTPUT ;
    USE SIGNAL ;
    PORT
      LAYER M5 ;
        RECT  52.416 0 52.44 0.192 ;
    END
  END od[394]
  PIN od[395]
    DIRECTION OUTPUT ;
    USE SIGNAL ;
    PORT
      LAYER M3 ;
        RECT  52.56 0 52.578 0.144 ;
    END
  END od[395]
  PIN od[396]
    DIRECTION OUTPUT ;
    USE SIGNAL ;
    PORT
      LAYER M5 ;
        RECT  52.656 0 52.68 0.192 ;
    END
  END od[396]
  PIN od[397]
    DIRECTION OUTPUT ;
    USE SIGNAL ;
    PORT
      LAYER M3 ;
        RECT  52.776 0 52.794 0.144 ;
    END
  END od[397]
  PIN od[398]
    DIRECTION OUTPUT ;
    USE SIGNAL ;
    PORT
      LAYER M5 ;
        RECT  52.896 0 52.92 0.192 ;
    END
  END od[398]
  PIN od[399]
    DIRECTION OUTPUT ;
    USE SIGNAL ;
    PORT
      LAYER M3 ;
        RECT  53.028 0 53.046 0.144 ;
    END
  END od[399]
  PIN od[39]
    DIRECTION OUTPUT ;
    USE SIGNAL ;
    PORT
      LAYER M3 ;
        RECT  9.468 0 9.486 0.144 ;
    END
  END od[39]
  PIN od[3]
    DIRECTION OUTPUT ;
    USE SIGNAL ;
    PORT
      LAYER M3 ;
        RECT  5.112 0 5.13 0.144 ;
    END
  END od[3]
  PIN od[400]
    DIRECTION OUTPUT ;
    USE SIGNAL ;
    PORT
      LAYER M5 ;
        RECT  53.136 0 53.16 0.192 ;
    END
  END od[400]
  PIN od[401]
    DIRECTION OUTPUT ;
    USE SIGNAL ;
    PORT
      LAYER M3 ;
        RECT  53.28 0 53.298 0.144 ;
    END
  END od[401]
  PIN od[402]
    DIRECTION OUTPUT ;
    USE SIGNAL ;
    PORT
      LAYER M5 ;
        RECT  53.376 0 53.4 0.192 ;
    END
  END od[402]
  PIN od[403]
    DIRECTION OUTPUT ;
    USE SIGNAL ;
    PORT
      LAYER M3 ;
        RECT  53.532 0 53.55 0.144 ;
    END
  END od[403]
  PIN od[404]
    DIRECTION OUTPUT ;
    USE SIGNAL ;
    PORT
      LAYER M5 ;
        RECT  53.616 0 53.64 0.192 ;
    END
  END od[404]
  PIN od[405]
    DIRECTION OUTPUT ;
    USE SIGNAL ;
    PORT
      LAYER M3 ;
        RECT  53.748 0 53.766 0.144 ;
    END
  END od[405]
  PIN od[406]
    DIRECTION OUTPUT ;
    USE SIGNAL ;
    PORT
      LAYER M5 ;
        RECT  53.856 0 53.88 0.192 ;
    END
  END od[406]
  PIN od[407]
    DIRECTION OUTPUT ;
    USE SIGNAL ;
    PORT
      LAYER M3 ;
        RECT  54 0 54.018 0.144 ;
    END
  END od[407]
  PIN od[408]
    DIRECTION OUTPUT ;
    USE SIGNAL ;
    PORT
      LAYER M5 ;
        RECT  54.144 0 54.168 0.192 ;
    END
  END od[408]
  PIN od[409]
    DIRECTION OUTPUT ;
    USE SIGNAL ;
    PORT
      LAYER M3 ;
        RECT  54.252 0 54.27 0.144 ;
    END
  END od[409]
  PIN od[40]
    DIRECTION OUTPUT ;
    USE SIGNAL ;
    PORT
      LAYER M5 ;
        RECT  9.552 0 9.576 0.192 ;
    END
  END od[40]
  PIN od[410]
    DIRECTION OUTPUT ;
    USE SIGNAL ;
    PORT
      LAYER M5 ;
        RECT  54.384 0 54.408 0.192 ;
    END
  END od[410]
  PIN od[411]
    DIRECTION OUTPUT ;
    USE SIGNAL ;
    PORT
      LAYER M3 ;
        RECT  54.504 0 54.522 0.144 ;
    END
  END od[411]
  PIN od[412]
    DIRECTION OUTPUT ;
    USE SIGNAL ;
    PORT
      LAYER M5 ;
        RECT  54.624 0 54.648 0.192 ;
    END
  END od[412]
  PIN od[413]
    DIRECTION OUTPUT ;
    USE SIGNAL ;
    PORT
      LAYER M3 ;
        RECT  54.72 0 54.738 0.144 ;
    END
  END od[413]
  PIN od[414]
    DIRECTION OUTPUT ;
    USE SIGNAL ;
    PORT
      LAYER M5 ;
        RECT  54.864 0 54.888 0.192 ;
    END
  END od[414]
  PIN od[415]
    DIRECTION OUTPUT ;
    USE SIGNAL ;
    PORT
      LAYER M3 ;
        RECT  54.972 0 54.99 0.144 ;
    END
  END od[415]
  PIN od[416]
    DIRECTION OUTPUT ;
    USE SIGNAL ;
    PORT
      LAYER M5 ;
        RECT  55.104 0 55.128 0.192 ;
    END
  END od[416]
  PIN od[417]
    DIRECTION OUTPUT ;
    USE SIGNAL ;
    PORT
      LAYER M3 ;
        RECT  55.224 0 55.242 0.144 ;
    END
  END od[417]
  PIN od[418]
    DIRECTION OUTPUT ;
    USE SIGNAL ;
    PORT
      LAYER M5 ;
        RECT  55.344 0 55.368 0.192 ;
    END
  END od[418]
  PIN od[419]
    DIRECTION OUTPUT ;
    USE SIGNAL ;
    PORT
      LAYER M3 ;
        RECT  55.44 0 55.458 0.144 ;
    END
  END od[419]
  PIN od[41]
    DIRECTION OUTPUT ;
    USE SIGNAL ;
    PORT
      LAYER M3 ;
        RECT  9.684 0 9.702 0.144 ;
    END
  END od[41]
  PIN od[420]
    DIRECTION OUTPUT ;
    USE SIGNAL ;
    PORT
      LAYER M5 ;
        RECT  55.584 0 55.608 0.192 ;
    END
  END od[420]
  PIN od[421]
    DIRECTION OUTPUT ;
    USE SIGNAL ;
    PORT
      LAYER M3 ;
        RECT  55.692 0 55.71 0.144 ;
    END
  END od[421]
  PIN od[422]
    DIRECTION OUTPUT ;
    USE SIGNAL ;
    PORT
      LAYER M5 ;
        RECT  55.824 0 55.848 0.192 ;
    END
  END od[422]
  PIN od[423]
    DIRECTION OUTPUT ;
    USE SIGNAL ;
    PORT
      LAYER M3 ;
        RECT  55.944 0 55.962 0.144 ;
    END
  END od[423]
  PIN od[424]
    DIRECTION OUTPUT ;
    USE SIGNAL ;
    PORT
      LAYER M5 ;
        RECT  56.064 0 56.088 0.192 ;
    END
  END od[424]
  PIN od[425]
    DIRECTION OUTPUT ;
    USE SIGNAL ;
    PORT
      LAYER M3 ;
        RECT  56.196 0 56.214 0.144 ;
    END
  END od[425]
  PIN od[426]
    DIRECTION OUTPUT ;
    USE SIGNAL ;
    PORT
      LAYER M5 ;
        RECT  56.304 0 56.328 0.192 ;
    END
  END od[426]
  PIN od[427]
    DIRECTION OUTPUT ;
    USE SIGNAL ;
    PORT
      LAYER M3 ;
        RECT  56.412 0 56.43 0.144 ;
    END
  END od[427]
  PIN od[428]
    DIRECTION OUTPUT ;
    USE SIGNAL ;
    PORT
      LAYER M5 ;
        RECT  56.544 0 56.568 0.192 ;
    END
  END od[428]
  PIN od[429]
    DIRECTION OUTPUT ;
    USE SIGNAL ;
    PORT
      LAYER M3 ;
        RECT  56.664 0 56.682 0.144 ;
    END
  END od[429]
  PIN od[42]
    DIRECTION OUTPUT ;
    USE SIGNAL ;
    PORT
      LAYER M5 ;
        RECT  9.792 0 9.816 0.192 ;
    END
  END od[42]
  PIN od[430]
    DIRECTION OUTPUT ;
    USE SIGNAL ;
    PORT
      LAYER M5 ;
        RECT  56.784 0 56.808 0.192 ;
    END
  END od[430]
  PIN od[431]
    DIRECTION OUTPUT ;
    USE SIGNAL ;
    PORT
      LAYER M3 ;
        RECT  56.916 0 56.934 0.144 ;
    END
  END od[431]
  PIN od[432]
    DIRECTION OUTPUT ;
    USE SIGNAL ;
    PORT
      LAYER M5 ;
        RECT  57.024 0 57.048 0.192 ;
    END
  END od[432]
  PIN od[433]
    DIRECTION OUTPUT ;
    USE SIGNAL ;
    PORT
      LAYER M3 ;
        RECT  57.132 0 57.15 0.144 ;
    END
  END od[433]
  PIN od[434]
    DIRECTION OUTPUT ;
    USE SIGNAL ;
    PORT
      LAYER M5 ;
        RECT  57.264 0 57.288 0.192 ;
    END
  END od[434]
  PIN od[435]
    DIRECTION OUTPUT ;
    USE SIGNAL ;
    PORT
      LAYER M3 ;
        RECT  57.384 0 57.402 0.144 ;
    END
  END od[435]
  PIN od[436]
    DIRECTION OUTPUT ;
    USE SIGNAL ;
    PORT
      LAYER M5 ;
        RECT  57.504 0 57.528 0.192 ;
    END
  END od[436]
  PIN od[437]
    DIRECTION OUTPUT ;
    USE SIGNAL ;
    PORT
      LAYER M3 ;
        RECT  57.636 0 57.654 0.144 ;
    END
  END od[437]
  PIN od[438]
    DIRECTION OUTPUT ;
    USE SIGNAL ;
    PORT
      LAYER M5 ;
        RECT  57.744 0 57.768 0.192 ;
    END
  END od[438]
  PIN od[439]
    DIRECTION OUTPUT ;
    USE SIGNAL ;
    PORT
      LAYER M3 ;
        RECT  57.888 0 57.906 0.144 ;
    END
  END od[439]
  PIN od[43]
    DIRECTION OUTPUT ;
    USE SIGNAL ;
    PORT
      LAYER M3 ;
        RECT  9.936 0 9.954 0.144 ;
    END
  END od[43]
  PIN od[440]
    DIRECTION OUTPUT ;
    USE SIGNAL ;
    PORT
      LAYER M5 ;
        RECT  57.984 0 58.008 0.192 ;
    END
  END od[440]
  PIN od[441]
    DIRECTION OUTPUT ;
    USE SIGNAL ;
    PORT
      LAYER M3 ;
        RECT  58.104 0 58.122 0.144 ;
    END
  END od[441]
  PIN od[442]
    DIRECTION OUTPUT ;
    USE SIGNAL ;
    PORT
      LAYER M5 ;
        RECT  58.224 0 58.248 0.192 ;
    END
  END od[442]
  PIN od[443]
    DIRECTION OUTPUT ;
    USE SIGNAL ;
    PORT
      LAYER M3 ;
        RECT  58.356 0 58.374 0.144 ;
    END
  END od[443]
  PIN od[444]
    DIRECTION OUTPUT ;
    USE SIGNAL ;
    PORT
      LAYER M5 ;
        RECT  58.464 0 58.488 0.192 ;
    END
  END od[444]
  PIN od[445]
    DIRECTION OUTPUT ;
    USE SIGNAL ;
    PORT
      LAYER M3 ;
        RECT  58.608 0 58.626 0.144 ;
    END
  END od[445]
  PIN od[446]
    DIRECTION OUTPUT ;
    USE SIGNAL ;
    PORT
      LAYER M5 ;
        RECT  58.704 0 58.728 0.192 ;
    END
  END od[446]
  PIN od[447]
    DIRECTION OUTPUT ;
    USE SIGNAL ;
    PORT
      LAYER M3 ;
        RECT  58.86 0 58.878 0.144 ;
    END
  END od[447]
  PIN od[448]
    DIRECTION OUTPUT ;
    USE SIGNAL ;
    PORT
      LAYER M5 ;
        RECT  58.944 0 58.968 0.192 ;
    END
  END od[448]
  PIN od[449]
    DIRECTION OUTPUT ;
    USE SIGNAL ;
    PORT
      LAYER M3 ;
        RECT  59.076 0 59.094 0.144 ;
    END
  END od[449]
  PIN od[44]
    DIRECTION OUTPUT ;
    USE SIGNAL ;
    PORT
      LAYER M5 ;
        RECT  10.08 0 10.104 0.192 ;
    END
  END od[44]
  PIN od[450]
    DIRECTION OUTPUT ;
    USE SIGNAL ;
    PORT
      LAYER M5 ;
        RECT  59.184 0 59.208 0.192 ;
    END
  END od[450]
  PIN od[451]
    DIRECTION OUTPUT ;
    USE SIGNAL ;
    PORT
      LAYER M3 ;
        RECT  59.328 0 59.346 0.144 ;
    END
  END od[451]
  PIN od[452]
    DIRECTION OUTPUT ;
    USE SIGNAL ;
    PORT
      LAYER M5 ;
        RECT  59.424 0 59.448 0.192 ;
    END
  END od[452]
  PIN od[453]
    DIRECTION OUTPUT ;
    USE SIGNAL ;
    PORT
      LAYER M3 ;
        RECT  59.58 0 59.598 0.144 ;
    END
  END od[453]
  PIN od[454]
    DIRECTION OUTPUT ;
    USE SIGNAL ;
    PORT
      LAYER M5 ;
        RECT  59.712 0 59.736 0.192 ;
    END
  END od[454]
  PIN od[455]
    DIRECTION OUTPUT ;
    USE SIGNAL ;
    PORT
      LAYER M3 ;
        RECT  59.796 0 59.814 0.144 ;
    END
  END od[455]
  PIN od[456]
    DIRECTION OUTPUT ;
    USE SIGNAL ;
    PORT
      LAYER M5 ;
        RECT  59.952 0 59.976 0.192 ;
    END
  END od[456]
  PIN od[457]
    DIRECTION OUTPUT ;
    USE SIGNAL ;
    PORT
      LAYER M3 ;
        RECT  60.048 0 60.066 0.144 ;
    END
  END od[457]
  PIN od[458]
    DIRECTION OUTPUT ;
    USE SIGNAL ;
    PORT
      LAYER M5 ;
        RECT  60.192 0 60.216 0.192 ;
    END
  END od[458]
  PIN od[459]
    DIRECTION OUTPUT ;
    USE SIGNAL ;
    PORT
      LAYER M3 ;
        RECT  60.3 0 60.318 0.144 ;
    END
  END od[459]
  PIN od[45]
    DIRECTION OUTPUT ;
    USE SIGNAL ;
    PORT
      LAYER M3 ;
        RECT  10.188 0 10.206 0.144 ;
    END
  END od[45]
  PIN od[460]
    DIRECTION OUTPUT ;
    USE SIGNAL ;
    PORT
      LAYER M5 ;
        RECT  60.432 0 60.456 0.192 ;
    END
  END od[460]
  PIN od[461]
    DIRECTION OUTPUT ;
    USE SIGNAL ;
    PORT
      LAYER M3 ;
        RECT  60.552 0 60.57 0.144 ;
    END
  END od[461]
  PIN od[462]
    DIRECTION OUTPUT ;
    USE SIGNAL ;
    PORT
      LAYER M5 ;
        RECT  60.672 0 60.696 0.192 ;
    END
  END od[462]
  PIN od[463]
    DIRECTION OUTPUT ;
    USE SIGNAL ;
    PORT
      LAYER M3 ;
        RECT  60.768 0 60.786 0.144 ;
    END
  END od[463]
  PIN od[464]
    DIRECTION OUTPUT ;
    USE SIGNAL ;
    PORT
      LAYER M5 ;
        RECT  60.912 0 60.936 0.192 ;
    END
  END od[464]
  PIN od[465]
    DIRECTION OUTPUT ;
    USE SIGNAL ;
    PORT
      LAYER M3 ;
        RECT  61.02 0 61.038 0.144 ;
    END
  END od[465]
  PIN od[466]
    DIRECTION OUTPUT ;
    USE SIGNAL ;
    PORT
      LAYER M5 ;
        RECT  61.152 0 61.176 0.192 ;
    END
  END od[466]
  PIN od[467]
    DIRECTION OUTPUT ;
    USE SIGNAL ;
    PORT
      LAYER M3 ;
        RECT  61.272 0 61.29 0.144 ;
    END
  END od[467]
  PIN od[468]
    DIRECTION OUTPUT ;
    USE SIGNAL ;
    PORT
      LAYER M5 ;
        RECT  61.392 0 61.416 0.192 ;
    END
  END od[468]
  PIN od[469]
    DIRECTION OUTPUT ;
    USE SIGNAL ;
    PORT
      LAYER M3 ;
        RECT  61.524 0 61.542 0.144 ;
    END
  END od[469]
  PIN od[46]
    DIRECTION OUTPUT ;
    USE SIGNAL ;
    PORT
      LAYER M5 ;
        RECT  10.32 0 10.344 0.192 ;
    END
  END od[46]
  PIN od[470]
    DIRECTION OUTPUT ;
    USE SIGNAL ;
    PORT
      LAYER M5 ;
        RECT  61.632 0 61.656 0.192 ;
    END
  END od[470]
  PIN od[471]
    DIRECTION OUTPUT ;
    USE SIGNAL ;
    PORT
      LAYER M3 ;
        RECT  61.74 0 61.758 0.144 ;
    END
  END od[471]
  PIN od[472]
    DIRECTION OUTPUT ;
    USE SIGNAL ;
    PORT
      LAYER M5 ;
        RECT  61.872 0 61.896 0.192 ;
    END
  END od[472]
  PIN od[473]
    DIRECTION OUTPUT ;
    USE SIGNAL ;
    PORT
      LAYER M3 ;
        RECT  61.992 0 62.01 0.144 ;
    END
  END od[473]
  PIN od[474]
    DIRECTION OUTPUT ;
    USE SIGNAL ;
    PORT
      LAYER M5 ;
        RECT  62.112 0 62.136 0.192 ;
    END
  END od[474]
  PIN od[475]
    DIRECTION OUTPUT ;
    USE SIGNAL ;
    PORT
      LAYER M3 ;
        RECT  62.244 0 62.262 0.144 ;
    END
  END od[475]
  PIN od[476]
    DIRECTION OUTPUT ;
    USE SIGNAL ;
    PORT
      LAYER M5 ;
        RECT  62.352 0 62.376 0.192 ;
    END
  END od[476]
  PIN od[477]
    DIRECTION OUTPUT ;
    USE SIGNAL ;
    PORT
      LAYER M3 ;
        RECT  62.46 0 62.478 0.144 ;
    END
  END od[477]
  PIN od[478]
    DIRECTION OUTPUT ;
    USE SIGNAL ;
    PORT
      LAYER M5 ;
        RECT  62.592 0 62.616 0.192 ;
    END
  END od[478]
  PIN od[479]
    DIRECTION OUTPUT ;
    USE SIGNAL ;
    PORT
      LAYER M3 ;
        RECT  62.712 0 62.73 0.144 ;
    END
  END od[479]
  PIN od[47]
    DIRECTION OUTPUT ;
    USE SIGNAL ;
    PORT
      LAYER M3 ;
        RECT  10.44 0 10.458 0.144 ;
    END
  END od[47]
  PIN od[480]
    DIRECTION OUTPUT ;
    USE SIGNAL ;
    PORT
      LAYER M5 ;
        RECT  62.832 0 62.856 0.192 ;
    END
  END od[480]
  PIN od[481]
    DIRECTION OUTPUT ;
    USE SIGNAL ;
    PORT
      LAYER M3 ;
        RECT  62.964 0 62.982 0.144 ;
    END
  END od[481]
  PIN od[482]
    DIRECTION OUTPUT ;
    USE SIGNAL ;
    PORT
      LAYER M5 ;
        RECT  63.072 0 63.096 0.192 ;
    END
  END od[482]
  PIN od[483]
    DIRECTION OUTPUT ;
    USE SIGNAL ;
    PORT
      LAYER M3 ;
        RECT  63.216 0 63.234 0.144 ;
    END
  END od[483]
  PIN od[484]
    DIRECTION OUTPUT ;
    USE SIGNAL ;
    PORT
      LAYER M5 ;
        RECT  63.312 0 63.336 0.192 ;
    END
  END od[484]
  PIN od[485]
    DIRECTION OUTPUT ;
    USE SIGNAL ;
    PORT
      LAYER M3 ;
        RECT  63.432 0 63.45 0.144 ;
    END
  END od[485]
  PIN od[486]
    DIRECTION OUTPUT ;
    USE SIGNAL ;
    PORT
      LAYER M5 ;
        RECT  63.552 0 63.576 0.192 ;
    END
  END od[486]
  PIN od[487]
    DIRECTION OUTPUT ;
    USE SIGNAL ;
    PORT
      LAYER M3 ;
        RECT  63.684 0 63.702 0.144 ;
    END
  END od[487]
  PIN od[488]
    DIRECTION OUTPUT ;
    USE SIGNAL ;
    PORT
      LAYER M5 ;
        RECT  63.792 0 63.816 0.192 ;
    END
  END od[488]
  PIN od[489]
    DIRECTION OUTPUT ;
    USE SIGNAL ;
    PORT
      LAYER M3 ;
        RECT  63.936 0 63.954 0.144 ;
    END
  END od[489]
  PIN od[48]
    DIRECTION OUTPUT ;
    USE SIGNAL ;
    PORT
      LAYER M5 ;
        RECT  10.56 0 10.584 0.192 ;
    END
  END od[48]
  PIN od[490]
    DIRECTION OUTPUT ;
    USE SIGNAL ;
    PORT
      LAYER M5 ;
        RECT  64.032 0 64.056 0.192 ;
    END
  END od[490]
  PIN od[491]
    DIRECTION OUTPUT ;
    USE SIGNAL ;
    PORT
      LAYER M3 ;
        RECT  64.188 0 64.206 0.144 ;
    END
  END od[491]
  PIN od[492]
    DIRECTION OUTPUT ;
    USE SIGNAL ;
    PORT
      LAYER M5 ;
        RECT  64.272 0 64.296 0.192 ;
    END
  END od[492]
  PIN od[493]
    DIRECTION OUTPUT ;
    USE SIGNAL ;
    PORT
      LAYER M3 ;
        RECT  64.404 0 64.422 0.144 ;
    END
  END od[493]
  PIN od[494]
    DIRECTION OUTPUT ;
    USE SIGNAL ;
    PORT
      LAYER M5 ;
        RECT  64.512 0 64.536 0.192 ;
    END
  END od[494]
  PIN od[495]
    DIRECTION OUTPUT ;
    USE SIGNAL ;
    PORT
      LAYER M3 ;
        RECT  64.656 0 64.674 0.144 ;
    END
  END od[495]
  PIN od[496]
    DIRECTION OUTPUT ;
    USE SIGNAL ;
    PORT
      LAYER M5 ;
        RECT  64.752 0 64.776 0.192 ;
    END
  END od[496]
  PIN od[497]
    DIRECTION OUTPUT ;
    USE SIGNAL ;
    PORT
      LAYER M3 ;
        RECT  64.908 0 64.926 0.144 ;
    END
  END od[497]
  PIN od[498]
    DIRECTION OUTPUT ;
    USE SIGNAL ;
    PORT
      LAYER M5 ;
        RECT  64.992 0 65.016 0.192 ;
    END
  END od[498]
  PIN od[499]
    DIRECTION OUTPUT ;
    USE SIGNAL ;
    PORT
      LAYER M3 ;
        RECT  65.124 0 65.142 0.144 ;
    END
  END od[499]
  PIN od[49]
    DIRECTION OUTPUT ;
    USE SIGNAL ;
    PORT
      LAYER M3 ;
        RECT  10.656 0 10.674 0.144 ;
    END
  END od[49]
  PIN od[4]
    DIRECTION OUTPUT ;
    USE SIGNAL ;
    PORT
      LAYER M5 ;
        RECT  5.232 0 5.256 0.192 ;
    END
  END od[4]
  PIN od[500]
    DIRECTION OUTPUT ;
    USE SIGNAL ;
    PORT
      LAYER M5 ;
        RECT  65.28 0 65.304 0.192 ;
    END
  END od[500]
  PIN od[501]
    DIRECTION OUTPUT ;
    USE SIGNAL ;
    PORT
      LAYER M3 ;
        RECT  65.376 0 65.394 0.144 ;
    END
  END od[501]
  PIN od[502]
    DIRECTION OUTPUT ;
    USE SIGNAL ;
    PORT
      LAYER M5 ;
        RECT  65.52 0 65.544 0.192 ;
    END
  END od[502]
  PIN od[503]
    DIRECTION OUTPUT ;
    USE SIGNAL ;
    PORT
      LAYER M3 ;
        RECT  65.628 0 65.646 0.144 ;
    END
  END od[503]
  PIN od[504]
    DIRECTION OUTPUT ;
    USE SIGNAL ;
    PORT
      LAYER M5 ;
        RECT  65.76 0 65.784 0.192 ;
    END
  END od[504]
  PIN od[505]
    DIRECTION OUTPUT ;
    USE SIGNAL ;
    PORT
      LAYER M3 ;
        RECT  65.88 0 65.898 0.144 ;
    END
  END od[505]
  PIN od[506]
    DIRECTION OUTPUT ;
    USE SIGNAL ;
    PORT
      LAYER M5 ;
        RECT  66 0 66.024 0.192 ;
    END
  END od[506]
  PIN od[507]
    DIRECTION OUTPUT ;
    USE SIGNAL ;
    PORT
      LAYER M3 ;
        RECT  66.096 0 66.114 0.144 ;
    END
  END od[507]
  PIN od[508]
    DIRECTION OUTPUT ;
    USE SIGNAL ;
    PORT
      LAYER M5 ;
        RECT  66.24 0 66.264 0.192 ;
    END
  END od[508]
  PIN od[509]
    DIRECTION OUTPUT ;
    USE SIGNAL ;
    PORT
      LAYER M3 ;
        RECT  66.348 0 66.366 0.144 ;
    END
  END od[509]
  PIN od[50]
    DIRECTION OUTPUT ;
    USE SIGNAL ;
    PORT
      LAYER M5 ;
        RECT  10.8 0 10.824 0.192 ;
    END
  END od[50]
  PIN od[510]
    DIRECTION OUTPUT ;
    USE SIGNAL ;
    PORT
      LAYER M5 ;
        RECT  66.48 0 66.504 0.192 ;
    END
  END od[510]
  PIN od[511]
    DIRECTION OUTPUT ;
    USE SIGNAL ;
    PORT
      LAYER M3 ;
        RECT  66.6 0 66.618 0.144 ;
    END
  END od[511]
  PIN od[512]
    DIRECTION OUTPUT ;
    USE SIGNAL ;
    PORT
      LAYER M5 ;
        RECT  66.72 0 66.744 0.192 ;
    END
  END od[512]
  PIN od[513]
    DIRECTION OUTPUT ;
    USE SIGNAL ;
    PORT
      LAYER M3 ;
        RECT  66.816 0 66.834 0.144 ;
    END
  END od[513]
  PIN od[514]
    DIRECTION OUTPUT ;
    USE SIGNAL ;
    PORT
      LAYER M5 ;
        RECT  66.96 0 66.984 0.192 ;
    END
  END od[514]
  PIN od[515]
    DIRECTION OUTPUT ;
    USE SIGNAL ;
    PORT
      LAYER M3 ;
        RECT  67.068 0 67.086 0.144 ;
    END
  END od[515]
  PIN od[516]
    DIRECTION OUTPUT ;
    USE SIGNAL ;
    PORT
      LAYER M5 ;
        RECT  67.2 0 67.224 0.192 ;
    END
  END od[516]
  PIN od[517]
    DIRECTION OUTPUT ;
    USE SIGNAL ;
    PORT
      LAYER M3 ;
        RECT  67.32 0 67.338 0.144 ;
    END
  END od[517]
  PIN od[518]
    DIRECTION OUTPUT ;
    USE SIGNAL ;
    PORT
      LAYER M5 ;
        RECT  67.44 0 67.464 0.192 ;
    END
  END od[518]
  PIN od[519]
    DIRECTION OUTPUT ;
    USE SIGNAL ;
    PORT
      LAYER M3 ;
        RECT  67.572 0 67.59 0.144 ;
    END
  END od[519]
  PIN od[51]
    DIRECTION OUTPUT ;
    USE SIGNAL ;
    PORT
      LAYER M3 ;
        RECT  10.908 0 10.926 0.144 ;
    END
  END od[51]
  PIN od[520]
    DIRECTION OUTPUT ;
    USE SIGNAL ;
    PORT
      LAYER M5 ;
        RECT  67.68 0 67.704 0.192 ;
    END
  END od[520]
  PIN od[521]
    DIRECTION OUTPUT ;
    USE SIGNAL ;
    PORT
      LAYER M3 ;
        RECT  67.788 0 67.806 0.144 ;
    END
  END od[521]
  PIN od[522]
    DIRECTION OUTPUT ;
    USE SIGNAL ;
    PORT
      LAYER M5 ;
        RECT  67.92 0 67.944 0.192 ;
    END
  END od[522]
  PIN od[523]
    DIRECTION OUTPUT ;
    USE SIGNAL ;
    PORT
      LAYER M3 ;
        RECT  68.04 0 68.058 0.144 ;
    END
  END od[523]
  PIN od[524]
    DIRECTION OUTPUT ;
    USE SIGNAL ;
    PORT
      LAYER M5 ;
        RECT  68.16 0 68.184 0.192 ;
    END
  END od[524]
  PIN od[525]
    DIRECTION OUTPUT ;
    USE SIGNAL ;
    PORT
      LAYER M3 ;
        RECT  68.292 0 68.31 0.144 ;
    END
  END od[525]
  PIN od[526]
    DIRECTION OUTPUT ;
    USE SIGNAL ;
    PORT
      LAYER M5 ;
        RECT  68.4 0 68.424 0.192 ;
    END
  END od[526]
  PIN od[527]
    DIRECTION OUTPUT ;
    USE SIGNAL ;
    PORT
      LAYER M3 ;
        RECT  68.544 0 68.562 0.144 ;
    END
  END od[527]
  PIN od[528]
    DIRECTION OUTPUT ;
    USE SIGNAL ;
    PORT
      LAYER M5 ;
        RECT  68.64 0 68.664 0.192 ;
    END
  END od[528]
  PIN od[529]
    DIRECTION OUTPUT ;
    USE SIGNAL ;
    PORT
      LAYER M3 ;
        RECT  68.76 0 68.778 0.144 ;
    END
  END od[529]
  PIN od[52]
    DIRECTION OUTPUT ;
    USE SIGNAL ;
    PORT
      LAYER M5 ;
        RECT  11.04 0 11.064 0.192 ;
    END
  END od[52]
  PIN od[530]
    DIRECTION OUTPUT ;
    USE SIGNAL ;
    PORT
      LAYER M5 ;
        RECT  68.88 0 68.904 0.192 ;
    END
  END od[530]
  PIN od[531]
    DIRECTION OUTPUT ;
    USE SIGNAL ;
    PORT
      LAYER M3 ;
        RECT  69.012 0 69.03 0.144 ;
    END
  END od[531]
  PIN od[532]
    DIRECTION OUTPUT ;
    USE SIGNAL ;
    PORT
      LAYER M5 ;
        RECT  69.12 0 69.144 0.192 ;
    END
  END od[532]
  PIN od[533]
    DIRECTION OUTPUT ;
    USE SIGNAL ;
    PORT
      LAYER M3 ;
        RECT  69.264 0 69.282 0.144 ;
    END
  END od[533]
  PIN od[534]
    DIRECTION OUTPUT ;
    USE SIGNAL ;
    PORT
      LAYER M5 ;
        RECT  69.36 0 69.384 0.192 ;
    END
  END od[534]
  PIN od[535]
    DIRECTION OUTPUT ;
    USE SIGNAL ;
    PORT
      LAYER M3 ;
        RECT  69.48 0 69.498 0.144 ;
    END
  END od[535]
  PIN od[536]
    DIRECTION OUTPUT ;
    USE SIGNAL ;
    PORT
      LAYER M5 ;
        RECT  69.6 0 69.624 0.192 ;
    END
  END od[536]
  PIN od[537]
    DIRECTION OUTPUT ;
    USE SIGNAL ;
    PORT
      LAYER M3 ;
        RECT  69.732 0 69.75 0.144 ;
    END
  END od[537]
  PIN od[538]
    DIRECTION OUTPUT ;
    USE SIGNAL ;
    PORT
      LAYER M5 ;
        RECT  69.84 0 69.864 0.192 ;
    END
  END od[538]
  PIN od[539]
    DIRECTION OUTPUT ;
    USE SIGNAL ;
    PORT
      LAYER M3 ;
        RECT  69.984 0 70.002 0.144 ;
    END
  END od[539]
  PIN od[53]
    DIRECTION OUTPUT ;
    USE SIGNAL ;
    PORT
      LAYER M3 ;
        RECT  11.16 0 11.178 0.144 ;
    END
  END od[53]
  PIN od[540]
    DIRECTION OUTPUT ;
    USE SIGNAL ;
    PORT
      LAYER M5 ;
        RECT  70.08 0 70.104 0.192 ;
    END
  END od[540]
  PIN od[541]
    DIRECTION OUTPUT ;
    USE SIGNAL ;
    PORT
      LAYER M3 ;
        RECT  70.236 0 70.254 0.144 ;
    END
  END od[541]
  PIN od[542]
    DIRECTION OUTPUT ;
    USE SIGNAL ;
    PORT
      LAYER M5 ;
        RECT  70.32 0 70.344 0.192 ;
    END
  END od[542]
  PIN od[543]
    DIRECTION OUTPUT ;
    USE SIGNAL ;
    PORT
      LAYER M3 ;
        RECT  70.452 0 70.47 0.144 ;
    END
  END od[543]
  PIN od[544]
    DIRECTION OUTPUT ;
    USE SIGNAL ;
    PORT
      LAYER M5 ;
        RECT  70.56 0 70.584 0.192 ;
    END
  END od[544]
  PIN od[545]
    DIRECTION OUTPUT ;
    USE SIGNAL ;
    PORT
      LAYER M3 ;
        RECT  70.704 0 70.722 0.144 ;
    END
  END od[545]
  PIN od[546]
    DIRECTION OUTPUT ;
    USE SIGNAL ;
    PORT
      LAYER M5 ;
        RECT  70.848 0 70.872 0.192 ;
    END
  END od[546]
  PIN od[547]
    DIRECTION OUTPUT ;
    USE SIGNAL ;
    PORT
      LAYER M3 ;
        RECT  70.956 0 70.974 0.144 ;
    END
  END od[547]
  PIN od[548]
    DIRECTION OUTPUT ;
    USE SIGNAL ;
    PORT
      LAYER M5 ;
        RECT  71.088 0 71.112 0.192 ;
    END
  END od[548]
  PIN od[549]
    DIRECTION OUTPUT ;
    USE SIGNAL ;
    PORT
      LAYER M3 ;
        RECT  71.208 0 71.226 0.144 ;
    END
  END od[549]
  PIN od[54]
    DIRECTION OUTPUT ;
    USE SIGNAL ;
    PORT
      LAYER M5 ;
        RECT  11.28 0 11.304 0.192 ;
    END
  END od[54]
  PIN od[550]
    DIRECTION OUTPUT ;
    USE SIGNAL ;
    PORT
      LAYER M5 ;
        RECT  71.328 0 71.352 0.192 ;
    END
  END od[550]
  PIN od[551]
    DIRECTION OUTPUT ;
    USE SIGNAL ;
    PORT
      LAYER M3 ;
        RECT  71.424 0 71.442 0.144 ;
    END
  END od[551]
  PIN od[552]
    DIRECTION OUTPUT ;
    USE SIGNAL ;
    PORT
      LAYER M5 ;
        RECT  71.568 0 71.592 0.192 ;
    END
  END od[552]
  PIN od[553]
    DIRECTION OUTPUT ;
    USE SIGNAL ;
    PORT
      LAYER M3 ;
        RECT  71.676 0 71.694 0.144 ;
    END
  END od[553]
  PIN od[554]
    DIRECTION OUTPUT ;
    USE SIGNAL ;
    PORT
      LAYER M5 ;
        RECT  71.808 0 71.832 0.192 ;
    END
  END od[554]
  PIN od[555]
    DIRECTION OUTPUT ;
    USE SIGNAL ;
    PORT
      LAYER M3 ;
        RECT  71.928 0 71.946 0.144 ;
    END
  END od[555]
  PIN od[556]
    DIRECTION OUTPUT ;
    USE SIGNAL ;
    PORT
      LAYER M5 ;
        RECT  72.048 0 72.072 0.192 ;
    END
  END od[556]
  PIN od[557]
    DIRECTION OUTPUT ;
    USE SIGNAL ;
    PORT
      LAYER M3 ;
        RECT  72.144 0 72.162 0.144 ;
    END
  END od[557]
  PIN od[558]
    DIRECTION OUTPUT ;
    USE SIGNAL ;
    PORT
      LAYER M5 ;
        RECT  72.288 0 72.312 0.192 ;
    END
  END od[558]
  PIN od[559]
    DIRECTION OUTPUT ;
    USE SIGNAL ;
    PORT
      LAYER M3 ;
        RECT  72.396 0 72.414 0.144 ;
    END
  END od[559]
  PIN od[55]
    DIRECTION OUTPUT ;
    USE SIGNAL ;
    PORT
      LAYER M3 ;
        RECT  11.376 0 11.394 0.144 ;
    END
  END od[55]
  PIN od[560]
    DIRECTION OUTPUT ;
    USE SIGNAL ;
    PORT
      LAYER M5 ;
        RECT  72.528 0 72.552 0.192 ;
    END
  END od[560]
  PIN od[561]
    DIRECTION OUTPUT ;
    USE SIGNAL ;
    PORT
      LAYER M3 ;
        RECT  72.648 0 72.666 0.144 ;
    END
  END od[561]
  PIN od[562]
    DIRECTION OUTPUT ;
    USE SIGNAL ;
    PORT
      LAYER M5 ;
        RECT  72.768 0 72.792 0.192 ;
    END
  END od[562]
  PIN od[563]
    DIRECTION OUTPUT ;
    USE SIGNAL ;
    PORT
      LAYER M3 ;
        RECT  72.9 0 72.918 0.144 ;
    END
  END od[563]
  PIN od[564]
    DIRECTION OUTPUT ;
    USE SIGNAL ;
    PORT
      LAYER M5 ;
        RECT  73.008 0 73.032 0.192 ;
    END
  END od[564]
  PIN od[565]
    DIRECTION OUTPUT ;
    USE SIGNAL ;
    PORT
      LAYER M3 ;
        RECT  73.116 0 73.134 0.144 ;
    END
  END od[565]
  PIN od[56]
    DIRECTION OUTPUT ;
    USE SIGNAL ;
    PORT
      LAYER M5 ;
        RECT  11.52 0 11.544 0.192 ;
    END
  END od[56]
  PIN od[57]
    DIRECTION OUTPUT ;
    USE SIGNAL ;
    PORT
      LAYER M3 ;
        RECT  11.628 0 11.646 0.144 ;
    END
  END od[57]
  PIN od[58]
    DIRECTION OUTPUT ;
    USE SIGNAL ;
    PORT
      LAYER M5 ;
        RECT  11.76 0 11.784 0.192 ;
    END
  END od[58]
  PIN od[59]
    DIRECTION OUTPUT ;
    USE SIGNAL ;
    PORT
      LAYER M3 ;
        RECT  11.88 0 11.898 0.144 ;
    END
  END od[59]
  PIN od[5]
    DIRECTION OUTPUT ;
    USE SIGNAL ;
    PORT
      LAYER M3 ;
        RECT  5.328 0 5.346 0.144 ;
    END
  END od[5]
  PIN od[60]
    DIRECTION OUTPUT ;
    USE SIGNAL ;
    PORT
      LAYER M5 ;
        RECT  12 0 12.024 0.192 ;
    END
  END od[60]
  PIN od[61]
    DIRECTION OUTPUT ;
    USE SIGNAL ;
    PORT
      LAYER M3 ;
        RECT  12.132 0 12.15 0.144 ;
    END
  END od[61]
  PIN od[62]
    DIRECTION OUTPUT ;
    USE SIGNAL ;
    PORT
      LAYER M5 ;
        RECT  12.24 0 12.264 0.192 ;
    END
  END od[62]
  PIN od[63]
    DIRECTION OUTPUT ;
    USE SIGNAL ;
    PORT
      LAYER M3 ;
        RECT  12.348 0 12.366 0.144 ;
    END
  END od[63]
  PIN od[64]
    DIRECTION OUTPUT ;
    USE SIGNAL ;
    PORT
      LAYER M5 ;
        RECT  12.48 0 12.504 0.192 ;
    END
  END od[64]
  PIN od[65]
    DIRECTION OUTPUT ;
    USE SIGNAL ;
    PORT
      LAYER M3 ;
        RECT  12.6 0 12.618 0.144 ;
    END
  END od[65]
  PIN od[66]
    DIRECTION OUTPUT ;
    USE SIGNAL ;
    PORT
      LAYER M5 ;
        RECT  12.72 0 12.744 0.192 ;
    END
  END od[66]
  PIN od[67]
    DIRECTION OUTPUT ;
    USE SIGNAL ;
    PORT
      LAYER M3 ;
        RECT  12.852 0 12.87 0.144 ;
    END
  END od[67]
  PIN od[68]
    DIRECTION OUTPUT ;
    USE SIGNAL ;
    PORT
      LAYER M5 ;
        RECT  12.96 0 12.984 0.192 ;
    END
  END od[68]
  PIN od[69]
    DIRECTION OUTPUT ;
    USE SIGNAL ;
    PORT
      LAYER M3 ;
        RECT  13.104 0 13.122 0.144 ;
    END
  END od[69]
  PIN od[6]
    DIRECTION OUTPUT ;
    USE SIGNAL ;
    PORT
      LAYER M5 ;
        RECT  5.472 0 5.496 0.192 ;
    END
  END od[6]
  PIN od[70]
    DIRECTION OUTPUT ;
    USE SIGNAL ;
    PORT
      LAYER M5 ;
        RECT  13.2 0 13.224 0.192 ;
    END
  END od[70]
  PIN od[71]
    DIRECTION OUTPUT ;
    USE SIGNAL ;
    PORT
      LAYER M3 ;
        RECT  13.32 0 13.338 0.144 ;
    END
  END od[71]
  PIN od[72]
    DIRECTION OUTPUT ;
    USE SIGNAL ;
    PORT
      LAYER M5 ;
        RECT  13.44 0 13.464 0.192 ;
    END
  END od[72]
  PIN od[73]
    DIRECTION OUTPUT ;
    USE SIGNAL ;
    PORT
      LAYER M3 ;
        RECT  13.572 0 13.59 0.144 ;
    END
  END od[73]
  PIN od[74]
    DIRECTION OUTPUT ;
    USE SIGNAL ;
    PORT
      LAYER M5 ;
        RECT  13.68 0 13.704 0.192 ;
    END
  END od[74]
  PIN od[75]
    DIRECTION OUTPUT ;
    USE SIGNAL ;
    PORT
      LAYER M3 ;
        RECT  13.824 0 13.842 0.144 ;
    END
  END od[75]
  PIN od[76]
    DIRECTION OUTPUT ;
    USE SIGNAL ;
    PORT
      LAYER M5 ;
        RECT  13.92 0 13.944 0.192 ;
    END
  END od[76]
  PIN od[77]
    DIRECTION OUTPUT ;
    USE SIGNAL ;
    PORT
      LAYER M3 ;
        RECT  14.04 0 14.058 0.144 ;
    END
  END od[77]
  PIN od[78]
    DIRECTION OUTPUT ;
    USE SIGNAL ;
    PORT
      LAYER M5 ;
        RECT  14.16 0 14.184 0.192 ;
    END
  END od[78]
  PIN od[79]
    DIRECTION OUTPUT ;
    USE SIGNAL ;
    PORT
      LAYER M3 ;
        RECT  14.292 0 14.31 0.144 ;
    END
  END od[79]
  PIN od[7]
    DIRECTION OUTPUT ;
    USE SIGNAL ;
    PORT
      LAYER M3 ;
        RECT  5.58 0 5.598 0.144 ;
    END
  END od[7]
  PIN od[80]
    DIRECTION OUTPUT ;
    USE SIGNAL ;
    PORT
      LAYER M5 ;
        RECT  14.4 0 14.424 0.192 ;
    END
  END od[80]
  PIN od[81]
    DIRECTION OUTPUT ;
    USE SIGNAL ;
    PORT
      LAYER M3 ;
        RECT  14.544 0 14.562 0.144 ;
    END
  END od[81]
  PIN od[82]
    DIRECTION OUTPUT ;
    USE SIGNAL ;
    PORT
      LAYER M5 ;
        RECT  14.64 0 14.664 0.192 ;
    END
  END od[82]
  PIN od[83]
    DIRECTION OUTPUT ;
    USE SIGNAL ;
    PORT
      LAYER M3 ;
        RECT  14.796 0 14.814 0.144 ;
    END
  END od[83]
  PIN od[84]
    DIRECTION OUTPUT ;
    USE SIGNAL ;
    PORT
      LAYER M5 ;
        RECT  14.88 0 14.904 0.192 ;
    END
  END od[84]
  PIN od[85]
    DIRECTION OUTPUT ;
    USE SIGNAL ;
    PORT
      LAYER M3 ;
        RECT  15.012 0 15.03 0.144 ;
    END
  END od[85]
  PIN od[86]
    DIRECTION OUTPUT ;
    USE SIGNAL ;
    PORT
      LAYER M5 ;
        RECT  15.12 0 15.144 0.192 ;
    END
  END od[86]
  PIN od[87]
    DIRECTION OUTPUT ;
    USE SIGNAL ;
    PORT
      LAYER M3 ;
        RECT  15.264 0 15.282 0.144 ;
    END
  END od[87]
  PIN od[88]
    DIRECTION OUTPUT ;
    USE SIGNAL ;
    PORT
      LAYER M5 ;
        RECT  15.408 0 15.432 0.192 ;
    END
  END od[88]
  PIN od[89]
    DIRECTION OUTPUT ;
    USE SIGNAL ;
    PORT
      LAYER M3 ;
        RECT  15.516 0 15.534 0.144 ;
    END
  END od[89]
  PIN od[8]
    DIRECTION OUTPUT ;
    USE SIGNAL ;
    PORT
      LAYER M5 ;
        RECT  5.712 0 5.736 0.192 ;
    END
  END od[8]
  PIN od[90]
    DIRECTION OUTPUT ;
    USE SIGNAL ;
    PORT
      LAYER M5 ;
        RECT  15.648 0 15.672 0.192 ;
    END
  END od[90]
  PIN od[91]
    DIRECTION OUTPUT ;
    USE SIGNAL ;
    PORT
      LAYER M3 ;
        RECT  15.768 0 15.786 0.144 ;
    END
  END od[91]
  PIN od[92]
    DIRECTION OUTPUT ;
    USE SIGNAL ;
    PORT
      LAYER M5 ;
        RECT  15.888 0 15.912 0.192 ;
    END
  END od[92]
  PIN od[93]
    DIRECTION OUTPUT ;
    USE SIGNAL ;
    PORT
      LAYER M3 ;
        RECT  15.984 0 16.002 0.144 ;
    END
  END od[93]
  PIN od[94]
    DIRECTION OUTPUT ;
    USE SIGNAL ;
    PORT
      LAYER M5 ;
        RECT  16.128 0 16.152 0.192 ;
    END
  END od[94]
  PIN od[95]
    DIRECTION OUTPUT ;
    USE SIGNAL ;
    PORT
      LAYER M3 ;
        RECT  16.236 0 16.254 0.144 ;
    END
  END od[95]
  PIN od[96]
    DIRECTION OUTPUT ;
    USE SIGNAL ;
    PORT
      LAYER M5 ;
        RECT  16.368 0 16.392 0.192 ;
    END
  END od[96]
  PIN od[97]
    DIRECTION OUTPUT ;
    USE SIGNAL ;
    PORT
      LAYER M3 ;
        RECT  16.488 0 16.506 0.144 ;
    END
  END od[97]
  PIN od[98]
    DIRECTION OUTPUT ;
    USE SIGNAL ;
    PORT
      LAYER M5 ;
        RECT  16.608 0 16.632 0.192 ;
    END
  END od[98]
  PIN od[99]
    DIRECTION OUTPUT ;
    USE SIGNAL ;
    PORT
      LAYER M3 ;
        RECT  16.704 0 16.722 0.144 ;
    END
  END od[99]
  PIN od[9]
    DIRECTION OUTPUT ;
    USE SIGNAL ;
    PORT
      LAYER M3 ;
        RECT  5.832 0 5.85 0.144 ;
    END
  END od[9]
  PIN rs[0]
    DIRECTION INPUT ;
    USE SIGNAL ;
    PORT
      LAYER M5 ;
        RECT  73.248 0 73.272 0.192 ;
    END
  END rs[0]
  PIN rss[0]
    DIRECTION INPUT ;
    USE SIGNAL ;
    PORT
      LAYER M3 ;
        RECT  73.368 0 73.386 0.144 ;
    END
  END rss[0]
  PIN st[0]
    DIRECTION OUTPUT ;
    USE SIGNAL ;
    PORT
      LAYER M3 ;
        RECT  15.84 99.216 15.858 99.36 ;
    END
    PORT
      LAYER M3 ;
        RECT  15.84 97.217 15.858 99.228 ;
    END
  END st[0]
  PIN st[1]
    DIRECTION OUTPUT ;
    USE SIGNAL ;
    PORT
      LAYER M5 ;
        RECT  38.88 99.168 38.904 99.36 ;
    END
    PORT
      LAYER M5 ;
        RECT  38.88 98.005 38.904 99.216 ;
    END
  END st[1]
  PIN st[2]
    DIRECTION OUTPUT ;
    USE SIGNAL ;
    PORT
      LAYER M3 ;
        RECT  61.92 99.216 61.938 99.36 ;
    END
    PORT
      LAYER M3 ;
        RECT  61.92 97.295 61.938 99.228 ;
    END
  END st[2]
  PIN VDD
    DIRECTION INOUT ;
    USE POWER ;
    PORT
      LAYER M5 ;
        RECT  75.492 2.151 75.612 97.209 ;
        RECT  72.792 2.151 72.912 97.209 ;
        RECT  70.092 2.151 70.212 97.209 ;
        RECT  67.392 2.151 67.512 97.209 ;
        RECT  64.692 2.151 64.812 97.209 ;
        RECT  61.992 2.151 62.112 97.209 ;
        RECT  59.292 2.151 59.412 97.209 ;
        RECT  56.592 2.151 56.712 97.209 ;
        RECT  53.892 2.151 54.012 97.209 ;
        RECT  51.192 2.151 51.312 97.209 ;
        RECT  48.492 2.151 48.612 97.209 ;
        RECT  45.792 2.151 45.912 97.209 ;
        RECT  43.092 2.151 43.212 97.209 ;
        RECT  40.392 2.151 40.512 97.209 ;
        RECT  37.692 2.151 37.812 97.209 ;
        RECT  34.992 2.151 35.112 97.209 ;
        RECT  32.292 2.151 32.412 97.209 ;
        RECT  29.592 2.151 29.712 97.209 ;
        RECT  26.892 2.151 27.012 97.209 ;
        RECT  24.192 2.151 24.312 97.209 ;
        RECT  21.492 2.151 21.612 97.209 ;
        RECT  18.792 2.151 18.912 97.209 ;
        RECT  16.092 2.151 16.212 97.209 ;
        RECT  13.392 2.151 13.512 97.209 ;
        RECT  10.692 2.151 10.812 97.209 ;
        RECT  7.992 2.151 8.112 97.209 ;
        RECT  5.292 2.151 5.412 97.209 ;
        RECT  2.592 2.151 2.712 97.209 ;
    END
  END VDD
  PIN VSS
    DIRECTION INOUT ;
    USE GROUND ;
    PORT
      LAYER M5 ;
        RECT  75.3 2.137 75.42 97.223 ;
        RECT  72.6 2.137 72.72 97.223 ;
        RECT  69.9 2.137 70.02 97.223 ;
        RECT  67.2 2.137 67.32 97.223 ;
        RECT  64.5 2.137 64.62 97.223 ;
        RECT  61.8 2.137 61.92 97.223 ;
        RECT  59.1 2.137 59.22 97.223 ;
        RECT  56.4 2.137 56.52 97.223 ;
        RECT  53.7 2.137 53.82 97.223 ;
        RECT  51 2.137 51.12 97.223 ;
        RECT  48.3 2.137 48.42 97.223 ;
        RECT  45.6 2.137 45.72 97.223 ;
        RECT  42.9 2.137 43.02 97.223 ;
        RECT  40.2 2.137 40.32 97.223 ;
        RECT  37.5 2.137 37.62 97.223 ;
        RECT  34.8 2.137 34.92 97.223 ;
        RECT  32.1 2.137 32.22 97.223 ;
        RECT  29.4 2.137 29.52 97.223 ;
        RECT  26.7 2.137 26.82 97.223 ;
        RECT  24 2.137 24.12 97.223 ;
        RECT  21.3 2.137 21.42 97.223 ;
        RECT  18.6 2.137 18.72 97.223 ;
        RECT  15.9 2.137 16.02 97.223 ;
        RECT  13.2 2.137 13.32 97.223 ;
        RECT  10.5 2.137 10.62 97.223 ;
        RECT  7.8 2.137 7.92 97.223 ;
        RECT  5.1 2.137 5.22 97.223 ;
        RECT  2.4 2.137 2.52 97.223 ;
    END
  END VSS
  # OT_OBS_CLOSED layer=M5 d_um=1.536 added=68
  OBS
    LAYER RVTN ;
     RECT  2.16 2.16 75.6 2.295 ;
     RECT  2.16 2.565 75.6 2.835 ;
     RECT  2.16 3.105 75.6 3.375 ;
     RECT  2.16 3.645 75.6 3.915 ;
     RECT  2.16 4.185 75.6 4.455 ;
     RECT  2.16 4.725 75.6 4.995 ;
     RECT  2.16 5.265 75.6 5.535 ;
     RECT  2.16 5.805 75.6 6.075 ;
     RECT  2.16 6.345 75.6 6.615 ;
     RECT  2.16 6.885 75.6 7.155 ;
     RECT  2.16 7.425 75.6 7.695 ;
     RECT  2.16 7.965 75.6 8.235 ;
     RECT  2.16 8.505 75.6 8.775 ;
     RECT  2.16 9.045 75.6 9.315 ;
     RECT  2.16 9.585 75.6 9.855 ;
     RECT  2.16 10.125 75.6 10.395 ;
     RECT  2.16 10.665 75.6 10.935 ;
     RECT  2.16 11.205 75.6 11.475 ;
     RECT  2.16 11.745 75.6 12.015 ;
     RECT  2.16 12.285 75.6 12.555 ;
     RECT  2.16 12.825 75.6 13.095 ;
     RECT  2.16 13.365 75.6 13.635 ;
     RECT  2.16 13.905 75.6 14.175 ;
     RECT  2.16 14.445 75.6 14.715 ;
     RECT  2.16 14.985 75.6 15.255 ;
     RECT  2.16 15.525 75.6 15.795 ;
     RECT  2.16 16.065 75.6 16.335 ;
     RECT  2.16 16.605 75.6 16.875 ;
     RECT  2.16 17.145 75.6 17.415 ;
     RECT  2.16 17.685 75.6 17.955 ;
     RECT  2.16 18.225 75.6 18.495 ;
     RECT  2.16 18.765 75.6 19.035 ;
     RECT  2.16 19.305 75.6 19.575 ;
     RECT  2.16 19.845 75.6 20.115 ;
     RECT  2.16 20.385 75.6 20.655 ;
     RECT  2.16 20.925 75.6 21.195 ;
     RECT  2.16 21.465 75.6 21.735 ;
     RECT  2.16 22.005 75.6 22.275 ;
     RECT  2.16 22.545 75.6 22.815 ;
     RECT  2.16 23.085 75.6 23.355 ;
     RECT  2.16 23.625 75.6 23.895 ;
     RECT  2.16 24.165 75.6 24.435 ;
     RECT  2.16 24.705 75.6 24.975 ;
     RECT  2.16 25.245 75.6 25.515 ;
     RECT  2.16 25.785 75.6 26.055 ;
     RECT  2.16 26.325 75.6 26.595 ;
     RECT  2.16 26.865 75.6 27.135 ;
     RECT  2.16 27.405 75.6 27.675 ;
     RECT  2.16 27.945 75.6 28.215 ;
     RECT  2.16 28.485 75.6 28.755 ;
     RECT  2.16 29.025 75.6 29.295 ;
     RECT  2.16 29.565 75.6 29.835 ;
     RECT  2.16 30.105 75.6 30.375 ;
     RECT  2.16 30.645 75.6 30.915 ;
     RECT  2.16 31.185 75.6 31.455 ;
     RECT  2.16 31.725 75.6 31.995 ;
     RECT  2.16 32.265 75.6 32.535 ;
     RECT  2.16 32.805 75.6 33.075 ;
     RECT  2.16 33.345 75.6 33.615 ;
     RECT  2.16 33.885 75.6 34.155 ;
     RECT  2.16 34.425 75.6 34.695 ;
     RECT  2.16 34.965 75.6 35.235 ;
     RECT  2.16 35.505 75.6 35.775 ;
     RECT  2.16 36.045 75.6 36.315 ;
     RECT  2.16 36.585 75.6 36.855 ;
     RECT  2.16 37.125 75.6 37.395 ;
     RECT  2.16 37.665 75.6 37.935 ;
     RECT  2.16 38.205 75.6 38.475 ;
     RECT  2.16 38.745 75.6 39.015 ;
     RECT  2.16 39.285 75.6 39.555 ;
     RECT  2.16 39.825 75.6 40.095 ;
     RECT  2.16 40.365 75.6 40.635 ;
     RECT  2.16 40.905 75.6 41.175 ;
     RECT  2.16 41.445 75.6 41.715 ;
     RECT  2.16 41.985 75.6 42.255 ;
     RECT  2.16 42.525 75.6 42.795 ;
     RECT  2.16 43.065 75.6 43.335 ;
     RECT  2.16 43.605 75.6 43.875 ;
     RECT  2.16 44.145 75.6 44.415 ;
     RECT  2.16 44.685 75.6 44.955 ;
     RECT  2.16 45.225 75.6 45.495 ;
     RECT  2.16 45.765 75.6 46.035 ;
     RECT  2.16 46.305 75.6 46.575 ;
     RECT  2.16 46.845 75.6 47.115 ;
     RECT  2.16 47.385 75.6 47.655 ;
     RECT  2.16 47.925 75.6 48.195 ;
     RECT  2.16 48.465 75.6 48.735 ;
     RECT  2.16 49.005 75.6 49.275 ;
     RECT  2.16 49.545 75.6 49.815 ;
     RECT  2.16 50.085 75.6 50.355 ;
     RECT  2.16 50.625 75.6 50.895 ;
     RECT  2.16 51.165 75.6 51.435 ;
     RECT  2.16 51.705 75.6 51.975 ;
     RECT  2.16 52.245 75.6 52.515 ;
     RECT  2.16 52.785 75.6 53.055 ;
     RECT  2.16 53.325 75.6 53.595 ;
     RECT  2.16 53.865 75.6 54.135 ;
     RECT  2.16 54.405 75.6 54.675 ;
     RECT  2.16 54.945 75.6 55.215 ;
     RECT  2.16 55.485 75.6 55.755 ;
     RECT  2.16 56.025 75.6 56.295 ;
     RECT  2.16 56.565 75.6 56.835 ;
     RECT  2.16 57.105 75.6 57.375 ;
     RECT  2.16 57.645 75.6 57.915 ;
     RECT  2.16 58.185 75.6 58.455 ;
     RECT  2.16 58.725 75.6 58.995 ;
     RECT  2.16 59.265 75.6 59.535 ;
     RECT  2.16 59.805 75.6 60.075 ;
     RECT  2.16 60.345 75.6 60.615 ;
     RECT  2.16 60.885 75.6 61.155 ;
     RECT  2.16 61.425 75.6 61.695 ;
     RECT  2.16 61.965 75.6 62.235 ;
     RECT  2.16 62.505 75.6 62.775 ;
     RECT  2.16 63.045 75.6 63.315 ;
     RECT  2.16 63.585 75.6 63.855 ;
     RECT  2.16 64.125 75.6 64.395 ;
     RECT  2.16 64.665 75.6 64.935 ;
     RECT  2.16 65.205 75.6 65.475 ;
     RECT  2.16 65.745 75.6 66.015 ;
     RECT  2.16 66.285 75.6 66.555 ;
     RECT  2.16 66.825 75.6 67.095 ;
     RECT  2.16 67.365 75.6 67.635 ;
     RECT  2.16 67.905 75.6 68.175 ;
     RECT  2.16 68.445 75.6 68.715 ;
     RECT  2.16 68.985 75.6 69.255 ;
     RECT  2.16 69.525 75.6 69.795 ;
     RECT  2.16 70.065 75.6 70.335 ;
     RECT  2.16 70.605 75.6 70.875 ;
     RECT  2.16 71.145 75.6 71.415 ;
     RECT  2.16 71.685 75.6 71.955 ;
     RECT  2.16 72.225 75.6 72.495 ;
     RECT  2.16 72.765 75.6 73.035 ;
     RECT  2.16 73.305 75.6 73.575 ;
     RECT  2.16 73.845 75.6 74.115 ;
     RECT  2.16 74.385 75.6 74.655 ;
     RECT  2.16 74.925 75.6 75.195 ;
     RECT  2.16 75.465 75.6 75.735 ;
     RECT  2.16 76.005 75.6 76.275 ;
     RECT  2.16 76.545 75.6 76.815 ;
     RECT  2.16 77.085 75.6 77.355 ;
     RECT  2.16 77.625 75.6 77.895 ;
     RECT  2.16 78.165 75.6 78.435 ;
     RECT  2.16 78.705 75.6 78.975 ;
     RECT  2.16 79.245 75.6 79.515 ;
     RECT  2.16 79.785 75.6 80.055 ;
     RECT  2.16 80.325 75.6 80.595 ;
     RECT  2.16 80.865 75.6 81.135 ;
     RECT  2.16 81.405 75.6 81.675 ;
     RECT  2.16 81.945 75.6 82.215 ;
     RECT  2.16 82.485 75.6 82.755 ;
     RECT  2.16 83.025 75.6 83.295 ;
     RECT  2.16 83.565 75.6 83.835 ;
     RECT  2.16 84.105 75.6 84.375 ;
     RECT  2.16 84.645 75.6 84.915 ;
     RECT  2.16 85.185 75.6 85.455 ;
     RECT  2.16 85.725 75.6 85.995 ;
     RECT  2.16 86.265 75.6 86.535 ;
     RECT  2.16 86.805 75.6 87.075 ;
     RECT  2.16 87.345 75.6 87.615 ;
     RECT  2.16 87.885 75.6 88.155 ;
     RECT  2.16 88.425 75.6 88.695 ;
     RECT  2.16 88.965 75.6 89.235 ;
     RECT  2.16 89.505 75.6 89.775 ;
     RECT  2.16 90.045 75.6 90.315 ;
     RECT  2.16 90.585 75.6 90.855 ;
     RECT  2.16 91.125 75.6 91.395 ;
     RECT  2.16 91.665 75.6 91.935 ;
     RECT  2.16 92.205 75.6 92.475 ;
     RECT  2.16 92.745 75.6 93.015 ;
     RECT  2.16 93.285 75.6 93.555 ;
     RECT  2.16 93.825 75.6 94.095 ;
     RECT  2.16 94.365 75.6 94.635 ;
     RECT  2.16 94.905 75.6 95.175 ;
     RECT  2.16 95.445 75.6 95.715 ;
     RECT  2.16 95.985 75.6 96.255 ;
     RECT  2.16 96.525 75.6 96.795 ;
     RECT  2.16 97.065 75.6 97.2 ;
    LAYER RVTP ;
     RECT  2.16 2.295 75.6 2.565 ;
     RECT  2.16 2.835 75.6 3.105 ;
     RECT  2.16 3.375 75.6 3.645 ;
     RECT  2.16 3.915 75.6 4.185 ;
     RECT  2.16 4.455 75.6 4.725 ;
     RECT  2.16 4.995 75.6 5.265 ;
     RECT  2.16 5.535 75.6 5.805 ;
     RECT  2.16 6.075 75.6 6.345 ;
     RECT  2.16 6.615 75.6 6.885 ;
     RECT  2.16 7.155 75.6 7.425 ;
     RECT  2.16 7.695 75.6 7.965 ;
     RECT  2.16 8.235 75.6 8.505 ;
     RECT  2.16 8.775 75.6 9.045 ;
     RECT  2.16 9.315 75.6 9.585 ;
     RECT  2.16 9.855 75.6 10.125 ;
     RECT  2.16 10.395 75.6 10.665 ;
     RECT  2.16 10.935 75.6 11.205 ;
     RECT  2.16 11.475 75.6 11.745 ;
     RECT  2.16 12.015 75.6 12.285 ;
     RECT  2.16 12.555 75.6 12.825 ;
     RECT  2.16 13.095 75.6 13.365 ;
     RECT  2.16 13.635 75.6 13.905 ;
     RECT  2.16 14.175 75.6 14.445 ;
     RECT  2.16 14.715 75.6 14.985 ;
     RECT  2.16 15.255 75.6 15.525 ;
     RECT  2.16 15.795 75.6 16.065 ;
     RECT  2.16 16.335 75.6 16.605 ;
     RECT  2.16 16.875 75.6 17.145 ;
     RECT  2.16 17.415 75.6 17.685 ;
     RECT  2.16 17.955 75.6 18.225 ;
     RECT  2.16 18.495 75.6 18.765 ;
     RECT  2.16 19.035 75.6 19.305 ;
     RECT  2.16 19.575 75.6 19.845 ;
     RECT  2.16 20.115 75.6 20.385 ;
     RECT  2.16 20.655 75.6 20.925 ;
     RECT  2.16 21.195 75.6 21.465 ;
     RECT  2.16 21.735 75.6 22.005 ;
     RECT  2.16 22.275 75.6 22.545 ;
     RECT  2.16 22.815 75.6 23.085 ;
     RECT  2.16 23.355 75.6 23.625 ;
     RECT  2.16 23.895 75.6 24.165 ;
     RECT  2.16 24.435 75.6 24.705 ;
     RECT  2.16 24.975 75.6 25.245 ;
     RECT  2.16 25.515 75.6 25.785 ;
     RECT  2.16 26.055 75.6 26.325 ;
     RECT  2.16 26.595 75.6 26.865 ;
     RECT  2.16 27.135 75.6 27.405 ;
     RECT  2.16 27.675 75.6 27.945 ;
     RECT  2.16 28.215 75.6 28.485 ;
     RECT  2.16 28.755 75.6 29.025 ;
     RECT  2.16 29.295 75.6 29.565 ;
     RECT  2.16 29.835 75.6 30.105 ;
     RECT  2.16 30.375 75.6 30.645 ;
     RECT  2.16 30.915 75.6 31.185 ;
     RECT  2.16 31.455 75.6 31.725 ;
     RECT  2.16 31.995 75.6 32.265 ;
     RECT  2.16 32.535 75.6 32.805 ;
     RECT  2.16 33.075 75.6 33.345 ;
     RECT  2.16 33.615 75.6 33.885 ;
     RECT  2.16 34.155 75.6 34.425 ;
     RECT  2.16 34.695 75.6 34.965 ;
     RECT  2.16 35.235 75.6 35.505 ;
     RECT  2.16 35.775 75.6 36.045 ;
     RECT  2.16 36.315 75.6 36.585 ;
     RECT  2.16 36.855 75.6 37.125 ;
     RECT  2.16 37.395 75.6 37.665 ;
     RECT  2.16 37.935 75.6 38.205 ;
     RECT  2.16 38.475 75.6 38.745 ;
     RECT  2.16 39.015 75.6 39.285 ;
     RECT  2.16 39.555 75.6 39.825 ;
     RECT  2.16 40.095 75.6 40.365 ;
     RECT  2.16 40.635 75.6 40.905 ;
     RECT  2.16 41.175 75.6 41.445 ;
     RECT  2.16 41.715 75.6 41.985 ;
     RECT  2.16 42.255 75.6 42.525 ;
     RECT  2.16 42.795 75.6 43.065 ;
     RECT  2.16 43.335 75.6 43.605 ;
     RECT  2.16 43.875 75.6 44.145 ;
     RECT  2.16 44.415 75.6 44.685 ;
     RECT  2.16 44.955 75.6 45.225 ;
     RECT  2.16 45.495 75.6 45.765 ;
     RECT  2.16 46.035 75.6 46.305 ;
     RECT  2.16 46.575 75.6 46.845 ;
     RECT  2.16 47.115 75.6 47.385 ;
     RECT  2.16 47.655 75.6 47.925 ;
     RECT  2.16 48.195 75.6 48.465 ;
     RECT  2.16 48.735 75.6 49.005 ;
     RECT  2.16 49.275 75.6 49.545 ;
     RECT  2.16 49.815 75.6 50.085 ;
     RECT  2.16 50.355 75.6 50.625 ;
     RECT  2.16 50.895 75.6 51.165 ;
     RECT  2.16 51.435 75.6 51.705 ;
     RECT  2.16 51.975 75.6 52.245 ;
     RECT  2.16 52.515 75.6 52.785 ;
     RECT  2.16 53.055 75.6 53.325 ;
     RECT  2.16 53.595 75.6 53.865 ;
     RECT  2.16 54.135 75.6 54.405 ;
     RECT  2.16 54.675 75.6 54.945 ;
     RECT  2.16 55.215 75.6 55.485 ;
     RECT  2.16 55.755 75.6 56.025 ;
     RECT  2.16 56.295 75.6 56.565 ;
     RECT  2.16 56.835 75.6 57.105 ;
     RECT  2.16 57.375 75.6 57.645 ;
     RECT  2.16 57.915 75.6 58.185 ;
     RECT  2.16 58.455 75.6 58.725 ;
     RECT  2.16 58.995 75.6 59.265 ;
     RECT  2.16 59.535 75.6 59.805 ;
     RECT  2.16 60.075 75.6 60.345 ;
     RECT  2.16 60.615 75.6 60.885 ;
     RECT  2.16 61.155 75.6 61.425 ;
     RECT  2.16 61.695 75.6 61.965 ;
     RECT  2.16 62.235 75.6 62.505 ;
     RECT  2.16 62.775 75.6 63.045 ;
     RECT  2.16 63.315 75.6 63.585 ;
     RECT  2.16 63.855 75.6 64.125 ;
     RECT  2.16 64.395 75.6 64.665 ;
     RECT  2.16 64.935 75.6 65.205 ;
     RECT  2.16 65.475 75.6 65.745 ;
     RECT  2.16 66.015 75.6 66.285 ;
     RECT  2.16 66.555 75.6 66.825 ;
     RECT  2.16 67.095 75.6 67.365 ;
     RECT  2.16 67.635 75.6 67.905 ;
     RECT  2.16 68.175 75.6 68.445 ;
     RECT  2.16 68.715 75.6 68.985 ;
     RECT  2.16 69.255 75.6 69.525 ;
     RECT  2.16 69.795 75.6 70.065 ;
     RECT  2.16 70.335 75.6 70.605 ;
     RECT  2.16 70.875 75.6 71.145 ;
     RECT  2.16 71.415 75.6 71.685 ;
     RECT  2.16 71.955 75.6 72.225 ;
     RECT  2.16 72.495 75.6 72.765 ;
     RECT  2.16 73.035 75.6 73.305 ;
     RECT  2.16 73.575 75.6 73.845 ;
     RECT  2.16 74.115 75.6 74.385 ;
     RECT  2.16 74.655 75.6 74.925 ;
     RECT  2.16 75.195 75.6 75.465 ;
     RECT  2.16 75.735 75.6 76.005 ;
     RECT  2.16 76.275 75.6 76.545 ;
     RECT  2.16 76.815 75.6 77.085 ;
     RECT  2.16 77.355 75.6 77.625 ;
     RECT  2.16 77.895 75.6 78.165 ;
     RECT  2.16 78.435 75.6 78.705 ;
     RECT  2.16 78.975 75.6 79.245 ;
     RECT  2.16 79.515 75.6 79.785 ;
     RECT  2.16 80.055 75.6 80.325 ;
     RECT  2.16 80.595 75.6 80.865 ;
     RECT  2.16 81.135 75.6 81.405 ;
     RECT  2.16 81.675 75.6 81.945 ;
     RECT  2.16 82.215 75.6 82.485 ;
     RECT  2.16 82.755 75.6 83.025 ;
     RECT  2.16 83.295 75.6 83.565 ;
     RECT  2.16 83.835 75.6 84.105 ;
     RECT  2.16 84.375 75.6 84.645 ;
     RECT  2.16 84.915 75.6 85.185 ;
     RECT  2.16 85.455 75.6 85.725 ;
     RECT  2.16 85.995 75.6 86.265 ;
     RECT  2.16 86.535 75.6 86.805 ;
     RECT  2.16 87.075 75.6 87.345 ;
     RECT  2.16 87.615 75.6 87.885 ;
     RECT  2.16 88.155 75.6 88.425 ;
     RECT  2.16 88.695 75.6 88.965 ;
     RECT  2.16 89.235 75.6 89.505 ;
     RECT  2.16 89.775 75.6 90.045 ;
     RECT  2.16 90.315 75.6 90.585 ;
     RECT  2.16 90.855 75.6 91.125 ;
     RECT  2.16 91.395 75.6 91.665 ;
     RECT  2.16 91.935 75.6 92.205 ;
     RECT  2.16 92.475 75.6 92.745 ;
     RECT  2.16 93.015 75.6 93.285 ;
     RECT  2.16 93.555 75.6 93.825 ;
     RECT  2.16 94.095 75.6 94.365 ;
     RECT  2.16 94.635 75.6 94.905 ;
     RECT  2.16 95.175 75.6 95.445 ;
     RECT  2.16 95.715 75.6 95.985 ;
     RECT  2.16 96.255 75.6 96.525 ;
     RECT  2.16 96.795 75.6 97.065 ;
    LAYER M1 ;
     RECT  2.16 2.151 75.6 97.209 ;
    LAYER M2 ;
     RECT  0.211 14.76 2.16 14.778 ;
     RECT  0.535 16.956 2.16 16.974 ;
     RECT  0.211 19.89 2.16 19.908 ;
     RECT  0.211 23.328 2.16 23.346 ;
     RECT  0.535 47.736 2.16 47.754 ;
     RECT  0.535 48.816 2.16 48.834 ;
     RECT  0.211 58.698 2.16 59.22 ;
     RECT  0.535 63.594 2.16 63.612 ;
     RECT  0.247 76.32 2.16 76.338 ;
     RECT  0.211 79.182 2.16 79.2 ;
     RECT  0.211 89.442 2.16 89.46 ;
     RECT  0.211 94.608 2.16 94.626 ;
     RECT  2.16 2.151 4.927 97.209 ;
     RECT  4.891 0.144 6.107 0.162 ;
     RECT  4.927 2.106 6.359 97.209 ;
     RECT  6.547 1.152 6.719 1.17 ;
     RECT  6.359 2.151 7.627 97.209 ;
     RECT  7.015 0.144 7.799 0.162 ;
     RECT  7.627 2.106 7.987 97.209 ;
     RECT  7.987 1.728 8.123 97.209 ;
     RECT  8.707 1.152 8.959 1.17 ;
     RECT  8.959 1.152 9.059 1.242 ;
     RECT  9.059 1.224 9.131 1.242 ;
     RECT  8.123 2.151 10.111 97.209 ;
     RECT  10.111 2.034 10.427 97.209 ;
     RECT  10.427 2.106 11.155 97.209 ;
     RECT  11.299 0.144 11.399 0.162 ;
     RECT  10.111 1.152 11.875 1.17 ;
     RECT  11.155 1.962 11.875 97.209 ;
     RECT  11.875 1.152 11.975 97.209 ;
     RECT  11.975 1.962 12.371 97.209 ;
     RECT  12.127 0.144 13.135 0.162 ;
     RECT  11.975 1.152 13.531 1.17 ;
     RECT  12.371 2.034 13.531 97.209 ;
     RECT  13.135 0.144 13.567 0.198 ;
     RECT  13.567 0.144 13.667 0.234 ;
     RECT  13.531 1.152 14.099 1.242 ;
     RECT  14.099 1.224 14.171 1.242 ;
     RECT  13.531 1.998 14.207 97.209 ;
     RECT  13.667 0.144 14.395 0.162 ;
     RECT  14.395 0.144 14.819 0.234 ;
     RECT  14.207 2.034 16.079 97.209 ;
     RECT  14.819 0.144 16.231 0.162 ;
     RECT  16.231 0.144 16.367 0.234 ;
     RECT  16.375 1.152 17.051 1.17 ;
     RECT  16.079 2.106 18.347 97.209 ;
     RECT  16.367 0.144 20.363 0.162 ;
     RECT  18.347 2.151 21.235 97.209 ;
     RECT  21.091 0.216 21.307 0.234 ;
     RECT  21.307 0.144 21.587 0.234 ;
     RECT  21.587 0.144 21.659 0.162 ;
     RECT  21.235 2.106 21.983 97.209 ;
     RECT  21.983 2.151 23.287 97.209 ;
     RECT  23.287 2.106 23.423 97.209 ;
     RECT  22.531 0.144 23.891 0.162 ;
     RECT  24.907 0.216 25.043 0.234 ;
     RECT  25.303 1.152 25.511 1.17 ;
     RECT  25.447 0.144 25.943 0.162 ;
     RECT  23.423 2.151 27.535 97.209 ;
     RECT  27.355 1.152 27.599 1.17 ;
     RECT  27.607 1.224 27.743 1.242 ;
     RECT  27.535 2.034 28.463 97.209 ;
     RECT  28.507 1.152 28.607 1.17 ;
     RECT  28.463 2.106 29.003 97.209 ;
     RECT  28.939 1.224 29.039 1.242 ;
     RECT  29.371 1.152 29.579 1.17 ;
     RECT  29.947 1.224 30.083 1.242 ;
     RECT  29.003 2.151 30.271 97.209 ;
     RECT  26.887 0.144 30.451 0.162 ;
     RECT  30.451 0.144 30.659 0.234 ;
     RECT  30.659 0.216 30.767 0.234 ;
     RECT  31.243 1.152 31.963 1.17 ;
     RECT  31.963 1.152 32.035 1.278 ;
     RECT  32.035 1.152 32.135 1.359 ;
     RECT  31.711 0.144 32.251 0.162 ;
     RECT  32.251 0.144 32.495 0.234 ;
     RECT  30.271 2.106 32.711 97.209 ;
     RECT  32.495 0.144 32.963 0.162 ;
     RECT  32.711 2.151 34.231 97.209 ;
     RECT  33.979 0.144 35.131 0.162 ;
     RECT  35.131 0.144 35.267 0.198 ;
     RECT  33.115 1.152 35.267 1.17 ;
     RECT  36.247 1.152 36.383 1.17 ;
     RECT  35.267 0.144 37.183 0.162 ;
     RECT  34.231 2.106 37.183 97.209 ;
     RECT  37.183 2.07 37.391 97.209 ;
     RECT  37.391 2.106 37.499 97.209 ;
     RECT  37.183 0.144 37.571 0.234 ;
     RECT  37.183 1.152 37.931 1.17 ;
     RECT  37.939 1.224 38.515 1.242 ;
     RECT  38.515 1.224 38.723 1.314 ;
     RECT  37.571 0.144 38.759 0.162 ;
     RECT  38.767 0.216 39.011 0.234 ;
     RECT  38.767 1.152 39.659 1.17 ;
     RECT  39.955 0.144 40.063 0.162 ;
     RECT  40.063 0.144 40.235 0.234 ;
     RECT  40.235 0.144 40.451 0.162 ;
     RECT  37.499 2.151 40.747 97.209 ;
     RECT  40.747 1.8 40.955 97.209 ;
     RECT  41.035 0.216 41.179 0.234 ;
     RECT  41.179 0.144 41.423 0.234 ;
     RECT  40.955 2.151 42.691 97.209 ;
     RECT  41.423 0.144 43.331 0.162 ;
     RECT  43.339 0.216 43.439 0.234 ;
     RECT  42.691 2.106 44.159 97.209 ;
     RECT  44.311 0.144 46.751 0.162 ;
     RECT  44.159 2.151 47.335 97.209 ;
     RECT  48.163 0.216 48.199 0.234 ;
     RECT  47.335 2.106 48.227 97.209 ;
     RECT  48.199 0.144 48.443 0.234 ;
     RECT  48.443 0.144 49.703 0.162 ;
     RECT  50.899 0.144 51.331 0.162 ;
     RECT  51.331 0.144 51.863 0.324 ;
     RECT  51.863 0.144 52.331 0.162 ;
     RECT  48.227 2.151 52.699 97.209 ;
     RECT  53.275 0.144 53.995 0.162 ;
     RECT  53.995 0.144 54.131 0.234 ;
     RECT  52.699 2.106 56.191 97.209 ;
     RECT  54.131 0.144 56.831 0.162 ;
     RECT  56.191 2.07 56.975 97.209 ;
     RECT  57.631 0.144 58.127 0.162 ;
     RECT  56.975 2.106 58.711 97.209 ;
     RECT  59.323 0.144 59.531 0.162 ;
     RECT  60.763 0.144 61.547 0.162 ;
     RECT  58.711 1.926 61.915 97.209 ;
     RECT  61.915 1.926 62.015 97.29 ;
     RECT  62.015 1.926 62.771 97.209 ;
     RECT  62.707 0.144 63.067 0.162 ;
     RECT  63.067 0.144 63.239 0.234 ;
     RECT  63.239 0.144 64.211 0.162 ;
     RECT  65.119 0.144 65.507 0.162 ;
     RECT  66.343 0.144 66.443 0.162 ;
     RECT  66.595 1.152 66.695 1.17 ;
     RECT  67.567 1.152 68.027 1.17 ;
     RECT  62.771 1.962 68.683 97.209 ;
     RECT  68.683 1.224 68.827 97.209 ;
     RECT  68.827 1.152 69.215 97.209 ;
     RECT  69.215 1.224 69.395 97.209 ;
     RECT  67.315 0.144 69.755 0.162 ;
     RECT  69.395 1.962 69.899 97.209 ;
     RECT  69.763 0.216 70.007 0.234 ;
     RECT  70.699 0.144 71.195 0.162 ;
     RECT  70.231 1.152 71.239 1.17 ;
     RECT  71.239 1.152 71.383 1.242 ;
     RECT  71.383 1.116 71.411 1.242 ;
     RECT  71.411 1.116 71.519 1.134 ;
     RECT  69.899 2.106 72.139 97.209 ;
     RECT  72.391 1.152 72.491 1.17 ;
     RECT  72.643 0.144 72.959 0.162 ;
     RECT  72.139 2.034 74.111 97.209 ;
     RECT  74.111 2.106 74.363 97.209 ;
     RECT  74.363 2.151 75.6 97.209 ;
     RECT  75.6 2.421 75.612 96.939 ;
    LAYER M3 ;
     RECT  4.356 0.108 73.386 0.173 ;
     RECT  4.716 0.173 73.386 0.329 ;
     RECT  4.716 0.329 50.922 1.723 ;
     RECT  51.696 0.329 73.386 1.771 ;
     RECT  51.696 1.771 73.566 1.819 ;
     RECT  51.696 1.819 73.818 2.029 ;
     RECT  74.772 1.915 74.79 2.029 ;
     RECT  4.608 1.723 50.922 2.143 ;
     RECT  51.696 2.029 74.79 2.143 ;
     RECT  4.608 2.143 75.405 2.251 ;
     RECT  4.392 2.251 75.405 2.291 ;
     RECT  2.415 2.143 2.505 2.413 ;
     RECT  4.5 2.291 75.405 2.413 ;
     RECT  4.5 2.413 75.597 2.759 ;
     RECT  3.78 3.541 3.798 3.721 ;
     RECT  4.608 2.759 75.597 3.721 ;
     RECT  3.78 3.721 75.597 3.839 ;
     RECT  2.415 2.413 2.697 4.225 ;
     RECT  3.42 4.225 3.546 4.765 ;
     RECT  3.42 4.765 3.618 4.801 ;
     RECT  4.392 3.839 75.597 4.801 ;
     RECT  3.42 4.801 75.597 4.919 ;
     RECT  2.304 4.225 2.697 4.999 ;
     RECT  3.42 4.919 74.034 4.999 ;
     RECT  2.304 4.999 74.034 6.377 ;
     RECT  2.304 6.377 73.134 6.449 ;
     RECT  2.304 6.449 73.098 7.799 ;
     RECT  2.304 7.799 3.51 8.539 ;
     RECT  4.464 7.799 73.098 8.539 ;
     RECT  2.304 8.539 73.098 8.581 ;
     RECT  2.268 8.581 73.098 8.621 ;
     RECT  2.304 8.621 73.098 9.653 ;
     RECT  2.304 9.653 3.078 10.471 ;
     RECT  2.304 10.471 3.114 10.555 ;
     RECT  4.068 9.653 73.098 10.555 ;
     RECT  2.304 10.555 73.098 10.589 ;
     RECT  2.304 10.589 3.978 10.733 ;
     RECT  2.304 10.733 3.906 10.843 ;
     RECT  2.268 10.843 3.906 11.039 ;
     RECT  4.752 10.589 73.098 11.129 ;
     RECT  4.752 11.129 13.77 11.309 ;
     RECT  4.752 11.309 9.666 11.399 ;
     RECT  2.268 11.039 3.618 11.821 ;
     RECT  2.268 11.821 4.014 12.091 ;
     RECT  4.752 11.399 9.45 12.091 ;
     RECT  10.44 11.309 13.77 12.479 ;
     RECT  2.268 12.091 9.45 12.515 ;
     RECT  2.304 12.515 9.45 12.749 ;
     RECT  2.304 12.749 2.862 13.289 ;
     RECT  3.636 12.749 9.45 13.289 ;
     RECT  3.636 13.289 4.086 13.531 ;
     RECT  3.564 13.531 4.086 13.709 ;
     RECT  3.564 13.709 3.978 14.009 ;
     RECT  3.564 14.009 3.762 14.059 ;
     RECT  2.304 13.289 2.697 14.071 ;
     RECT  3.492 14.059 3.762 14.071 ;
     RECT  10.44 12.479 13.497 14.179 ;
     RECT  4.824 13.289 9.45 14.485 ;
     RECT  10.224 14.179 13.497 14.485 ;
     RECT  4.824 14.485 13.497 14.549 ;
     RECT  4.824 14.549 12.402 14.639 ;
     RECT  0.216 14.755 0.234 14.861 ;
     RECT  4.824 14.639 9.666 14.909 ;
     RECT  10.476 14.639 12.402 14.909 ;
     RECT  4.824 14.909 9.45 15.025 ;
     RECT  2.304 14.071 3.762 15.163 ;
     RECT  4.572 15.025 9.45 15.251 ;
     RECT  2.268 15.163 3.762 15.287 ;
     RECT  2.304 15.287 3.762 15.355 ;
     RECT  4.572 15.251 9.414 15.355 ;
     RECT  10.515 14.909 12.402 15.565 ;
     RECT  10.515 15.565 12.438 15.629 ;
     RECT  12.42 15.629 12.438 15.719 ;
     RECT  0.252 15.643 0.27 15.773 ;
     RECT  0.216 16.363 0.234 16.493 ;
     RECT  13.215 14.549 13.497 16.501 ;
     RECT  2.304 15.355 9.414 16.747 ;
     RECT  12.528 16.501 13.497 16.799 ;
     RECT  2.268 16.747 9.414 16.943 ;
     RECT  0.54 16.951 0.558 17.117 ;
     RECT  0.252 17.275 0.27 17.405 ;
     RECT  10.515 15.629 11.682 17.653 ;
     RECT  13.215 16.799 13.497 17.725 ;
     RECT  14.508 11.129 73.098 17.725 ;
     RECT  2.304 16.943 9.414 17.923 ;
     RECT  10.44 17.653 11.682 17.959 ;
     RECT  13.215 17.725 73.098 18.059 ;
     RECT  10.224 17.959 11.682 18.121 ;
     RECT  2.304 17.923 9.45 18.149 ;
     RECT  4.824 18.149 9.45 18.157 ;
     RECT  10.224 18.121 11.79 18.157 ;
     RECT  2.304 18.149 4.05 18.419 ;
     RECT  4.824 18.157 11.79 18.419 ;
     RECT  14.508 18.059 73.098 18.599 ;
     RECT  4.824 18.419 11.682 18.797 ;
     RECT  2.304 18.419 3.978 18.859 ;
     RECT  14.544 18.599 73.098 18.959 ;
     RECT  4.824 18.797 11.646 19.139 ;
     RECT  4.824 19.139 9.414 19.201 ;
     RECT  2.268 18.859 3.978 19.265 ;
     RECT  2.304 19.265 3.978 19.309 ;
     RECT  4.788 19.201 9.414 19.309 ;
     RECT  0.252 19.195 0.27 19.325 ;
     RECT  10.515 19.139 11.646 19.499 ;
     RECT  2.304 19.309 9.414 19.535 ;
     RECT  3.78 19.535 9.414 19.769 ;
     RECT  15.084 18.959 73.098 19.769 ;
     RECT  3.78 19.769 8.838 19.913 ;
     RECT  0.216 19.885 0.234 19.997 ;
     RECT  3.78 19.913 8.442 20.039 ;
     RECT  14.256 19.921 14.274 20.039 ;
     RECT  2.304 19.535 2.79 20.075 ;
     RECT  4.212 20.039 8.442 20.075 ;
     RECT  9.684 19.921 9.702 20.075 ;
     RECT  11.628 19.499 11.646 20.111 ;
     RECT  10.515 19.499 10.818 20.183 ;
     RECT  4.212 20.075 8.154 20.309 ;
     RECT  4.212 20.309 8.097 20.759 ;
     RECT  3.42 20.461 3.438 20.779 ;
     RECT  4.212 20.759 6.282 20.779 ;
     RECT  2.304 20.075 2.697 20.923 ;
     RECT  3.42 20.779 6.282 20.923 ;
     RECT  8.928 21.001 9.162 21.119 ;
     RECT  8.928 21.119 8.946 21.155 ;
     RECT  15.084 19.769 15.102 21.263 ;
     RECT  7.02 20.759 8.097 21.271 ;
     RECT  2.304 20.923 6.282 21.389 ;
     RECT  7.02 21.271 8.658 21.389 ;
     RECT  2.304 21.389 3.654 21.505 ;
     RECT  2.268 21.505 3.654 21.629 ;
     RECT  2.304 21.629 3.654 21.659 ;
     RECT  7.02 21.389 8.586 21.659 ;
     RECT  7.02 21.659 8.406 21.695 ;
     RECT  4.5 21.389 6.282 21.883 ;
     RECT  7.02 21.695 8.097 21.883 ;
     RECT  13.215 18.059 13.497 22.171 ;
     RECT  4.5 21.883 8.097 22.199 ;
     RECT  12.564 22.171 13.497 22.441 ;
     RECT  14.832 22.351 14.85 22.441 ;
     RECT  14.832 22.441 14.922 22.469 ;
     RECT  12.024 22.441 13.497 22.505 ;
     RECT  2.304 21.659 3.438 22.549 ;
     RECT  2.304 22.549 3.618 22.621 ;
     RECT  4.5 22.199 5.922 22.621 ;
     RECT  2.268 22.621 3.618 22.747 ;
     RECT  4.428 22.621 5.922 22.747 ;
     RECT  2.268 22.747 5.922 22.775 ;
     RECT  12.024 22.505 12.222 22.775 ;
     RECT  14.868 22.469 14.922 22.775 ;
     RECT  6.768 22.199 8.097 22.795 ;
     RECT  6.768 22.795 8.37 22.919 ;
     RECT  12.204 22.775 12.222 22.919 ;
     RECT  6.768 22.919 6.822 23.017 ;
     RECT  6.732 23.017 6.822 23.045 ;
     RECT  14.868 22.775 14.886 23.279 ;
     RECT  3.996 22.775 5.922 23.287 ;
     RECT  6.732 23.045 6.786 23.287 ;
     RECT  3.996 23.287 6.786 23.315 ;
     RECT  13.215 22.505 13.497 23.323 ;
     RECT  0.216 23.323 0.234 23.405 ;
     RECT  7.74 22.919 8.37 23.431 ;
     RECT  10.515 20.183 10.797 23.431 ;
     RECT  3.996 23.315 4.014 23.549 ;
     RECT  10.515 23.431 10.854 23.549 ;
     RECT  14.508 23.431 14.526 23.549 ;
     RECT  2.268 22.775 3.114 23.585 ;
     RECT  13.104 23.323 13.497 23.585 ;
     RECT  7.74 23.431 8.514 23.629 ;
     RECT  4.788 23.315 6.786 23.657 ;
     RECT  7.74 23.629 8.73 23.819 ;
     RECT  7.74 23.819 8.37 23.827 ;
     RECT  4.788 23.657 6.282 23.885 ;
     RECT  2.304 23.585 3.114 23.971 ;
     RECT  15.915 19.769 73.098 23.999 ;
     RECT  7.308 23.827 8.37 24.089 ;
     RECT  19.692 23.999 73.098 24.089 ;
     RECT  4.788 23.885 5.886 24.241 ;
     RECT  4.716 24.241 5.886 24.317 ;
     RECT  7.308 24.089 8.298 24.511 ;
     RECT  20.124 24.089 73.098 24.539 ;
     RECT  2.304 23.971 3.906 24.737 ;
     RECT  4.716 24.317 5.742 24.781 ;
     RECT  6.912 24.511 8.298 24.871 ;
     RECT  9.072 24.781 9.234 24.871 ;
     RECT  15.915 23.999 18.897 24.899 ;
     RECT  3.6 24.737 3.906 24.935 ;
     RECT  9.072 24.871 9.306 25.007 ;
     RECT  3.744 24.935 3.906 25.141 ;
     RECT  4.68 24.781 5.742 25.141 ;
     RECT  3.744 25.141 5.742 25.241 ;
     RECT  4.5 25.241 5.742 25.249 ;
     RECT  6.84 24.871 8.298 25.285 ;
     RECT  4.5 25.249 5.85 25.321 ;
     RECT  4.5 25.321 5.922 25.439 ;
     RECT  6.84 25.285 8.586 25.447 ;
     RECT  6.804 25.447 8.586 25.547 ;
     RECT  6.912 25.547 8.586 25.709 ;
     RECT  20.232 24.539 73.098 25.709 ;
     RECT  18.108 24.899 18.897 25.745 ;
     RECT  15.915 24.899 17.37 25.825 ;
     RECT  6.912 25.709 8.55 25.826 ;
     RECT  14.904 25.717 14.922 25.853 ;
     RECT  20.268 25.709 73.098 25.889 ;
     RECT  2.304 24.737 2.697 25.915 ;
     RECT  3.744 25.241 3.762 25.979 ;
     RECT  15.915 25.825 17.442 26.051 ;
     RECT  2.268 25.915 2.697 26.087 ;
     RECT  2.304 26.087 2.697 26.107 ;
     RECT  2.304 26.107 2.898 26.221 ;
     RECT  6.912 25.826 8.514 26.329 ;
     RECT  6.804 26.329 8.514 26.518 ;
     RECT  21.276 25.889 73.098 26.519 ;
     RECT  4.5 25.439 5.814 26.527 ;
     RECT  6.768 26.518 8.514 26.635 ;
     RECT  20.268 25.889 20.322 26.663 ;
     RECT  2.304 26.221 3.582 26.761 ;
     RECT  4.428 26.527 5.814 26.761 ;
     RECT  18.615 25.745 18.897 26.761 ;
     RECT  6.66 26.635 8.514 26.789 ;
     RECT  2.304 26.761 5.814 26.905 ;
     RECT  6.66 26.789 6.678 26.905 ;
     RECT  2.304 26.905 6.678 26.933 ;
     RECT  7.452 26.789 8.514 27.059 ;
     RECT  10.515 23.549 10.797 27.373 ;
     RECT  18.615 26.761 18.954 27.409 ;
     RECT  9.036 27.445 9.054 27.481 ;
     RECT  10.515 27.373 10.818 27.509 ;
     RECT  9.036 27.481 9.126 27.634 ;
     RECT  21.315 26.519 73.098 27.671 ;
     RECT  4.824 26.933 6.534 27.715 ;
     RECT  4.68 27.715 6.534 27.751 ;
     RECT  7.452 27.059 8.298 27.751 ;
     RECT  9.036 27.634 9.162 27.751 ;
     RECT  18.615 27.409 19.026 27.779 ;
     RECT  9.036 27.751 9.486 27.869 ;
     RECT  4.68 27.751 8.298 27.941 ;
     RECT  2.304 26.933 3.906 28.021 ;
     RECT  4.68 27.941 6.066 28.021 ;
     RECT  6.804 27.941 8.298 28.021 ;
     RECT  9.036 27.869 9.45 28.021 ;
     RECT  2.304 28.021 6.066 28.139 ;
     RECT  22.644 27.671 73.098 28.139 ;
     RECT  21.315 27.671 21.906 28.211 ;
     RECT  6.804 28.021 9.45 28.319 ;
     RECT  2.304 28.139 3.906 28.409 ;
     RECT  6.804 28.319 8.478 28.409 ;
     RECT  9.432 28.319 9.45 28.409 ;
     RECT  0.216 28.315 0.234 28.445 ;
     RECT  10.515 27.509 10.797 28.561 ;
     RECT  2.304 28.409 3.474 28.679 ;
     RECT  6.804 28.409 8.298 28.679 ;
     RECT  20.268 26.663 20.286 28.759 ;
     RECT  20.268 28.759 20.538 28.859 ;
     RECT  4.716 28.139 6.066 28.891 ;
     RECT  4.716 28.891 6.246 28.921 ;
     RECT  4.68 28.921 6.246 28.939 ;
     RECT  21.315 28.211 21.597 28.957 ;
     RECT  22.716 28.139 73.098 28.957 ;
     RECT  15.915 26.051 16.974 29.093 ;
     RECT  20.52 28.859 20.538 29.129 ;
     RECT  10.515 28.561 10.818 29.191 ;
     RECT  9.468 29.065 9.486 29.219 ;
     RECT  10.515 29.191 10.854 29.291 ;
     RECT  7.164 28.679 8.298 29.335 ;
     RECT  21.315 28.957 73.098 29.399 ;
     RECT  4.536 28.939 6.246 29.461 ;
     RECT  9.432 29.335 9.45 29.489 ;
     RECT  21.315 29.399 22.266 29.489 ;
     RECT  23.076 29.399 73.098 29.489 ;
     RECT  2.304 28.679 3.114 29.563 ;
     RECT  7.164 29.335 8.622 29.597 ;
     RECT  2.304 29.563 3.294 29.641 ;
     RECT  4.536 29.461 6.39 29.641 ;
     RECT  7.815 29.597 8.622 29.759 ;
     RECT  4.536 29.641 7.074 29.939 ;
     RECT  2.304 29.641 3.474 30.001 ;
     RECT  23.076 29.489 23.094 30.029 ;
     RECT  5.115 29.939 7.074 30.101 ;
     RECT  10.515 29.291 10.797 30.271 ;
     RECT  20.52 29.911 20.538 30.299 ;
     RECT  9.864 30.271 10.797 30.379 ;
     RECT  6.264 30.101 7.074 30.415 ;
     RECT  7.815 29.759 8.298 30.415 ;
     RECT  2.304 30.001 3.618 30.451 ;
     RECT  24.015 29.489 73.098 30.451 ;
     RECT  21.315 29.489 21.69 30.479 ;
     RECT  6.264 30.415 8.298 30.569 ;
     RECT  22.824 30.415 22.842 30.569 ;
     RECT  23.976 30.451 73.098 30.649 ;
     RECT  2.304 30.451 4.122 30.811 ;
     RECT  5.115 30.101 5.397 30.811 ;
     RECT  2.304 30.811 5.397 30.875 ;
     RECT  0.252 29.467 0.27 30.893 ;
     RECT  9.684 30.379 10.797 31.109 ;
     RECT  6.696 30.569 8.298 31.189 ;
     RECT  3.492 30.875 5.397 31.225 ;
     RECT  3.492 31.225 5.67 31.253 ;
     RECT  6.696 31.189 8.694 31.261 ;
     RECT  9.684 31.109 9.702 31.261 ;
     RECT  6.696 31.261 9.702 31.289 ;
     RECT  9.144 31.289 9.702 31.379 ;
     RECT  9.144 31.379 9.27 31.415 ;
     RECT  18.615 27.779 18.897 31.531 ;
     RECT  23.94 30.649 73.098 31.649 ;
     RECT  18.615 31.531 18.954 31.685 ;
     RECT  2.304 30.875 2.697 31.729 ;
     RECT  3.492 31.253 3.69 31.729 ;
     RECT  22.824 31.693 22.842 31.765 ;
     RECT  6.696 31.289 8.37 31.793 ;
     RECT  22.824 31.765 22.878 31.829 ;
     RECT  2.304 31.729 3.69 31.867 ;
     RECT  6.768 31.793 8.37 31.919 ;
     RECT  9.144 31.415 9.162 31.919 ;
     RECT  22.86 31.829 22.878 31.919 ;
     RECT  2.268 31.867 3.69 32.071 ;
     RECT  4.536 31.253 5.67 32.071 ;
     RECT  24.015 31.649 73.098 32.189 ;
     RECT  2.268 32.071 5.67 32.381 ;
     RECT  25.596 32.189 73.098 32.459 ;
     RECT  2.304 32.381 5.67 32.467 ;
     RECT  24.015 32.189 24.534 32.603 ;
     RECT  2.304 32.467 5.778 32.729 ;
     RECT  9.288 32.539 9.306 32.729 ;
     RECT  22.824 32.611 22.842 32.729 ;
     RECT  25.596 32.459 25.686 32.729 ;
     RECT  26.532 32.459 73.098 32.729 ;
     RECT  6.768 31.919 6.786 32.845 ;
     RECT  7.815 31.919 8.097 32.845 ;
     RECT  4.68 32.729 5.778 32.881 ;
     RECT  6.768 32.845 6.93 32.881 ;
     RECT  7.815 32.845 8.262 32.881 ;
     RECT  24.015 32.603 24.297 33.349 ;
     RECT  6.768 32.881 8.262 33.377 ;
     RECT  22.896 33.313 22.914 33.421 ;
     RECT  22.896 33.421 22.986 33.449 ;
     RECT  6.768 33.377 7.074 33.539 ;
     RECT  25.668 32.729 25.686 33.539 ;
     RECT  4.68 32.881 5.994 33.541 ;
     RECT  22.968 33.449 22.986 33.575 ;
     RECT  0.216 33.451 0.234 33.581 ;
     RECT  4.68 33.541 6.066 33.581 ;
     RECT  24.015 33.349 24.534 33.583 ;
     RECT  26.64 32.729 73.098 33.583 ;
     RECT  23.94 33.583 24.534 33.719 ;
     RECT  4.68 33.581 5.85 33.809 ;
     RECT  7.815 33.377 8.262 34.231 ;
     RECT  23.94 33.719 24.297 34.349 ;
     RECT  4.788 33.809 5.85 34.429 ;
     RECT  7.056 33.539 7.074 34.501 ;
     RECT  4.788 34.429 5.886 34.507 ;
     RECT  26.244 33.583 73.098 34.529 ;
     RECT  2.304 32.729 3.906 34.591 ;
     RECT  4.788 34.507 5.958 34.591 ;
     RECT  2.304 34.591 5.958 34.619 ;
     RECT  2.304 34.619 3.294 34.655 ;
     RECT  4.068 34.619 5.958 34.771 ;
     RECT  6.84 34.501 7.074 34.771 ;
     RECT  2.304 34.655 3.258 34.889 ;
     RECT  4.068 34.771 7.074 34.889 ;
     RECT  7.815 34.231 8.622 34.889 ;
     RECT  6.912 34.889 7.074 34.891 ;
     RECT  7.815 34.889 8.478 34.891 ;
     RECT  6.912 34.891 8.478 34.925 ;
     RECT  10.515 31.109 10.797 34.969 ;
     RECT  10.515 34.969 10.854 35.069 ;
     RECT  22.824 34.897 22.842 35.069 ;
     RECT  2.304 34.889 2.934 35.083 ;
     RECT  6.912 34.925 8.097 35.231 ;
     RECT  4.5 34.889 6.102 35.465 ;
     RECT  4.5 35.465 6.066 35.609 ;
     RECT  10.515 35.069 10.818 35.609 ;
     RECT  4.5 35.609 5.397 35.707 ;
     RECT  7.02 35.231 8.097 35.977 ;
     RECT  6.804 35.977 8.097 36.077 ;
     RECT  2.268 35.083 2.934 36.121 ;
     RECT  4.428 35.707 5.397 36.121 ;
     RECT  2.268 36.121 3.114 36.275 ;
     RECT  7.056 36.077 8.097 36.481 ;
     RECT  26.715 34.529 73.098 36.581 ;
     RECT  3.96 36.121 5.397 36.625 ;
     RECT  3.96 36.625 5.562 36.661 ;
     RECT  7.056 36.481 8.37 36.779 ;
     RECT  2.304 36.275 3.114 36.811 ;
     RECT  3.96 36.661 5.706 36.811 ;
     RECT  26.715 36.581 27.414 36.815 ;
     RECT  28.296 36.581 73.098 36.851 ;
     RECT  7.056 36.779 8.226 36.859 ;
     RECT  2.304 36.811 5.706 36.895 ;
     RECT  6.696 36.859 8.226 36.895 ;
     RECT  2.304 36.895 8.226 36.959 ;
     RECT  2.304 36.959 5.994 37.049 ;
     RECT  6.768 36.959 8.226 37.049 ;
     RECT  9.144 36.895 9.162 37.049 ;
     RECT  26.715 36.815 27.378 37.319 ;
     RECT  0.252 36.667 0.27 37.613 ;
     RECT  7.128 37.049 8.226 37.741 ;
     RECT  7.128 37.741 8.586 37.859 ;
     RECT  28.512 36.851 73.098 37.859 ;
     RECT  7.128 37.859 8.406 37.867 ;
     RECT  2.304 37.049 5.814 38.011 ;
     RECT  6.804 37.867 8.406 38.011 ;
     RECT  2.304 38.011 8.406 38.045 ;
     RECT  2.304 38.045 8.097 38.129 ;
     RECT  29.415 37.859 73.098 38.741 ;
     RECT  2.304 38.129 7.002 38.923 ;
     RECT  2.268 38.923 7.002 38.939 ;
     RECT  6.84 38.939 7.002 38.983 ;
     RECT  2.268 38.939 2.934 39.047 ;
     RECT  6.84 38.983 7.038 39.119 ;
     RECT  3.744 38.939 5.922 39.515 ;
     RECT  31.356 38.741 73.098 39.659 ;
     RECT  3.744 39.515 3.762 39.749 ;
     RECT  4.536 39.515 5.922 39.749 ;
     RECT  29.415 38.741 30.582 39.757 ;
     RECT  4.536 39.749 5.778 39.785 ;
     RECT  2.304 39.047 2.934 39.829 ;
     RECT  7.815 38.129 8.097 39.883 ;
     RECT  6.84 39.119 6.858 39.893 ;
     RECT  7.815 39.883 8.334 39.901 ;
     RECT  29.415 39.757 30.87 40.055 ;
     RECT  6.912 39.901 6.93 40.171 ;
     RECT  4.536 39.785 5.397 40.297 ;
     RECT  6.912 40.171 7.074 40.531 ;
     RECT  7.815 39.901 9.198 40.531 ;
     RECT  6.912 40.531 9.198 40.567 ;
     RECT  31.788 39.659 73.098 40.595 ;
     RECT  30.852 40.055 30.87 40.631 ;
     RECT  2.304 39.829 3.582 40.711 ;
     RECT  4.5 40.297 5.397 40.711 ;
     RECT  6.12 40.555 6.138 40.711 ;
     RECT  6.912 40.567 9.27 40.711 ;
     RECT  30.924 40.639 30.942 40.739 ;
     RECT  2.304 40.711 9.27 40.801 ;
     RECT  29.415 40.055 29.697 40.801 ;
     RECT  2.304 40.801 9.342 40.829 ;
     RECT  27.936 39.631 27.954 40.829 ;
     RECT  6.3 40.829 9.342 40.901 ;
     RECT  6.3 40.901 8.19 40.937 ;
     RECT  6.732 40.937 8.19 40.973 ;
     RECT  9.324 40.901 9.342 40.973 ;
     RECT  2.304 40.829 5.397 41.135 ;
     RECT  29.415 40.801 29.754 41.279 ;
     RECT  3.636 41.135 5.397 41.639 ;
     RECT  30.78 41.719 30.798 41.791 ;
     RECT  2.304 41.135 2.697 41.899 ;
     RECT  0.216 41.803 0.234 41.933 ;
     RECT  30.78 41.791 30.87 41.945 ;
     RECT  6.732 40.973 8.097 41.953 ;
     RECT  10.515 35.609 10.797 41.989 ;
     RECT  6.66 41.953 8.097 42.061 ;
     RECT  31.932 40.595 73.098 42.061 ;
     RECT  30.78 41.945 30.798 42.089 ;
     RECT  6.66 42.061 8.514 42.179 ;
     RECT  9.288 42.061 9.306 42.179 ;
     RECT  10.515 41.989 10.818 42.179 ;
     RECT  31.716 42.061 73.098 42.179 ;
     RECT  6.66 42.179 8.097 42.295 ;
     RECT  31.896 42.179 73.098 42.359 ;
     RECT  2.304 41.899 3.474 42.421 ;
     RECT  4.356 41.639 5.397 42.421 ;
     RECT  6.444 42.295 8.097 42.449 ;
     RECT  32.115 42.359 73.098 42.449 ;
     RECT  9.36 42.187 9.378 42.719 ;
     RECT  0.252 42.619 0.27 42.749 ;
     RECT  6.732 42.449 8.097 42.755 ;
     RECT  29.415 41.279 29.697 42.997 ;
     RECT  33.264 42.449 73.098 43.097 ;
     RECT  30.78 43.069 30.798 43.169 ;
     RECT  2.304 42.421 5.397 43.243 ;
     RECT  33.264 43.097 33.282 43.259 ;
     RECT  32.115 42.449 32.526 43.303 ;
     RECT  31.932 43.303 32.526 43.411 ;
     RECT  31.932 43.411 33.21 43.439 ;
     RECT  2.268 43.243 5.397 43.529 ;
     RECT  73.908 6.377 74.034 43.601 ;
     RECT  2.268 43.529 4.014 43.799 ;
     RECT  29.415 42.997 29.754 43.799 ;
     RECT  2.268 43.799 3.978 43.835 ;
     RECT  34.272 43.097 73.098 43.951 ;
     RECT  33.192 43.439 33.21 44.069 ;
     RECT  2.268 43.835 3.186 44.105 ;
     RECT  6.84 42.755 8.097 44.141 ;
     RECT  5.115 43.529 5.397 44.149 ;
     RECT  5.115 44.149 5.67 44.221 ;
     RECT  7.02 44.141 8.097 44.221 ;
     RECT  34.164 43.951 73.098 44.249 ;
     RECT  5.115 44.221 5.814 44.299 ;
     RECT  34.308 44.249 73.098 44.339 ;
     RECT  4.716 44.299 5.814 44.375 ;
     RECT  0.252 44.251 0.27 44.381 ;
     RECT  7.02 44.221 8.514 44.455 ;
     RECT  31.932 43.439 32.397 44.483 ;
     RECT  7.02 44.455 9.234 44.491 ;
     RECT  7.02 44.491 9.306 44.609 ;
     RECT  7.02 44.609 8.37 44.645 ;
     RECT  9.216 44.609 9.306 44.689 ;
     RECT  9.216 44.689 9.342 44.753 ;
     RECT  9.324 44.753 9.342 44.789 ;
     RECT  4.896 44.375 5.814 44.875 ;
     RECT  4.896 44.875 5.85 44.923 ;
     RECT  4.896 44.923 6.282 45.023 ;
     RECT  3.96 43.835 3.978 45.115 ;
     RECT  4.896 45.023 5.397 45.115 ;
     RECT  2.304 44.105 3.186 45.301 ;
     RECT  3.96 45.115 5.397 45.301 ;
     RECT  6.264 45.023 6.282 45.301 ;
     RECT  7.02 44.645 8.097 45.301 ;
     RECT  6.264 45.301 8.097 45.341 ;
     RECT  2.268 45.301 5.397 45.389 ;
     RECT  2.304 45.389 5.397 45.455 ;
     RECT  34.488 44.339 73.098 45.571 ;
     RECT  3.96 45.455 5.397 45.599 ;
     RECT  6.408 45.341 8.097 45.841 ;
     RECT  34.2 45.571 73.098 45.931 ;
     RECT  4.644 45.599 5.397 45.959 ;
     RECT  6.408 45.841 8.226 45.959 ;
     RECT  6.84 45.959 8.226 46.139 ;
     RECT  4.716 45.959 5.397 46.171 ;
     RECT  30.852 45.841 30.87 46.237 ;
     RECT  33.624 45.931 73.098 46.265 ;
     RECT  2.304 45.455 3.15 46.345 ;
     RECT  30.78 46.237 30.87 46.409 ;
     RECT  2.304 46.345 3.87 46.459 ;
     RECT  6.84 46.139 6.858 46.499 ;
     RECT  34.2 46.265 73.098 46.769 ;
     RECT  2.268 46.459 3.87 46.877 ;
     RECT  29.415 43.799 29.697 47.047 ;
     RECT  7.815 46.139 8.226 47.083 ;
     RECT  2.304 46.877 3.87 47.191 ;
     RECT  4.716 46.171 6.102 47.191 ;
     RECT  7.815 47.083 8.37 47.191 ;
     RECT  2.304 47.191 6.102 47.281 ;
     RECT  6.948 47.191 6.966 47.281 ;
     RECT  2.304 47.281 6.966 47.309 ;
     RECT  7.74 47.191 8.37 47.309 ;
     RECT  9.144 47.155 9.162 47.309 ;
     RECT  34.776 46.769 73.098 47.309 ;
     RECT  29.415 47.047 29.754 47.489 ;
     RECT  34.815 47.309 73.098 47.615 ;
     RECT  0.54 47.731 0.558 47.933 ;
     RECT  10.515 42.179 10.797 48.001 ;
     RECT  34.815 47.615 70.197 48.091 ;
     RECT  2.304 47.309 6.858 48.127 ;
     RECT  7.815 47.309 8.097 48.127 ;
     RECT  10.515 48.001 10.818 48.263 ;
     RECT  2.304 48.127 8.097 48.379 ;
     RECT  34.776 48.091 70.197 48.389 ;
     RECT  2.304 48.379 8.37 48.461 ;
     RECT  7.524 48.461 8.37 48.541 ;
     RECT  71.496 47.615 73.098 48.731 ;
     RECT  7.524 48.541 8.514 48.839 ;
     RECT  71.64 48.731 73.098 49.073 ;
     RECT  0.54 48.811 0.558 49.085 ;
     RECT  71.64 49.073 72.897 49.109 ;
     RECT  34.815 48.389 70.197 49.243 ;
     RECT  2.304 48.461 6.354 49.279 ;
     RECT  7.524 48.839 8.154 49.279 ;
     RECT  73.908 43.601 73.926 49.307 ;
     RECT  9 49.081 9.018 49.315 ;
     RECT  9 49.315 9.09 49.343 ;
     RECT  2.304 49.279 8.154 49.469 ;
     RECT  9.072 49.343 9.09 49.469 ;
     RECT  3.96 49.469 8.154 49.577 ;
     RECT  2.304 49.469 3.078 49.675 ;
     RECT  21.315 30.479 21.597 49.711 ;
     RECT  21.204 49.711 21.597 49.757 ;
     RECT  22.824 49.723 22.842 49.853 ;
     RECT  30.78 49.723 30.798 49.853 ;
     RECT  3.96 49.577 6.39 49.919 ;
     RECT  7.308 49.577 8.154 50.053 ;
     RECT  30.852 49.981 30.87 50.117 ;
     RECT  7.308 50.053 8.226 50.161 ;
     RECT  2.268 49.675 3.078 50.189 ;
     RECT  9.396 50.089 9.414 50.287 ;
     RECT  34.776 49.243 70.197 50.315 ;
     RECT  7.308 50.161 8.334 50.323 ;
     RECT  2.304 50.189 3.078 50.395 ;
     RECT  4.536 49.919 6.39 50.431 ;
     RECT  7.308 50.323 8.37 50.431 ;
     RECT  68.616 50.315 70.197 50.459 ;
     RECT  2.304 50.395 3.33 50.549 ;
     RECT  9.108 50.287 9.414 50.557 ;
     RECT  0.252 50.491 0.27 50.621 ;
     RECT  4.536 50.431 8.37 50.629 ;
     RECT  9.108 50.557 9.486 50.629 ;
     RECT  4.536 50.629 9.486 50.791 ;
     RECT  4.536 50.791 9.594 50.827 ;
     RECT  2.304 50.549 3.294 50.855 ;
     RECT  10.515 48.263 10.797 50.899 ;
     RECT  4.464 50.827 9.666 50.957 ;
     RECT  4.464 50.957 9.594 50.999 ;
     RECT  10.515 50.899 10.926 51.089 ;
     RECT  4.464 50.999 9.522 51.197 ;
     RECT  4.464 51.197 9.486 51.269 ;
     RECT  34.776 50.315 67.497 51.359 ;
     RECT  68.976 50.459 70.197 51.431 ;
     RECT  68.976 51.431 68.994 51.539 ;
     RECT  4.608 51.269 9.486 52.015 ;
     RECT  0.216 52.075 0.234 52.205 ;
     RECT  34.815 51.359 35.154 52.213 ;
     RECT  2.304 50.855 3.006 52.267 ;
     RECT  26.715 37.319 26.997 52.267 ;
     RECT  4.536 52.015 9.486 52.285 ;
     RECT  4.356 52.285 9.486 52.321 ;
     RECT  10.515 51.089 10.797 52.321 ;
     RECT  21.315 49.757 21.597 52.411 ;
     RECT  26.676 52.267 26.997 52.439 ;
     RECT  14.832 52.267 14.85 52.445 ;
     RECT  30.78 52.267 30.798 52.445 ;
     RECT  21.204 52.411 21.597 52.448 ;
     RECT  10.515 52.321 10.818 52.519 ;
     RECT  3.996 52.321 9.486 52.591 ;
     RECT  10.515 52.519 10.926 52.709 ;
     RECT  34.776 52.213 35.154 52.709 ;
     RECT  34.812 52.709 35.154 52.781 ;
     RECT  2.304 52.267 3.078 52.789 ;
     RECT  3.924 52.591 9.486 52.789 ;
     RECT  36.288 51.359 67.497 52.889 ;
     RECT  72.072 49.109 72.897 52.889 ;
     RECT  2.304 52.789 9.486 52.979 ;
     RECT  34.815 52.781 35.154 53.035 ;
     RECT  34.815 53.035 35.514 53.671 ;
     RECT  34.776 53.671 35.514 53.761 ;
     RECT  36.288 52.889 66.366 53.761 ;
     RECT  2.304 52.979 3.582 53.905 ;
     RECT  4.356 52.979 9.486 53.905 ;
     RECT  34.776 53.761 66.366 54.103 ;
     RECT  34.452 54.103 66.366 54.329 ;
     RECT  34.452 54.329 37.797 54.409 ;
     RECT  10.515 52.709 10.797 54.445 ;
     RECT  2.304 53.905 9.486 54.523 ;
     RECT  2.268 54.523 9.486 54.599 ;
     RECT  33.876 54.409 37.797 54.607 ;
     RECT  10.515 54.445 10.818 54.985 ;
     RECT  10.515 54.985 10.854 55.139 ;
     RECT  38.628 54.329 66.366 55.139 ;
     RECT  2.268 54.599 3.294 55.175 ;
     RECT  2.304 55.175 3.294 55.561 ;
     RECT  38.628 55.139 62.442 55.679 ;
     RECT  2.304 55.561 3.33 55.687 ;
     RECT  4.176 54.599 9.486 55.687 ;
     RECT  2.304 55.687 9.486 56.219 ;
     RECT  0.252 56.443 0.27 56.573 ;
     RECT  2.304 56.219 2.862 57.001 ;
     RECT  3.6 56.219 9.486 57.001 ;
     RECT  0.216 57.211 0.234 57.341 ;
     RECT  38.628 55.679 62.406 57.343 ;
     RECT  10.515 55.139 10.797 57.451 ;
     RECT  38.628 57.343 62.478 57.569 ;
     RECT  63.216 55.139 66.366 57.569 ;
     RECT  10.515 57.451 10.854 57.991 ;
     RECT  2.304 57.001 9.486 58.363 ;
     RECT  2.268 58.363 9.486 58.523 ;
     RECT  2.304 58.523 9.486 58.649 ;
     RECT  10.515 57.991 10.926 58.649 ;
     RECT  32.115 44.483 32.397 58.963 ;
     RECT  33.336 54.607 37.797 58.963 ;
     RECT  32.115 58.963 37.797 58.991 ;
     RECT  0.216 58.693 0.234 59.357 ;
     RECT  2.304 58.649 3.258 59.755 ;
     RECT  0.252 59.659 0.27 59.789 ;
     RECT  2.304 59.755 3.33 60.115 ;
     RECT  4.176 58.649 9.486 60.115 ;
     RECT  38.628 57.569 62.37 61.079 ;
     RECT  38.628 61.079 62.226 61.349 ;
     RECT  2.304 60.115 9.486 61.579 ;
     RECT  2.268 61.579 9.486 61.619 ;
     RECT  0.216 61.963 0.234 62.093 ;
     RECT  2.304 61.619 9.486 62.339 ;
     RECT  2.304 62.339 4.194 62.573 ;
     RECT  63.36 57.569 66.366 63.005 ;
     RECT  3.528 62.573 4.194 63.085 ;
     RECT  5.004 62.339 9.486 63.085 ;
     RECT  2.304 62.573 2.697 63.481 ;
     RECT  3.528 63.085 9.486 63.481 ;
     RECT  2.304 63.481 9.486 63.643 ;
     RECT  2.268 63.643 9.486 63.689 ;
     RECT  2.304 63.689 9.486 63.815 ;
     RECT  3.672 63.815 9.486 63.851 ;
     RECT  3.996 63.851 9.486 63.887 ;
     RECT  0.54 63.589 0.558 64.013 ;
     RECT  38.628 61.349 62.154 64.049 ;
     RECT  38.628 64.049 49.338 64.319 ;
     RECT  2.304 63.815 2.898 64.705 ;
     RECT  0.252 64.795 0.27 64.925 ;
     RECT  2.304 64.705 3.366 64.939 ;
     RECT  50.544 64.049 62.154 65.129 ;
     RECT  2.304 64.939 3.438 65.272 ;
     RECT  49.32 64.319 49.338 65.479 ;
     RECT  50.544 65.129 62.097 65.563 ;
     RECT  4.176 63.887 9.486 65.641 ;
     RECT  10.515 58.649 10.797 65.749 ;
     RECT  49.32 65.479 49.626 65.777 ;
     RECT  10.515 65.749 10.818 65.849 ;
     RECT  2.268 65.272 3.438 65.911 ;
     RECT  4.176 65.641 9.522 65.911 ;
     RECT  2.268 65.911 9.522 65.933 ;
     RECT  2.304 65.933 9.522 65.939 ;
     RECT  50.436 65.563 62.097 66.091 ;
     RECT  50.184 66.091 62.097 66.749 ;
     RECT  10.515 65.849 10.797 66.757 ;
     RECT  50.256 66.749 62.097 66.785 ;
     RECT  2.304 65.939 9.486 67.019 ;
     RECT  50.544 66.785 62.097 67.289 ;
     RECT  52.236 67.289 62.097 67.829 ;
     RECT  10.515 66.757 10.854 67.909 ;
     RECT  2.304 67.019 3.186 68.071 ;
     RECT  10.515 67.909 10.926 68.099 ;
     RECT  52.92 67.829 62.097 68.099 ;
     RECT  2.304 68.071 3.438 68.179 ;
     RECT  4.176 67.019 9.486 68.179 ;
     RECT  53.1 68.099 62.097 68.639 ;
     RECT  0.252 68.779 0.27 68.957 ;
     RECT  2.304 68.179 9.486 69.115 ;
     RECT  53.388 68.639 62.097 69.179 ;
     RECT  2.268 69.115 9.486 69.287 ;
     RECT  53.604 69.179 62.097 69.449 ;
     RECT  53.604 69.449 53.997 69.719 ;
     RECT  10.515 68.099 10.797 69.871 ;
     RECT  52.452 69.493 52.47 69.899 ;
     RECT  10.515 69.871 10.854 69.989 ;
     RECT  0.252 69.931 0.27 70.061 ;
     RECT  2.304 69.287 9.486 70.061 ;
     RECT  2.304 70.061 3.33 70.219 ;
     RECT  12.24 60.115 12.258 70.375 ;
     RECT  13.215 23.585 13.497 70.375 ;
     RECT  2.268 70.219 3.33 70.529 ;
     RECT  2.268 70.529 2.898 70.565 ;
     RECT  54.72 69.449 62.097 71.069 ;
     RECT  2.304 70.565 2.898 71.105 ;
     RECT  2.34 71.105 2.898 71.491 ;
     RECT  4.176 70.061 9.486 71.491 ;
     RECT  0.216 71.515 0.234 71.645 ;
     RECT  54.9 71.069 62.097 71.645 ;
     RECT  2.34 71.491 9.486 71.851 ;
     RECT  55.908 71.645 62.097 71.879 ;
     RECT  54.9 71.645 54.918 71.887 ;
     RECT  54.72 71.887 54.918 71.987 ;
     RECT  2.304 71.851 9.486 72.149 ;
     RECT  56.016 71.879 62.097 72.257 ;
     RECT  2.304 72.149 3.438 72.419 ;
     RECT  54.792 71.987 54.918 72.419 ;
     RECT  4.176 72.149 9.486 73.039 ;
     RECT  54.792 72.419 54.882 73.229 ;
     RECT  2.304 72.419 3.114 73.345 ;
     RECT  4.032 73.039 9.486 73.345 ;
     RECT  54.792 73.229 54.81 73.381 ;
     RECT  54.72 73.381 54.81 73.409 ;
     RECT  56.16 72.257 62.097 73.769 ;
     RECT  54.72 73.409 54.738 73.841 ;
     RECT  56.16 73.769 56.898 73.885 ;
     RECT  56.016 73.885 56.898 74.039 ;
     RECT  56.016 74.039 56.697 74.075 ;
     RECT  2.304 73.345 9.486 74.893 ;
     RECT  57.672 73.769 62.097 74.965 ;
     RECT  2.304 74.893 9.522 75.119 ;
     RECT  3.96 75.119 9.522 75.155 ;
     RECT  57.42 74.965 62.097 75.191 ;
     RECT  57.672 75.191 62.097 75.389 ;
     RECT  2.304 75.119 3.078 75.461 ;
     RECT  2.304 75.461 2.754 75.532 ;
     RECT  57.672 75.389 57.69 75.659 ;
     RECT  2.268 75.532 2.754 75.695 ;
     RECT  19.944 75.667 19.962 75.839 ;
     RECT  2.304 75.695 2.754 75.965 ;
     RECT  54.72 75.901 54.738 76.001 ;
     RECT  3.96 75.155 9.486 76.081 ;
     RECT  10.515 69.989 10.797 76.081 ;
     RECT  10.515 76.081 10.854 76.199 ;
     RECT  3.708 76.081 9.486 76.235 ;
     RECT  2.34 75.965 2.754 76.267 ;
     RECT  0.216 76.171 0.234 76.3 ;
     RECT  58.932 75.389 62.097 76.363 ;
     RECT  54.792 76.207 54.81 76.379 ;
     RECT  0.216 76.3 0.27 76.397 ;
     RECT  58.32 76.363 62.097 76.469 ;
     RECT  58.932 76.469 62.097 76.739 ;
     RECT  2.34 76.267 2.898 76.747 ;
     RECT  0.216 76.397 0.234 76.781 ;
     RECT  2.34 76.747 3.186 76.843 ;
     RECT  2.304 76.843 3.186 77.045 ;
     RECT  4.176 76.235 9.486 77.161 ;
     RECT  3.78 77.161 9.486 77.459 ;
     RECT  54.72 76.747 54.738 77.621 ;
     RECT  54.792 77.665 54.81 77.855 ;
     RECT  2.304 77.045 2.898 77.899 ;
     RECT  59.115 76.739 62.097 78.089 ;
     RECT  2.304 77.899 3.438 78.331 ;
     RECT  4.176 77.459 9.486 78.331 ;
     RECT  60.336 78.089 62.097 78.359 ;
     RECT  59.115 78.089 59.397 78.367 ;
     RECT  58.788 78.367 59.397 78.539 ;
     RECT  2.304 78.331 9.486 78.629 ;
     RECT  60.552 78.359 60.57 78.665 ;
     RECT  12.24 70.375 13.497 78.871 ;
     RECT  4.176 78.629 9.486 78.943 ;
     RECT  10.515 76.199 10.797 78.943 ;
     RECT  11.7 78.871 13.497 78.989 ;
     RECT  2.304 78.629 3.078 79.169 ;
     RECT  0.216 79.177 0.234 79.277 ;
     RECT  2.304 79.169 2.97 79.387 ;
     RECT  61.308 78.359 62.097 79.511 ;
     RECT  4.176 78.943 10.797 79.555 ;
     RECT  2.268 79.387 2.97 79.583 ;
     RECT  4.176 79.555 11.106 79.717 ;
     RECT  3.96 79.717 11.106 80.023 ;
     RECT  3.744 80.023 11.106 80.059 ;
     RECT  12.24 78.989 13.497 80.059 ;
     RECT  2.304 79.583 2.97 80.131 ;
     RECT  3.744 80.059 13.497 80.131 ;
     RECT  64.116 63.005 66.366 80.159 ;
     RECT  64.116 80.159 65.538 80.663 ;
     RECT  38.628 64.319 48.597 81.131 ;
     RECT  66.348 80.159 66.366 81.239 ;
     RECT  2.304 80.131 13.497 81.329 ;
     RECT  4.104 81.329 13.497 81.751 ;
     RECT  63.36 63.005 63.378 81.779 ;
     RECT  4.104 81.751 13.698 82.147 ;
     RECT  3.744 82.147 13.698 82.183 ;
     RECT  3.708 82.183 13.698 82.255 ;
     RECT  2.304 81.329 2.697 82.291 ;
     RECT  2.304 82.291 2.862 82.459 ;
     RECT  3.6 82.255 13.698 82.459 ;
     RECT  49.32 65.777 49.338 82.517 ;
     RECT  45.288 81.131 48.597 82.949 ;
     RECT  2.304 82.459 13.698 82.957 ;
     RECT  2.304 82.957 13.95 83.057 ;
     RECT  2.304 83.057 3.222 83.219 ;
     RECT  4.32 83.057 13.95 83.525 ;
     RECT  4.5 83.525 13.95 83.759 ;
     RECT  2.304 83.219 2.934 84.001 ;
     RECT  2.304 84.001 3.294 84.109 ;
     RECT  64.515 80.663 65.538 84.209 ;
     RECT  2.304 84.109 3.654 84.331 ;
     RECT  15.915 29.093 16.254 84.379 ;
     RECT  2.304 84.331 3.762 84.451 ;
     RECT  2.304 84.451 3.942 84.811 ;
     RECT  4.716 83.759 13.95 84.811 ;
     RECT  15.915 84.379 16.506 84.811 ;
     RECT  15.804 84.811 16.506 84.839 ;
     RECT  15.804 84.839 16.254 84.941 ;
     RECT  2.304 84.811 13.95 84.955 ;
     RECT  38.628 81.131 44.478 85.217 ;
     RECT  2.304 84.955 14.13 85.339 ;
     RECT  2.268 85.339 14.13 85.379 ;
     RECT  65.52 84.209 65.538 85.523 ;
     RECT  45.288 82.949 46.962 85.559 ;
     RECT  2.268 85.379 13.95 85.919 ;
     RECT  15.915 84.941 16.254 86.059 ;
     RECT  15.915 86.059 16.83 86.467 ;
     RECT  2.268 85.919 2.862 86.495 ;
     RECT  41.292 85.217 44.478 86.495 ;
     RECT  14.832 86.467 14.85 86.567 ;
     RECT  15.915 86.467 16.902 86.567 ;
     RECT  2.304 86.495 2.862 86.701 ;
     RECT  3.636 85.919 13.95 86.701 ;
     RECT  17.748 86.635 17.766 86.731 ;
     RECT  17.568 86.731 17.766 86.999 ;
     RECT  42.3 86.495 44.478 87.413 ;
     RECT  0.252 87.403 0.27 87.773 ;
     RECT  50.544 67.289 51.297 87.989 ;
     RECT  46.944 85.559 46.962 88.115 ;
     RECT  38.628 85.217 40.497 88.151 ;
     RECT  2.304 86.701 13.95 88.349 ;
     RECT  42.3 87.413 43.65 88.655 ;
     RECT  36.36 58.991 37.797 88.691 ;
     RECT  45.288 85.559 45.897 88.763 ;
     RECT  4.032 88.349 13.95 88.889 ;
     RECT  41.292 86.495 41.526 89.033 ;
     RECT  44.46 87.413 44.478 89.231 ;
     RECT  2.304 88.349 3.222 89.275 ;
     RECT  2.304 89.275 3.294 89.545 ;
     RECT  4.032 88.889 8.097 89.545 ;
     RECT  0.216 89.437 0.234 89.549 ;
     RECT  2.304 89.545 8.097 89.659 ;
     RECT  42.3 88.655 43.197 89.771 ;
     RECT  2.268 89.659 8.097 89.807 ;
     RECT  8.82 88.889 13.95 89.969 ;
     RECT  8.82 89.969 13.497 90.419 ;
     RECT  32.115 58.991 35.622 90.887 ;
     RECT  42.624 89.771 43.197 90.923 ;
     RECT  8.82 90.419 12.258 90.959 ;
     RECT  2.304 89.807 8.097 91.121 ;
     RECT  2.304 91.121 2.862 91.193 ;
     RECT  41.292 89.033 41.31 91.319 ;
     RECT  3.816 91.121 8.097 91.499 ;
     RECT  38.628 88.151 39.366 91.499 ;
     RECT  3.888 91.499 8.097 91.517 ;
     RECT  8.82 90.959 11.682 91.589 ;
     RECT  4.5 91.517 8.097 91.867 ;
     RECT  8.82 91.589 11.106 91.867 ;
     RECT  2.304 91.193 2.826 91.931 ;
     RECT  33.336 90.887 35.622 92.039 ;
     RECT  4.5 91.867 11.106 92.371 ;
     RECT  3.996 92.371 11.106 92.669 ;
     RECT  2.304 91.931 2.79 92.779 ;
     RECT  0.252 92.779 0.27 92.909 ;
     RECT  3.996 92.669 10.818 93.209 ;
     RECT  36.36 88.691 36.774 93.245 ;
     RECT  7.815 93.209 9.126 93.251 ;
     RECT  2.304 92.779 3.006 93.253 ;
     RECT  3.996 93.209 7.074 93.253 ;
     RECT  9.936 93.209 10.818 93.353 ;
     RECT  7.815 93.251 8.37 93.389 ;
     RECT  33.876 92.039 35.622 93.479 ;
     RECT  2.304 93.253 7.074 93.515 ;
     RECT  38.628 91.499 39.042 93.857 ;
     RECT  9.108 93.251 9.126 94.019 ;
     RECT  34.452 93.479 35.622 94.289 ;
     RECT  7.815 93.389 8.097 94.369 ;
     RECT  9.936 93.353 10.797 94.433 ;
     RECT  2.304 93.515 6.858 94.441 ;
     RECT  10.515 94.433 10.797 94.441 ;
     RECT  2.304 94.441 6.93 94.469 ;
     RECT  34.452 94.289 35.097 94.469 ;
     RECT  4.428 94.469 6.93 94.559 ;
     RECT  7.815 94.369 8.514 94.559 ;
     RECT  9.36 94.441 9.378 94.559 ;
     RECT  36.756 93.245 36.774 94.559 ;
     RECT  7.815 94.559 8.37 94.595 ;
     RECT  4.428 94.559 6.282 94.631 ;
     RECT  10.515 94.441 10.854 94.631 ;
     RECT  2.304 94.469 3.366 94.739 ;
     RECT  0.216 94.603 0.234 94.829 ;
     RECT  4.428 94.631 5.994 94.829 ;
     RECT  4.428 94.829 5.598 95.099 ;
     RECT  2.304 94.739 3.294 95.135 ;
     RECT  2.34 95.135 3.294 95.369 ;
     RECT  2.34 95.369 2.697 95.405 ;
     RECT  37.515 88.691 37.797 95.647 ;
     RECT  38.628 93.857 38.646 95.647 ;
     RECT  37.515 95.647 38.646 95.693 ;
     RECT  15.915 86.567 16.254 96.061 ;
     RECT  39.42 95.791 39.438 96.251 ;
     RECT  38.808 96.331 38.934 96.485 ;
     RECT  15.915 96.061 16.794 96.529 ;
     RECT  15.915 96.529 16.902 96.629 ;
     RECT  2.415 95.405 2.697 96.947 ;
     RECT  5.115 95.099 5.397 96.947 ;
     RECT  7.815 94.595 8.097 96.947 ;
     RECT  10.515 94.631 10.797 96.947 ;
     RECT  13.215 90.419 13.497 96.947 ;
     RECT  18.615 31.685 18.897 96.947 ;
     RECT  21.315 52.448 21.597 96.947 ;
     RECT  24.015 34.349 24.297 96.947 ;
     RECT  26.715 52.439 26.997 96.947 ;
     RECT  29.415 47.489 29.697 96.947 ;
     RECT  32.115 90.887 32.397 96.947 ;
     RECT  34.815 94.469 35.097 96.947 ;
     RECT  37.515 95.693 37.797 96.947 ;
     RECT  40.215 88.151 40.497 96.947 ;
     RECT  42.915 90.923 43.197 96.947 ;
     RECT  45.615 88.763 45.897 96.947 ;
     RECT  48.315 82.949 48.597 96.947 ;
     RECT  51.015 87.989 51.297 96.947 ;
     RECT  53.715 69.719 53.997 96.947 ;
     RECT  56.415 74.075 56.697 96.947 ;
     RECT  59.115 78.539 59.397 96.947 ;
     RECT  61.815 79.511 62.097 96.947 ;
     RECT  64.515 84.209 64.797 96.947 ;
     RECT  67.215 52.889 67.497 96.947 ;
     RECT  69.915 51.431 70.197 96.947 ;
     RECT  72.615 52.889 72.897 96.947 ;
     RECT  75.315 4.919 75.597 96.947 ;
     RECT  15.915 96.629 16.722 96.961 ;
     RECT  15.84 96.961 16.722 97.133 ;
     RECT  2.415 96.947 2.505 97.217 ;
     RECT  5.115 96.947 5.205 97.217 ;
     RECT  7.815 96.947 7.905 97.217 ;
     RECT  10.515 96.947 10.605 97.217 ;
     RECT  13.215 96.947 13.305 97.217 ;
     RECT  15.84 97.133 16.005 97.217 ;
     RECT  18.615 96.947 18.705 97.217 ;
     RECT  21.315 96.947 21.405 97.217 ;
     RECT  24.015 96.947 24.105 97.217 ;
     RECT  26.715 96.947 26.805 97.217 ;
     RECT  29.415 96.947 29.505 97.217 ;
     RECT  32.115 96.947 32.205 97.217 ;
     RECT  34.815 96.947 34.905 97.217 ;
     RECT  37.515 96.947 37.605 97.217 ;
     RECT  40.215 96.947 40.305 97.217 ;
     RECT  42.915 96.947 43.005 97.217 ;
     RECT  45.615 96.947 45.705 97.217 ;
     RECT  48.315 96.947 48.405 97.217 ;
     RECT  51.015 96.947 51.105 97.217 ;
     RECT  53.715 96.947 53.805 97.217 ;
     RECT  56.415 96.947 56.505 97.217 ;
     RECT  59.115 96.947 59.205 97.217 ;
     RECT  61.815 96.947 62.01 97.217 ;
     RECT  64.515 96.947 64.605 97.217 ;
     RECT  67.215 96.947 67.305 97.217 ;
     RECT  69.915 96.947 70.005 97.217 ;
     RECT  72.615 96.947 72.705 97.217 ;
     RECT  75.315 96.947 75.405 97.217 ;
     RECT  61.92 97.217 62.01 97.295 ;
     RECT  38.916 96.485 38.934 98.045 ;
    LAYER M4 ;
     RECT  0.156 4.416 2.408 95.016 ;
     RECT  2.408 2.148 2.512 97.212 ;
     RECT  2.512 2.418 2.704 96.942 ;
     RECT  2.704 41.904 2.729 44.424 ;
     RECT  2.704 17.376 2.765 17.448 ;
     RECT  2.704 19.296 2.765 19.848 ;
     RECT  2.704 31.872 2.765 32.04 ;
     RECT  2.704 33.552 2.765 34.776 ;
     RECT  2.704 36.816 2.765 40.872 ;
     RECT  2.729 43.92 2.765 44.424 ;
     RECT  2.704 48.72 2.765 49.56 ;
     RECT  2.704 52.176 2.765 53.592 ;
     RECT  2.704 54.672 2.765 57.864 ;
     RECT  2.704 68.16 2.765 71.736 ;
     RECT  2.704 76.032 2.765 78.936 ;
     RECT  2.704 80.016 2.765 80.856 ;
     RECT  2.704 84.384 2.765 87.672 ;
     RECT  2.704 92.256 2.765 93.048 ;
     RECT  2.765 49.536 2.801 49.56 ;
     RECT  2.765 53.568 2.801 53.592 ;
     RECT  2.765 76.176 2.801 78.936 ;
     RECT  2.765 92.256 2.801 92.808 ;
     RECT  2.704 6.672 2.837 8.568 ;
     RECT  2.704 24.144 2.837 24.168 ;
     RECT  2.704 47.616 2.837 47.64 ;
     RECT  2.765 68.16 2.837 68.952 ;
     RECT  2.801 78.912 2.837 78.936 ;
     RECT  2.765 85.2 2.837 85.992 ;
     RECT  2.704 89.184 2.837 90.36 ;
     RECT  2.704 94.032 2.837 94.056 ;
     RECT  2.765 19.296 2.873 19.368 ;
     RECT  2.704 20.928 2.873 20.952 ;
     RECT  2.704 28.416 2.873 28.44 ;
     RECT  2.765 52.176 2.873 52.296 ;
     RECT  2.765 55.776 2.873 57.864 ;
     RECT  2.704 59.76 2.873 60.648 ;
     RECT  2.704 61.968 2.873 61.992 ;
     RECT  2.704 26.112 2.909 26.136 ;
     RECT  2.704 29.568 2.909 30.6 ;
     RECT  2.765 44.352 2.909 44.424 ;
     RECT  2.704 50.592 2.909 51.144 ;
     RECT  2.704 64.32 2.909 64.92 ;
     RECT  2.765 70.032 2.909 70.584 ;
     RECT  2.801 76.176 2.909 77.352 ;
     RECT  2.765 87.12 2.909 87.672 ;
     RECT  2.704 14.064 2.945 16.392 ;
     RECT  2.765 17.376 2.981 17.4 ;
     RECT  2.704 45.504 2.981 45.528 ;
     RECT  2.704 66.048 2.981 66.072 ;
     RECT  2.765 80.832 2.981 80.856 ;
     RECT  2.837 85.2 2.981 85.224 ;
     RECT  2.909 29.568 3.017 30.072 ;
     RECT  2.765 40.368 3.017 40.872 ;
     RECT  2.909 50.592 3.017 50.664 ;
     RECT  2.909 87.12 3.017 87.576 ;
     RECT  2.837 90 3.017 90.36 ;
     RECT  2.801 92.784 3.017 92.808 ;
     RECT  2.765 33.552 3.089 34.152 ;
     RECT  2.873 52.272 3.089 52.296 ;
     RECT  2.704 72.816 3.089 72.84 ;
     RECT  2.873 19.296 3.125 19.32 ;
     RECT  2.765 54.672 3.125 54.696 ;
     RECT  2.873 55.776 3.125 55.8 ;
     RECT  2.873 59.76 3.125 59.832 ;
     RECT  2.909 70.032 3.125 70.056 ;
     RECT  2.909 44.352 3.197 44.376 ;
     RECT  2.873 57.312 3.197 57.864 ;
     RECT  2.909 76.176 3.197 76.776 ;
     RECT  3.017 87.552 3.197 87.576 ;
     RECT  3.017 90 3.197 90.024 ;
     RECT  2.765 71.568 3.233 71.736 ;
     RECT  2.704 82.272 3.233 83.208 ;
     RECT  3.017 29.568 3.305 29.592 ;
     RECT  3.089 34.128 3.305 34.152 ;
     RECT  3.017 40.368 3.305 40.392 ;
     RECT  2.729 41.904 3.305 42.744 ;
     RECT  3.017 50.592 3.305 50.616 ;
     RECT  2.837 68.928 3.305 68.952 ;
     RECT  3.233 82.272 3.305 82.488 ;
     RECT  3.125 59.76 3.341 59.784 ;
     RECT  2.765 36.816 3.413 37.608 ;
     RECT  2.837 6.816 3.443 8.568 ;
     RECT  2.704 5.616 3.635 5.64 ;
     RECT  3.74 12.96 3.827 12.984 ;
     RECT  3.443 8.544 3.913 8.568 ;
     RECT  3.305 41.904 3.923 41.928 ;
     RECT  2.945 14.064 3.973 16.008 ;
     RECT  3.877 20.784 3.973 20.808 ;
     RECT  3.877 18.624 4.019 18.648 ;
     RECT  3.973 20.784 4.019 21.096 ;
     RECT  3.233 71.568 4.025 71.592 ;
     RECT  3.973 14.064 4.057 16.536 ;
     RECT  3.197 76.176 4.201 76.2 ;
     RECT  2.765 39.312 4.237 39.336 ;
     RECT  4.057 13.68 4.381 16.536 ;
     RECT  3.443 6.816 4.453 7.224 ;
     RECT  3.913 8.544 4.453 8.76 ;
     RECT  4.237 39.312 4.453 39.48 ;
     RECT  4.201 76.128 4.453 76.2 ;
     RECT  4.237 78.048 4.453 78.072 ;
     RECT  3.877 85.872 4.453 85.896 ;
     RECT  3.769 3.552 4.501 3.576 ;
     RECT  3.877 43.248 4.508 43.272 ;
     RECT  4.381 13.68 4.525 16.584 ;
     RECT  4.453 76.128 4.549 78.072 ;
     RECT  3.877 24 4.561 24.024 ;
     RECT  4.453 85.872 4.561 86.616 ;
     RECT  4.381 2.256 4.597 2.28 ;
     RECT  3.197 57.84 4.597 57.864 ;
     RECT  4.316 0.144 4.643 0.168 ;
     RECT  4.561 85.392 4.645 86.616 ;
     RECT  4.093 45.12 4.693 45.144 ;
     RECT  4.645 85.392 4.7 86.904 ;
     RECT  3.877 91.488 4.705 91.512 ;
     RECT  4.453 6.816 4.741 8.76 ;
     RECT  4.237 65.52 4.741 65.544 ;
     RECT  4.129 89.424 4.741 89.448 ;
     RECT  4.705 90.864 4.741 91.512 ;
     RECT  4.705 0.192 4.957 0.216 ;
     RECT  4.597 1.728 4.957 2.28 ;
     RECT  3.733 84.336 4.981 84.36 ;
     RECT  4.501 3.552 4.993 4.2 ;
     RECT  2.704 10.56 5.029 11.976 ;
     RECT  4.957 0.192 5.041 2.28 ;
     RECT  4.993 3.312 5.101 4.2 ;
     RECT  5.041 1.728 5.108 2.28 ;
     RECT  5.101 3.312 5.108 5.016 ;
     RECT  4.741 6.096 5.108 8.76 ;
     RECT  5.029 10.176 5.108 11.976 ;
     RECT  4.525 13.68 5.108 17.112 ;
     RECT  4.777 19.344 5.108 19.368 ;
     RECT  4.019 21.072 5.108 21.096 ;
     RECT  4.561 23.28 5.108 24.024 ;
     RECT  4.561 26.64 5.108 26.664 ;
     RECT  4.525 28.944 5.108 28.968 ;
     RECT  4.093 30.576 5.108 30.6 ;
     RECT  2.765 31.872 5.108 31.896 ;
     RECT  3.877 33.072 5.108 33.096 ;
     RECT  4.453 35.856 5.108 35.88 ;
     RECT  4.453 37.008 5.108 37.032 ;
     RECT  4.453 38.64 5.108 39.48 ;
     RECT  5.029 40.56 5.108 40.584 ;
     RECT  4.508 42.192 5.108 43.272 ;
     RECT  4.693 44.304 5.108 45.144 ;
     RECT  5.101 47.616 5.108 47.64 ;
     RECT  4.357 49.584 5.108 49.608 ;
     RECT  4.597 57.312 5.108 57.864 ;
     RECT  4.741 64.704 5.108 65.544 ;
     RECT  4.381 67.296 5.108 67.32 ;
     RECT  4.525 69.504 5.108 69.528 ;
     RECT  4.741 72.144 5.108 72.168 ;
     RECT  2.704 74.16 5.108 74.184 ;
     RECT  4.549 75.792 5.108 78.072 ;
     RECT  4.525 81.072 5.108 81.096 ;
     RECT  3.305 82.272 5.108 82.296 ;
     RECT  4.981 83.568 5.108 84.36 ;
     RECT  4.7 85.392 5.108 87.24 ;
     RECT  4.525 88.32 5.108 88.344 ;
     RECT  4.741 89.424 5.108 91.512 ;
     RECT  5.108 1.728 5.212 97.212 ;
     RECT  5.212 1.728 5.404 96.942 ;
     RECT  5.404 80.352 5.501 81.096 ;
     RECT  5.404 7.92 5.555 8.76 ;
     RECT  5.404 28.896 5.555 29.88 ;
     RECT  5.404 57.312 5.555 57.576 ;
     RECT  5.404 64.32 5.555 64.728 ;
     RECT  5.404 13.68 5.573 18.168 ;
     RECT  5.555 64.704 5.645 64.728 ;
     RECT  5.404 76.176 5.681 77.16 ;
     RECT  5.681 76.176 5.699 76.296 ;
     RECT  5.404 84.672 5.717 87.768 ;
     RECT  5.041 0.192 5.753 0.6 ;
     RECT  5.404 54.528 5.753 55.032 ;
     RECT  5.404 69.216 5.753 70.104 ;
     RECT  5.717 87.744 5.789 87.768 ;
     RECT  5.404 1.728 5.825 6.792 ;
     RECT  5.573 17.664 5.825 18.168 ;
     RECT  5.404 26.64 5.825 27.912 ;
     RECT  5.404 67.44 5.825 67.848 ;
     RECT  5.404 59.808 5.833 59.832 ;
     RECT  5.404 61.056 5.836 61.56 ;
     RECT  5.404 10.176 5.861 12.504 ;
     RECT  5.404 44.88 5.861 46.2 ;
     RECT  5.404 23.232 5.897 24.312 ;
     RECT  5.836 61.536 5.897 61.56 ;
     RECT  5.404 33.552 5.969 35.448 ;
     RECT  5.717 84.672 5.969 86.76 ;
     RECT  5.404 72.144 6.041 72.168 ;
     RECT  5.404 73.344 6.041 73.944 ;
     RECT  5.404 94.08 6.041 94.104 ;
     RECT  5.969 33.552 6.077 33.576 ;
     RECT  5.753 69.552 6.113 70.104 ;
     RECT  5.969 84.912 6.113 86.76 ;
     RECT  5.404 40.56 6.149 40.584 ;
     RECT  5.404 75.072 6.185 75.144 ;
     RECT  5.555 28.896 6.257 29.688 ;
     RECT  5.861 45.024 6.275 46.2 ;
     RECT  5.825 27.168 6.293 27.912 ;
     RECT  6.275 45.024 6.316 45.336 ;
     RECT  5.861 10.8 6.323 12.504 ;
     RECT  5.555 7.92 6.329 8.52 ;
     RECT  6.257 29.04 6.401 29.688 ;
     RECT  6.113 69.984 6.421 70.104 ;
     RECT  5.404 82.656 6.437 83.592 ;
     RECT  5.825 6.576 6.469 6.792 ;
     RECT  5.573 13.68 6.469 16.584 ;
     RECT  6.293 27.168 6.545 27.192 ;
     RECT  5.753 55.008 6.563 55.032 ;
     RECT  5.501 80.352 6.577 80.376 ;
     RECT  5.404 47.616 6.62 47.88 ;
     RECT  6.505 65.712 6.721 65.736 ;
     RECT  5.404 78.624 6.725 78.984 ;
     RECT  5.753 0.192 6.733 0.552 ;
     RECT  5.555 57.552 6.761 57.576 ;
     RECT  6.421 69.984 6.761 70.152 ;
     RECT  6.041 73.344 6.761 73.368 ;
     RECT  6.757 9.168 6.829 9.192 ;
     RECT  5.404 50.784 6.829 50.808 ;
     RECT  6.113 86.496 6.829 86.76 ;
     RECT  6.685 87.792 6.829 87.816 ;
     RECT  5.404 49.488 6.851 49.8 ;
     RECT  6.829 50.784 6.851 50.856 ;
     RECT  6.721 42.192 6.853 42.216 ;
     RECT  5.404 89.136 6.865 89.16 ;
     RECT  5.404 38.688 6.868 38.76 ;
     RECT  6.733 0.288 6.901 0.552 ;
     RECT  5.825 1.728 6.901 5.208 ;
     RECT  6.851 49.488 6.901 50.856 ;
     RECT  6.517 51.888 6.901 51.912 ;
     RECT  6.901 0.288 6.937 5.208 ;
     RECT  6.469 6.576 6.937 7.656 ;
     RECT  6.721 65.664 7.004 65.736 ;
     RECT  5.969 35.424 7.045 35.448 ;
     RECT  5.897 23.856 7.093 23.88 ;
     RECT  6.829 61.152 7.117 61.176 ;
     RECT  6.469 13.584 7.153 16.584 ;
     RECT  6.901 49.488 7.153 51.912 ;
     RECT  5.825 67.44 7.153 67.464 ;
     RECT  6.853 82.224 7.153 82.248 ;
     RECT  6.937 0.288 7.193 7.656 ;
     RECT  7.093 23.856 7.225 25.416 ;
     RECT  6.901 58.656 7.237 58.68 ;
     RECT  6.761 69.984 7.369 70.008 ;
     RECT  6.437 83.232 7.369 83.592 ;
     RECT  6.113 84.912 7.369 85.416 ;
     RECT  5.404 21.888 7.405 22.2 ;
     RECT  7.369 69.312 7.429 70.008 ;
     RECT  5.825 18.144 7.469 18.168 ;
     RECT  7.469 18.144 7.477 18.84 ;
     RECT  7.004 43.728 7.513 43.752 ;
     RECT  6.316 45.024 7.513 45.048 ;
     RECT  6.323 10.8 7.532 11.448 ;
     RECT  7.532 10.56 7.585 11.448 ;
     RECT  6.323 12.48 7.585 12.504 ;
     RECT  6.793 30.768 7.649 30.792 ;
     RECT  5.404 31.776 7.649 31.8 ;
     RECT  7.193 1.728 7.808 7.656 ;
     RECT  6.829 9.168 7.808 9.336 ;
     RECT  7.585 10.56 7.808 12.504 ;
     RECT  7.153 13.584 7.808 17.112 ;
     RECT  7.477 18.096 7.808 18.84 ;
     RECT  6.685 20.544 7.808 20.568 ;
     RECT  7.405 21.888 7.808 22.248 ;
     RECT  7.225 23.856 7.808 25.8 ;
     RECT  6.401 29.04 7.808 29.496 ;
     RECT  7.649 30.768 7.808 31.8 ;
     RECT  6.956 33.216 7.808 33.24 ;
     RECT  7.045 34.896 7.808 35.448 ;
     RECT  7.004 36.48 7.808 36.504 ;
     RECT  6.868 38.64 7.808 38.76 ;
     RECT  6.853 41.376 7.808 42.216 ;
     RECT  7.513 43.728 7.808 45.048 ;
     RECT  6.62 47.616 7.808 48.456 ;
     RECT  7.153 49.488 7.808 52.2 ;
     RECT  5.404 53.376 7.808 53.4 ;
     RECT  7.153 56.496 7.808 56.52 ;
     RECT  7.237 58.656 7.808 59.64 ;
     RECT  7.117 61.008 7.808 61.176 ;
     RECT  7.004 65.664 7.808 66.216 ;
     RECT  7.153 67.44 7.808 67.848 ;
     RECT  7.429 68.832 7.808 70.008 ;
     RECT  6.685 71.712 7.808 71.736 ;
     RECT  6.185 75.072 7.808 75.096 ;
     RECT  7.801 77.04 7.808 77.064 ;
     RECT  6.725 78.96 7.808 78.984 ;
     RECT  6.577 80.352 7.808 81.048 ;
     RECT  7.153 82.032 7.808 82.248 ;
     RECT  7.369 83.232 7.808 85.416 ;
     RECT  6.829 86.496 7.808 87.816 ;
     RECT  6.865 89.136 7.808 89.256 ;
     RECT  5.404 90.864 7.808 90.888 ;
     RECT  5.404 91.968 7.808 91.992 ;
     RECT  7.193 0.288 7.907 0.312 ;
     RECT  7.808 1.728 7.912 97.212 ;
     RECT  7.912 1.728 8.104 96.942 ;
     RECT  8.104 24.624 8.165 24.648 ;
     RECT  8.104 52.176 8.165 52.872 ;
     RECT  8.104 80.352 8.165 80.376 ;
     RECT  8.104 91.968 8.165 91.992 ;
     RECT  8.104 13.584 8.201 15 ;
     RECT  8.104 16.32 8.201 16.392 ;
     RECT  8.104 31.776 8.237 31.8 ;
     RECT  8.104 11.952 8.243 11.976 ;
     RECT  8.201 13.584 8.243 14.856 ;
     RECT  8.104 22.56 8.243 22.824 ;
     RECT  8.104 55.104 8.243 56.52 ;
     RECT  8.104 58.08 8.243 58.68 ;
     RECT  8.104 67.824 8.243 70.056 ;
     RECT  8.104 71.808 8.243 71.832 ;
     RECT  8.104 86.448 8.243 86.76 ;
     RECT  8.104 66.816 8.273 66.84 ;
     RECT  8.104 46.128 8.281 46.776 ;
     RECT  8.104 60.24 8.345 61.656 ;
     RECT  8.104 1.728 8.381 1.752 ;
     RECT  8.243 14.832 8.381 14.856 ;
     RECT  8.201 16.368 8.381 16.392 ;
     RECT  8.243 22.8 8.381 22.824 ;
     RECT  8.104 44.448 8.381 44.472 ;
     RECT  8.104 65.712 8.381 65.736 ;
     RECT  8.243 67.824 8.381 68.856 ;
     RECT  8.104 39.888 8.387 40.776 ;
     RECT  8.104 48.384 8.387 49.32 ;
     RECT  8.104 50.4 8.387 50.952 ;
     RECT  8.104 73.872 8.387 73.896 ;
     RECT  8.104 77.04 8.387 77.064 ;
     RECT  8.243 13.584 8.417 13.656 ;
     RECT  8.243 55.92 8.417 55.944 ;
     RECT  8.243 70.032 8.417 70.056 ;
     RECT  8.387 50.736 8.425 50.952 ;
     RECT  8.104 75.168 8.428 75.192 ;
     RECT  8.104 37.008 8.483 37.032 ;
     RECT  8.104 38.016 8.483 38.04 ;
     RECT  8.387 39.888 8.483 39.912 ;
     RECT  8.345 61.632 8.483 61.656 ;
     RECT  8.104 34.896 8.489 34.92 ;
     RECT  8.165 52.848 8.489 52.872 ;
     RECT  8.243 58.08 8.489 58.104 ;
     RECT  8.104 63.264 8.489 63.288 ;
     RECT  8.104 83.472 8.489 85.416 ;
     RECT  8.104 93.216 8.531 93.24 ;
     RECT  8.104 94.56 8.531 94.584 ;
     RECT  8.104 25.776 8.561 25.8 ;
     RECT  8.417 13.584 8.597 13.608 ;
     RECT  8.381 68.832 8.597 68.856 ;
     RECT  8.104 2.784 8.705 7.464 ;
     RECT  8.705 2.784 9.245 5.832 ;
     RECT  8.104 88.944 9.353 89.256 ;
     RECT  9.521 1.728 9.997 1.752 ;
     RECT  9.245 2.784 9.997 5.736 ;
     RECT  9.997 1.728 10.309 5.736 ;
     RECT  10.309 1.728 10.508 5.784 ;
     RECT  8.705 7.44 10.508 7.464 ;
     RECT  8.104 18 10.508 18.168 ;
     RECT  8.425 50.928 10.508 50.952 ;
     RECT  8.104 78.96 10.508 78.984 ;
     RECT  8.489 83.472 10.508 83.496 ;
     RECT  8.489 84.912 10.508 85.416 ;
     RECT  8.243 86.496 10.508 86.76 ;
     RECT  9.353 88.944 10.508 88.968 ;
     RECT  8.104 95.904 10.508 95.928 ;
     RECT  10.508 1.728 10.612 97.212 ;
     RECT  10.612 1.728 10.721 96.942 ;
     RECT  10.721 2.418 10.804 96.942 ;
     RECT  10.804 84.816 10.865 85.416 ;
     RECT  10.804 2.688 10.937 5.784 ;
     RECT  10.357 0.288 11.249 0.312 ;
     RECT  10.804 18 11.261 18.792 ;
     RECT  11.249 0.288 11.333 1.272 ;
     RECT  11.333 0.288 11.405 0.312 ;
     RECT  11.261 18.768 11.699 18.792 ;
     RECT  10.804 78.96 11.729 78.984 ;
     RECT  10.937 2.688 11.989 5.736 ;
     RECT  11.989 1.728 12.517 5.736 ;
     RECT  11.509 0.192 12.557 0.216 ;
     RECT  12.517 1.728 13.208 6.072 ;
     RECT  10.804 7.44 13.208 7.464 ;
     RECT  12.373 49.2 13.208 49.224 ;
     RECT  12.373 78.672 13.208 78.696 ;
     RECT  10.804 83.472 13.208 83.496 ;
     RECT  10.865 84.912 13.208 85.416 ;
     RECT  10.804 86.496 13.208 86.76 ;
     RECT  10.804 95.664 13.208 95.928 ;
     RECT  13.148 0.528 13.235 0.552 ;
     RECT  13.208 1.728 13.312 97.212 ;
     RECT  13.312 1.728 13.504 96.942 ;
     RECT  13.504 1.728 13.529 1.8 ;
     RECT  13.504 83.232 13.645 83.256 ;
     RECT  13.529 1.728 13.669 1.752 ;
     RECT  13.669 1.152 13.781 1.752 ;
     RECT  13.504 84.912 13.925 85.416 ;
     RECT  13.925 84.912 14.185 84.984 ;
     RECT  13.781 1.728 14.597 1.752 ;
     RECT  13.504 52.416 14.821 52.728 ;
     RECT  14.597 1.728 14.825 1.8 ;
     RECT  14.825 1.776 14.933 1.8 ;
     RECT  13.504 2.784 15.781 6.072 ;
     RECT  15.397 0.576 15.833 0.6 ;
     RECT  15.781 2.256 15.908 6.072 ;
     RECT  13.504 7.44 15.908 7.464 ;
     RECT  13.504 49.2 15.908 49.224 ;
     RECT  14.821 52.272 15.908 52.728 ;
     RECT  14.185 84.912 15.908 84.936 ;
     RECT  13.504 86.496 15.908 86.76 ;
     RECT  13.504 95.664 15.908 95.928 ;
     RECT  15.865 0.192 15.949 0.216 ;
     RECT  15.908 2.148 16.012 97.212 ;
     RECT  16.012 2.148 16.117 96.942 ;
     RECT  16.117 1.728 16.204 96.942 ;
     RECT  16.204 10.8 16.373 10.824 ;
     RECT  16.204 84.384 16.561 84.408 ;
     RECT  16.204 86.064 16.885 86.76 ;
     RECT  16.837 0.288 16.985 0.312 ;
     RECT  17.317 0.576 17.453 0.6 ;
     RECT  16.885 86.64 17.597 86.76 ;
     RECT  16.204 49.2 17.749 49.848 ;
     RECT  16.204 1.728 18.173 6.072 ;
     RECT  18.173 2.016 18.608 6.072 ;
     RECT  16.204 7.44 18.608 7.464 ;
     RECT  17.749 49.2 18.608 50.04 ;
     RECT  16.204 51.36 18.608 52.728 ;
     RECT  17.597 86.64 18.608 86.664 ;
     RECT  16.204 95.664 18.608 95.688 ;
     RECT  18.608 2.016 18.712 97.212 ;
     RECT  18.712 2.016 18.904 96.942 ;
     RECT  18.904 2.016 19.139 6.072 ;
     RECT  19.105 0.192 19.283 0.216 ;
     RECT  19.139 2.016 19.717 5.736 ;
     RECT  19.717 1.728 20.924 5.736 ;
     RECT  20.924 1.68 21.011 5.736 ;
     RECT  21.011 1.728 21.109 5.736 ;
     RECT  21.109 1.728 21.308 5.784 ;
     RECT  18.904 49.2 21.308 50.04 ;
     RECT  18.904 51.36 21.308 51.384 ;
     RECT  18.904 52.416 21.308 52.728 ;
     RECT  18.904 95.664 21.308 95.688 ;
     RECT  21.308 1.728 21.412 97.212 ;
     RECT  21.109 0.192 21.491 0.216 ;
     RECT  21.412 1.728 21.604 96.942 ;
     RECT  21.604 1.728 22.637 6.216 ;
     RECT  23.125 0.192 23.213 0.216 ;
     RECT  21.604 51.36 23.893 51.384 ;
     RECT  21.604 52.416 23.893 52.728 ;
     RECT  22.637 1.728 24.008 5.736 ;
     RECT  21.604 49.2 24.008 50.04 ;
     RECT  23.893 51.36 24.008 52.728 ;
     RECT  21.604 95.664 24.008 95.688 ;
     RECT  24.008 1.728 24.112 97.212 ;
     RECT  24.112 1.728 24.304 96.942 ;
     RECT  24.304 1.728 24.689 5.256 ;
     RECT  24.304 6.48 24.803 6.504 ;
     RECT  24.325 0.192 25.049 0.216 ;
     RECT  24.689 3.312 25.409 5.256 ;
     RECT  24.689 1.728 25.909 2.328 ;
     RECT  25.909 1.728 26.057 2.376 ;
     RECT  25.253 0.576 26.225 0.6 ;
     RECT  26.225 0.576 26.309 1.176 ;
     RECT  25.409 3.408 26.533 5.256 ;
     RECT  26.057 2.148 26.708 2.376 ;
     RECT  26.533 3.408 26.708 5.304 ;
     RECT  24.304 49.2 26.708 50.04 ;
     RECT  24.304 51.36 26.708 52.728 ;
     RECT  24.304 95.664 26.708 95.688 ;
     RECT  26.708 2.148 26.812 97.212 ;
     RECT  26.812 2.148 27.004 96.942 ;
     RECT  26.773 0.192 27.155 0.264 ;
     RECT  27.004 2.148 27.353 5.304 ;
     RECT  27.485 1.728 27.733 1.752 ;
     RECT  27.353 2.832 27.821 5.304 ;
     RECT  27.733 1.152 27.857 1.752 ;
     RECT  27.857 1.728 28.604 1.752 ;
     RECT  27.821 2.832 28.604 5.256 ;
     RECT  28.604 1.728 28.897 5.256 ;
     RECT  28.897 1.152 29.173 5.256 ;
     RECT  29.173 1.152 29.408 5.544 ;
     RECT  27.004 49.2 29.408 50.04 ;
     RECT  27.004 51.36 29.408 51.384 ;
     RECT  27.004 52.416 29.408 52.728 ;
     RECT  27.004 95.664 29.408 95.688 ;
     RECT  29.408 1.152 29.512 97.212 ;
     RECT  29.512 1.152 29.704 96.942 ;
     RECT  29.704 1.152 29.843 5.736 ;
     RECT  30.373 0.192 30.737 0.216 ;
     RECT  29.704 51.36 30.769 51.384 ;
     RECT  29.704 52.416 30.769 52.728 ;
     RECT  29.843 1.776 30.777 5.736 ;
     RECT  30.777 1.776 31.273 6.12 ;
     RECT  31.273 1.776 31.301 6.312 ;
     RECT  31.301 1.728 32.108 6.312 ;
     RECT  29.704 49.2 32.108 50.04 ;
     RECT  30.769 51.36 32.108 52.728 ;
     RECT  29.704 95.664 32.108 95.688 ;
     RECT  32.108 1.728 32.212 97.212 ;
     RECT  32.212 1.728 32.404 96.942 ;
     RECT  32.404 1.728 32.609 6.12 ;
     RECT  32.609 1.728 33.749 1.752 ;
     RECT  33.749 1.728 34.621 1.8 ;
     RECT  32.609 2.784 34.621 6.12 ;
     RECT  32.404 49.2 34.765 50.04 ;
     RECT  32.404 51.36 34.765 52.728 ;
     RECT  34.621 1.728 34.808 6.12 ;
     RECT  34.765 49.2 34.808 52.728 ;
     RECT  32.404 95.664 34.808 95.688 ;
     RECT  34.808 1.728 34.912 97.212 ;
     RECT  34.912 1.728 35.104 96.942 ;
     RECT  35.104 49.2 35.603 53.064 ;
     RECT  35.104 1.728 36.209 6.12 ;
     RECT  36.38 0.192 36.467 0.216 ;
     RECT  36.209 1.728 36.713 1.752 ;
     RECT  37.141 0.576 37.253 0.6 ;
     RECT  36.209 2.88 37.393 6.12 ;
     RECT  37.393 2.016 37.508 6.12 ;
     RECT  35.603 49.2 37.508 52.728 ;
     RECT  35.104 95.664 37.508 95.688 ;
     RECT  37.508 2.016 37.612 97.212 ;
     RECT  37.612 2.016 37.804 96.942 ;
     RECT  37.804 49.2 38.081 51.384 ;
     RECT  37.804 2.016 38.149 6.84 ;
     RECT  38.149 1.728 38.405 6.84 ;
     RECT  38.405 1.728 38.473 5.832 ;
     RECT  37.804 95.664 38.513 95.688 ;
     RECT  38.473 1.152 38.621 5.832 ;
     RECT  38.621 1.152 38.629 1.752 ;
     RECT  38.629 0.576 38.657 1.752 ;
     RECT  38.621 3.024 38.657 5.832 ;
     RECT  38.405 6.816 38.668 6.84 ;
     RECT  38.657 0.576 38.729 0.6 ;
     RECT  38.081 51.072 38.773 51.384 ;
     RECT  37.804 52.416 38.773 52.728 ;
     RECT  38.861 98.016 38.945 98.04 ;
     RECT  38.657 1.728 39.161 1.752 ;
     RECT  38.657 3.024 39.589 5.064 ;
     RECT  38.081 49.2 39.661 50.04 ;
     RECT  38.773 51.072 39.661 52.728 ;
     RECT  39.589 2.976 39.697 5.064 ;
     RECT  39.697 2.832 39.733 5.064 ;
     RECT  39.733 2.256 39.829 5.064 ;
     RECT  40.069 0.192 40.205 0.216 ;
     RECT  39.829 2.256 40.208 5.736 ;
     RECT  39.661 49.2 40.208 52.728 ;
     RECT  40.208 2.148 40.309 97.212 ;
     RECT  40.309 2.016 40.312 97.212 ;
     RECT  40.312 2.016 40.504 96.942 ;
     RECT  40.504 2.016 40.549 5.256 ;
     RECT  40.549 1.776 41.029 5.256 ;
     RECT  41.029 1.728 41.357 5.256 ;
     RECT  41.357 1.776 41.429 5.256 ;
     RECT  41.857 54.72 41.941 54.744 ;
     RECT  41.429 2.16 42.421 5.256 ;
     RECT  42.421 1.92 42.908 5.256 ;
     RECT  40.504 48.144 42.908 48.168 ;
     RECT  40.504 49.2 42.908 52.728 ;
     RECT  42.908 1.92 42.949 97.212 ;
     RECT  42.949 1.728 43.012 97.212 ;
     RECT  43.012 1.728 43.085 96.942 ;
     RECT  43.085 1.92 43.204 96.942 ;
     RECT  43.217 0.192 43.301 0.216 ;
     RECT  43.436 0.528 43.523 0.552 ;
     RECT  43.204 55.296 43.619 55.464 ;
     RECT  43.619 55.296 43.763 55.32 ;
     RECT  44.437 0.192 44.525 0.216 ;
     RECT  43.204 1.92 44.636 5.256 ;
     RECT  44.636 1.008 44.737 5.256 ;
     RECT  44.737 1.008 44.953 5.352 ;
     RECT  44.953 1.008 44.963 5.496 ;
     RECT  44.963 1.728 45.608 5.496 ;
     RECT  43.204 48.144 45.608 48.168 ;
     RECT  43.204 49.2 45.608 52.728 ;
     RECT  44.701 57.6 45.608 57.624 ;
     RECT  45.608 1.728 45.712 97.212 ;
     RECT  45.712 1.728 45.904 96.942 ;
     RECT  45.637 0.576 46.073 0.6 ;
     RECT  45.904 1.728 48.308 6.888 ;
     RECT  45.904 47.04 48.308 47.064 ;
     RECT  45.904 48.144 48.308 48.168 ;
     RECT  45.904 49.2 48.308 52.728 ;
     RECT  47.509 62.736 48.308 62.76 ;
     RECT  48.308 1.728 48.412 97.212 ;
     RECT  48.412 1.728 48.521 96.942 ;
     RECT  48.181 0.192 48.565 0.216 ;
     RECT  48.521 1.92 48.604 96.942 ;
     RECT  48.565 0.192 48.803 0.312 ;
     RECT  48.604 1.92 48.989 5.976 ;
     RECT  48.989 1.92 49.601 5.688 ;
     RECT  48.803 0.192 49.961 0.216 ;
     RECT  49.601 1.92 50.245 5.496 ;
     RECT  50.245 1.728 50.821 5.496 ;
     RECT  50.821 1.104 51.008 5.496 ;
     RECT  48.604 47.04 51.008 47.064 ;
     RECT  48.604 48.144 51.008 48.168 ;
     RECT  48.604 49.2 51.008 52.728 ;
     RECT  48.604 63.264 51.008 63.864 ;
     RECT  50.425 65.568 51.008 65.592 ;
     RECT  51.008 1.104 51.011 97.212 ;
     RECT  51.011 1.728 51.112 97.212 ;
     RECT  51.112 1.728 51.304 96.942 ;
     RECT  51.685 0.144 51.869 0.168 ;
     RECT  51.304 1.728 52.229 5.496 ;
     RECT  52.645 0.192 53.669 0.216 ;
     RECT  52.229 1.92 53.708 5.496 ;
     RECT  51.304 47.04 53.708 47.064 ;
     RECT  51.304 48.144 53.708 48.168 ;
     RECT  51.304 49.2 53.708 52.728 ;
     RECT  53.449 67.872 53.708 67.896 ;
     RECT  53.665 69.552 53.708 69.576 ;
     RECT  53.708 1.92 53.812 97.212 ;
     RECT  53.812 1.92 54.004 96.942 ;
     RECT  53.845 0.288 54.131 0.312 ;
     RECT  54.004 69.552 54.659 69.576 ;
     RECT  54.004 1.92 55.001 6.408 ;
     RECT  55.001 1.92 55.061 6.264 ;
     RECT  55.061 1.728 55.333 6.264 ;
     RECT  55.333 1.152 55.757 6.264 ;
     RECT  55.757 1.728 56.408 6.264 ;
     RECT  56.149 20.4 56.408 20.424 ;
     RECT  54.004 47.04 56.408 47.064 ;
     RECT  54.004 48.144 56.408 48.168 ;
     RECT  54.004 49.2 56.408 52.728 ;
     RECT  55.573 71.28 56.408 71.304 ;
     RECT  56.408 1.728 56.512 97.212 ;
     RECT  56.512 1.728 56.704 96.942 ;
     RECT  56.293 0.576 56.909 0.6 ;
     RECT  56.704 72.96 57.299 73.56 ;
     RECT  56.704 20.4 57.347 20.424 ;
     RECT  57.299 72.96 57.635 72.984 ;
     RECT  56.704 1.728 57.845 5.736 ;
     RECT  57.733 0.192 58.213 0.216 ;
     RECT  57.845 4.416 58.417 5.736 ;
     RECT  58.213 0.192 58.457 0.6 ;
     RECT  58.457 0.192 58.853 0.312 ;
     RECT  57.845 1.728 59.108 3.384 ;
     RECT  58.417 4.416 59.108 6.6 ;
     RECT  58.417 10.8 59.108 10.824 ;
     RECT  56.704 47.04 59.108 47.064 ;
     RECT  56.704 48.144 59.108 48.168 ;
     RECT  56.704 49.2 59.108 52.728 ;
     RECT  58.381 75.264 59.108 75.288 ;
     RECT  58.309 76.368 59.108 76.392 ;
     RECT  59.108 1.728 59.212 97.212 ;
     RECT  58.853 0.288 59.219 0.312 ;
     RECT  59.212 1.728 59.404 96.942 ;
     RECT  60.173 0.192 60.257 0.216 ;
     RECT  59.404 1.728 60.292 5.736 ;
     RECT  60.292 1.68 60.467 5.736 ;
     RECT  60.467 1.728 60.908 5.736 ;
     RECT  60.908 1.728 61.808 6.264 ;
     RECT  59.404 47.04 61.808 47.064 ;
     RECT  59.404 48.144 61.808 48.168 ;
     RECT  59.404 49.2 61.808 52.728 ;
     RECT  61.808 1.728 61.912 97.212 ;
     RECT  61.912 1.728 62.104 96.942 ;
     RECT  62.104 1.728 62.341 5.736 ;
     RECT  62.341 1.152 62.633 5.736 ;
     RECT  62.104 57.6 62.819 57.624 ;
     RECT  62.633 1.728 63.541 5.736 ;
     RECT  63.301 0.576 64.181 0.6 ;
     RECT  63.541 1.728 64.508 5.784 ;
     RECT  63.709 10.8 64.508 10.824 ;
     RECT  62.104 47.04 64.508 47.064 ;
     RECT  62.104 48.144 64.508 48.168 ;
     RECT  62.104 49.2 64.508 53.064 ;
     RECT  64.508 1.728 64.612 97.212 ;
     RECT  64.612 1.728 64.804 96.942 ;
     RECT  64.804 1.728 65.068 6.264 ;
     RECT  65.068 1.728 65.333 5.736 ;
     RECT  64.804 49.2 65.585 52.728 ;
     RECT  64.501 0.192 65.969 0.216 ;
     RECT  65.969 0.192 66.053 0.6 ;
     RECT  65.585 49.584 66.161 52.728 ;
     RECT  65.333 1.92 66.233 5.736 ;
     RECT  66.053 0.192 66.341 0.216 ;
     RECT  66.233 1.92 66.373 3.144 ;
     RECT  66.373 1.68 66.515 3.144 ;
     RECT  66.515 1.728 67.208 3.144 ;
     RECT  66.233 4.176 67.208 5.736 ;
     RECT  64.804 47.04 67.208 47.064 ;
     RECT  64.804 48.144 67.208 48.168 ;
     RECT  66.161 49.584 67.208 52.296 ;
     RECT  67.208 1.728 67.312 97.212 ;
     RECT  67.312 1.728 67.504 96.942 ;
     RECT  67.504 49.824 68.099 50.424 ;
     RECT  68.149 0.528 68.356 0.552 ;
     RECT  67.504 1.728 68.465 5.736 ;
     RECT  68.099 49.824 68.579 49.848 ;
     RECT  68.356 0.528 68.629 0.6 ;
     RECT  68.629 0.192 68.861 0.6 ;
     RECT  68.465 1.728 69.733 5.208 ;
     RECT  69.733 1.728 69.908 5.592 ;
     RECT  67.504 48.144 69.908 48.168 ;
     RECT  69.908 1.728 70.012 97.212 ;
     RECT  70.012 1.728 70.204 96.942 ;
     RECT  70.204 1.728 70.733 5.832 ;
     RECT  68.861 0.192 70.913 0.216 ;
     RECT  70.733 1.728 71.233 5.112 ;
     RECT  71.233 1.104 71.273 5.112 ;
     RECT  71.273 1.104 71.525 4.92 ;
     RECT  71.525 1.728 72.241 4.92 ;
     RECT  72.241 1.728 72.608 5.112 ;
     RECT  72.608 1.728 72.712 97.212 ;
     RECT  72.712 1.728 72.904 96.942 ;
     RECT  73.177 0.528 73.283 0.552 ;
     RECT  72.904 1.728 73.289 3.72 ;
     RECT  73.289 1.776 73.577 3.72 ;
     RECT  72.904 4.752 73.757 4.776 ;
     RECT  73.577 1.824 73.829 3.72 ;
     RECT  73.829 1.92 73.865 3.72 ;
     RECT  73.865 1.92 74.153 2.904 ;
     RECT  74.153 1.92 74.801 1.944 ;
     RECT  75.308 2.148 75.412 97.212 ;
     RECT  75.412 2.418 75.604 96.942 ;
    LAYER M5 ;
     RECT  4.368 0.144 73.272 0.563 ;
     RECT  4.368 0.563 73.032 1.763 ;
     RECT  69.12 1.763 70.344 1.811 ;
     RECT  71.808 1.763 73.032 1.811 ;
     RECT  7.392 1.763 24.84 1.859 ;
     RECT  26.544 1.763 44.232 1.907 ;
     RECT  72.048 1.811 73.032 1.907 ;
     RECT  72.288 1.907 73.032 1.955 ;
     RECT  2.4 2.137 2.52 2.151 ;
     RECT  75.3 2.137 75.42 2.151 ;
     RECT  7.68 1.859 24.84 2.291 ;
     RECT  26.544 1.907 40.512 2.291 ;
     RECT  41.52 1.907 44.232 2.291 ;
     RECT  45.408 1.763 67.944 2.291 ;
     RECT  72.288 1.955 72.912 2.291 ;
     RECT  10.32 2.291 24.84 2.339 ;
     RECT  10.32 2.339 24.456 2.915 ;
     RECT  26.544 2.291 27.144 2.915 ;
     RECT  45.6 2.291 67.944 3.109 ;
     RECT  69.552 1.811 70.344 3.109 ;
     RECT  45.6 3.109 70.344 3.301 ;
     RECT  28.224 2.291 35.112 3.349 ;
     RECT  36.192 2.291 40.512 3.349 ;
     RECT  41.76 2.291 43.992 3.443 ;
     RECT  7.68 2.291 9.336 4.069 ;
     RECT  10.32 2.915 16.212 4.069 ;
     RECT  45.504 3.301 70.344 4.261 ;
     RECT  41.76 3.443 43.752 4.453 ;
     RECT  44.736 4.261 70.344 4.453 ;
     RECT  7.68 4.069 16.212 4.645 ;
     RECT  28.224 3.349 40.512 4.693 ;
     RECT  7.68 4.645 16.392 4.885 ;
     RECT  7.584 4.885 16.392 4.933 ;
     RECT  26.544 2.915 27.012 4.933 ;
     RECT  17.568 2.915 24.456 5.077 ;
     RECT  7.248 4.933 16.392 5.171 ;
     RECT  17.568 5.077 24.792 5.171 ;
     RECT  28.224 4.693 40.632 5.171 ;
     RECT  41.76 4.453 70.344 5.171 ;
     RECT  15.648 5.171 16.392 5.173 ;
     RECT  10.32 5.171 14.184 5.219 ;
     RECT  23.472 5.171 24.792 5.219 ;
     RECT  26.208 4.933 27.012 5.267 ;
     RECT  29.184 5.171 40.632 5.267 ;
     RECT  23.856 5.219 24.792 5.315 ;
     RECT  26.544 5.267 27.012 5.315 ;
     RECT  52.416 5.171 54.648 5.363 ;
     RECT  52.896 5.363 54.648 5.411 ;
     RECT  29.184 5.267 40.512 5.507 ;
     RECT  15.648 5.173 16.872 5.555 ;
     RECT  29.184 5.507 36.456 5.555 ;
     RECT  2.4 2.151 2.712 5.605 ;
     RECT  4.368 1.763 5.412 5.605 ;
     RECT  7.584 5.171 9.336 5.747 ;
     RECT  10.32 5.219 13.512 5.747 ;
     RECT  15.648 5.555 16.212 5.747 ;
     RECT  18.048 5.171 19.992 5.747 ;
     RECT  29.4 5.555 36.456 5.747 ;
     RECT  55.68 5.171 59.736 5.747 ;
     RECT  60.96 5.171 70.344 5.747 ;
     RECT  10.32 5.747 10.812 5.795 ;
     RECT  21.12 5.171 22.44 5.795 ;
     RECT  33.552 5.747 36.456 5.795 ;
     RECT  60.96 5.747 65.016 5.795 ;
     RECT  7.584 5.747 8.616 5.843 ;
     RECT  66.432 5.747 70.344 5.843 ;
     RECT  15.792 5.747 16.212 6.035 ;
     RECT  34.512 5.795 36.456 6.035 ;
     RECT  12.528 5.747 13.512 6.083 ;
     RECT  18.6 5.747 19.128 6.083 ;
     RECT  30.816 5.747 32.412 6.131 ;
     RECT  21.3 5.795 22.44 6.227 ;
     RECT  60.96 5.795 62.808 6.275 ;
     RECT  64.176 5.795 65.016 6.275 ;
     RECT  31.296 6.131 32.412 6.323 ;
     RECT  24 5.315 24.792 6.515 ;
     RECT  37.5 5.507 40.512 6.851 ;
     RECT  41.904 5.171 51.312 6.899 ;
     RECT  2.4 5.605 5.412 8.485 ;
     RECT  2.4 8.485 5.544 8.579 ;
     RECT  4.368 8.579 5.544 10.549 ;
     RECT  3.792 10.549 5.544 10.981 ;
     RECT  7.584 5.843 8.112 11.411 ;
     RECT  7.8 11.411 8.112 11.941 ;
     RECT  3.792 10.981 6.312 12.515 ;
     RECT  7.8 11.941 8.232 14.867 ;
     RECT  3.792 12.515 5.544 15.395 ;
     RECT  4.368 15.395 5.544 15.637 ;
     RECT  7.8 14.867 8.112 16.357 ;
     RECT  4.368 15.637 5.688 16.501 ;
     RECT  7.8 16.357 8.232 17.077 ;
     RECT  7.488 17.077 8.232 18.035 ;
     RECT  10.5 5.795 10.812 18.757 ;
     RECT  7.488 18.035 8.112 18.851 ;
     RECT  3.984 16.501 5.688 21.107 ;
     RECT  4.368 21.107 5.688 22.211 ;
     RECT  7.8 18.851 8.112 22.549 ;
     RECT  7.8 22.549 8.232 22.835 ;
     RECT  7.8 22.835 8.112 23.845 ;
     RECT  7.104 23.845 8.112 25.427 ;
     RECT  7.8 25.427 8.112 29.029 ;
     RECT  4.368 22.211 5.544 29.653 ;
     RECT  7.008 29.029 8.112 29.653 ;
     RECT  4.368 29.653 8.112 36.997 ;
     RECT  2.4 8.579 2.712 39.301 ;
     RECT  4.368 36.997 8.472 39.301 ;
     RECT  2.4 39.301 8.472 39.923 ;
     RECT  2.4 39.923 8.376 41.939 ;
     RECT  3.888 41.939 8.376 43.283 ;
     RECT  66.432 5.843 70.212 47.075 ;
     RECT  4.368 43.283 8.376 47.651 ;
     RECT  67.2 47.075 70.212 48.179 ;
     RECT  10.5 18.757 11.688 49.189 ;
     RECT  13.2 6.083 13.512 49.189 ;
     RECT  4.368 47.651 6.696 49.523 ;
     RECT  4.368 49.523 6.456 49.619 ;
     RECT  5.1 49.619 6.456 49.811 ;
     RECT  15.9 6.035 16.212 49.813 ;
     RECT  67.2 48.179 68.568 49.859 ;
     RECT  18.6 6.083 18.912 50.005 ;
     RECT  34.8 6.035 36.456 50.195 ;
     RECT  67.2 49.859 68.088 50.435 ;
     RECT  7.8 47.651 8.376 50.771 ;
     RECT  38.784 6.851 40.512 50.771 ;
     RECT  41.904 6.899 45.912 50.771 ;
     RECT  15.9 49.813 16.536 51.349 ;
     RECT  17.76 50.005 18.912 51.349 ;
     RECT  6.432 49.811 6.456 51.877 ;
     RECT  38.784 50.771 38.808 51.923 ;
     RECT  41.904 50.771 43.752 51.923 ;
     RECT  24 6.515 24.312 52.261 ;
     RECT  10.5 49.189 13.512 52.405 ;
     RECT  23.904 52.261 24.312 52.451 ;
     RECT  10.5 52.405 13.608 52.693 ;
     RECT  7.8 50.771 8.112 52.837 ;
     RECT  34.8 50.195 35.592 53.075 ;
     RECT  64.176 6.275 64.812 53.075 ;
     RECT  41.904 51.923 41.928 54.755 ;
     RECT  5.1 49.811 5.412 54.997 ;
     RECT  6.432 51.877 6.552 54.997 ;
     RECT  5.1 54.997 6.552 55.043 ;
     RECT  42.9 51.923 43.752 55.331 ;
     RECT  42.9 55.331 43.608 55.475 ;
     RECT  44.736 50.771 45.912 57.635 ;
     RECT  61.8 6.275 62.808 57.635 ;
     RECT  5.1 55.043 6.456 58.645 ;
     RECT  7.8 52.837 8.232 58.645 ;
     RECT  5.1 58.645 8.232 61.043 ;
     RECT  7.8 61.043 8.232 61.621 ;
     RECT  47.52 6.899 51.312 62.771 ;
     RECT  0.192 62.677 0.216 62.819 ;
     RECT  7.8 61.621 8.472 63.299 ;
     RECT  48.3 62.771 51.312 63.875 ;
     RECT  50.448 63.875 51.312 65.603 ;
     RECT  5.1 61.043 6.456 65.653 ;
     RECT  7.8 63.299 8.112 65.653 ;
     RECT  5.1 65.653 8.112 65.701 ;
     RECT  5.1 65.701 8.232 66.227 ;
     RECT  7.8 66.227 8.232 66.851 ;
     RECT  53.52 5.411 54.648 67.907 ;
     RECT  7.8 66.851 8.112 68.245 ;
     RECT  7.8 68.245 8.232 68.821 ;
     RECT  53.7 67.907 54.648 69.587 ;
     RECT  7.44 68.821 8.232 70.019 ;
     RECT  5.1 66.227 6.456 70.163 ;
     RECT  55.68 5.747 59.412 71.315 ;
     RECT  56.4 71.315 59.412 72.995 ;
     RECT  56.4 72.995 57.288 73.571 ;
     RECT  7.8 70.019 8.232 73.861 ;
     RECT  5.1 70.163 5.592 75.781 ;
     RECT  4.56 75.781 5.592 76.165 ;
     RECT  4.56 76.165 5.688 76.307 ;
     RECT  58.32 72.995 59.412 76.403 ;
     RECT  4.56 76.307 5.544 76.979 ;
     RECT  7.8 73.861 8.376 77.075 ;
     RECT  10.5 52.693 14.136 78.707 ;
     RECT  5.1 76.979 5.544 78.949 ;
     RECT  7.8 77.075 8.112 80.341 ;
     RECT  6.864 80.341 8.112 82.259 ;
     RECT  5.1 78.949 5.592 83.557 ;
     RECT  7.8 82.259 8.112 84.325 ;
     RECT  4.992 83.557 5.592 84.661 ;
     RECT  13.2 78.707 14.136 84.995 ;
     RECT  4.992 84.661 5.832 85.381 ;
     RECT  4.752 85.381 5.832 85.811 ;
     RECT  15.9 51.349 18.912 86.099 ;
     RECT  17.76 86.099 18.912 86.675 ;
     RECT  4.752 85.811 5.688 86.869 ;
     RECT  7.8 84.325 8.232 87.157 ;
     RECT  4.656 86.869 5.688 87.251 ;
     RECT  6.864 87.157 8.232 87.827 ;
     RECT  4.656 87.251 5.544 88.355 ;
     RECT  7.8 87.827 8.232 88.933 ;
     RECT  4.752 88.355 5.544 89.171 ;
     RECT  4.752 89.171 5.412 90.275 ;
     RECT  7.8 88.933 8.52 94.595 ;
     RECT  10.5 78.707 11.688 95.699 ;
     RECT  7.8 94.595 8.376 95.939 ;
     RECT  2.4 41.939 2.712 97.209 ;
     RECT  5.1 90.275 5.412 97.209 ;
     RECT  7.8 95.939 8.112 97.209 ;
     RECT  10.5 95.699 10.812 97.209 ;
     RECT  13.2 84.995 13.512 97.209 ;
     RECT  15.9 86.099 16.212 97.209 ;
     RECT  18.6 86.675 18.912 97.209 ;
     RECT  21.3 6.227 21.612 97.209 ;
     RECT  24 52.451 24.312 97.209 ;
     RECT  26.7 5.315 27.012 97.209 ;
     RECT  29.4 5.747 29.712 97.209 ;
     RECT  32.1 6.323 32.412 97.209 ;
     RECT  34.8 53.075 35.112 97.209 ;
     RECT  37.5 6.851 37.812 97.209 ;
     RECT  40.2 50.771 40.512 97.209 ;
     RECT  42.9 55.475 43.212 97.209 ;
     RECT  45.6 57.635 45.912 97.209 ;
     RECT  48.3 63.875 48.612 97.209 ;
     RECT  51 65.603 51.312 97.209 ;
     RECT  53.7 69.587 54.012 97.209 ;
     RECT  56.4 73.571 56.712 97.209 ;
     RECT  59.1 76.403 59.412 97.209 ;
     RECT  61.8 57.635 62.112 97.209 ;
     RECT  64.5 53.075 64.812 97.209 ;
     RECT  67.2 50.435 67.512 97.209 ;
     RECT  69.9 48.179 70.212 97.209 ;
     RECT  72.6 2.291 72.912 97.209 ;
     RECT  75.3 2.151 75.612 97.209 ;
     RECT  2.4 97.209 2.52 97.223 ;
     RECT  5.1 97.209 5.22 97.223 ;
     RECT  7.8 97.209 7.92 97.223 ;
     RECT  10.5 97.209 10.62 97.223 ;
     RECT  13.2 97.209 13.32 97.223 ;
     RECT  15.9 97.209 16.02 97.223 ;
     RECT  18.6 97.209 18.72 97.223 ;
     RECT  21.3 97.209 21.42 97.223 ;
     RECT  24 97.209 24.12 97.223 ;
     RECT  26.7 97.209 26.82 97.223 ;
     RECT  29.4 97.209 29.52 97.223 ;
     RECT  32.1 97.209 32.22 97.223 ;
     RECT  34.8 97.209 34.92 97.223 ;
     RECT  37.5 97.209 37.62 97.223 ;
     RECT  40.2 97.209 40.32 97.223 ;
     RECT  42.9 97.209 43.02 97.223 ;
     RECT  45.6 97.209 45.72 97.223 ;
     RECT  48.3 97.209 48.42 97.223 ;
     RECT  51 97.209 51.12 97.223 ;
     RECT  53.7 97.209 53.82 97.223 ;
     RECT  56.4 97.209 56.52 97.223 ;
     RECT  59.1 97.209 59.22 97.223 ;
     RECT  61.8 97.209 61.92 97.223 ;
     RECT  64.5 97.209 64.62 97.223 ;
     RECT  67.2 97.209 67.32 97.223 ;
     RECT  69.9 97.209 70.02 97.223 ;
     RECT  72.6 97.209 72.72 97.223 ;
     RECT  75.3 97.209 75.42 97.223 ;
     RECT  44.232 1.763 45.408 2.291 ;
     RECT  67.944 1.763 69.12 1.811 ;
     RECT  70.344 1.763 71.808 1.811 ;
     RECT  67.944 1.811 69.552 3.109 ;
     RECT  40.512 1.907 41.52 2.291 ;
     RECT  9.336 2.291 10.32 4.069 ;
     RECT  27.144 2.291 28.224 2.915 ;
     RECT  35.112 2.291 36.192 3.349 ;
     RECT  40.512 2.291 41.76 4.693 ;
     RECT  43.992 2.291 45.6 3.301 ;
     RECT  16.212 2.915 17.568 4.645 ;
     RECT  27.012 2.915 28.224 5.171 ;
     RECT  43.992 3.301 45.504 3.443 ;
     RECT  43.752 3.443 45.504 4.261 ;
     RECT  43.752 4.261 44.736 4.453 ;
     RECT  16.392 4.645 17.568 5.171 ;
     RECT  40.632 4.693 41.76 5.171 ;
     RECT  24.792 5.077 26.208 5.267 ;
     RECT  9.336 5.171 10.32 5.747 ;
     RECT  14.184 5.171 15.648 5.219 ;
     RECT  16.392 5.171 18.048 5.173 ;
     RECT  19.992 5.171 21.12 5.747 ;
     RECT  22.44 5.171 23.472 5.219 ;
     RECT  40.632 5.171 41.904 5.267 ;
     RECT  51.312 5.171 52.416 5.363 ;
     RECT  54.648 5.171 55.68 69.587 ;
     RECT  59.736 5.171 60.96 5.747 ;
     RECT  16.872 5.173 18.048 5.555 ;
     RECT  22.44 5.219 23.856 5.315 ;
     RECT  40.512 5.267 41.904 54.755 ;
     RECT  36.456 5.507 37.5 50.195 ;
     RECT  29.712 5.747 30.816 6.131 ;
     RECT  32.412 5.747 33.552 5.795 ;
     RECT  65.016 5.747 66.432 6.275 ;
     RECT  62.808 5.795 64.176 53.075 ;
     RECT  37.812 6.851 38.784 51.923 ;
     RECT  2.712 10.549 3.792 15.395 ;
     RECT  6.312 10.981 7.584 11.411 ;
     RECT  6.312 11.411 7.8 12.515 ;
     RECT  8.112 14.867 8.232 16.357 ;
     RECT  2.712 15.395 4.368 16.501 ;
     RECT  2.712 16.501 3.984 21.107 ;
     RECT  11.688 18.757 13.2 49.189 ;
     RECT  5.544 29.029 7.008 29.653 ;
     RECT  2.712 41.939 3.888 43.283 ;
     RECT  6.696 47.651 7.8 49.523 ;
     RECT  68.568 48.179 69.9 49.859 ;
     RECT  6.456 49.523 7.8 51.877 ;
     RECT  5.412 49.811 6.432 54.997 ;
     RECT  16.536 50.005 17.76 51.349 ;
     RECT  38.808 50.771 40.2 51.923 ;
     RECT  43.752 50.771 44.736 55.331 ;
     RECT  6.552 51.877 7.8 55.043 ;
     RECT  41.928 51.923 42.9 54.755 ;
     RECT  6.456 55.043 7.8 58.645 ;
     RECT  43.608 55.331 44.736 55.475 ;
     RECT  43.212 55.475 44.736 57.635 ;
     RECT  6.456 61.043 7.8 65.653 ;
     RECT  6.456 66.227 7.8 68.821 ;
     RECT  8.112 66.851 8.232 68.245 ;
     RECT  6.456 68.821 7.44 70.019 ;
     RECT  6.456 70.019 7.8 70.163 ;
     RECT  57.288 72.995 58.32 73.571 ;
     RECT  11.688 78.707 13.2 95.699 ;
     RECT  5.592 80.341 6.864 82.259 ;
     RECT  5.688 85.811 5.832 87.157 ;
     RECT  5.688 87.157 6.864 87.251 ;
     RECT  5.544 87.251 6.864 87.827 ;
  END
END dsfd_l2r_vr_564x1__hx_E
END LIBRARY
